VERSION 5.8 ;
BUSBITCHARS "[]" ;
DIVIDERCHAR "/" ;
UNITS
    DATABASE MICRONS 1000 ;
END UNITS

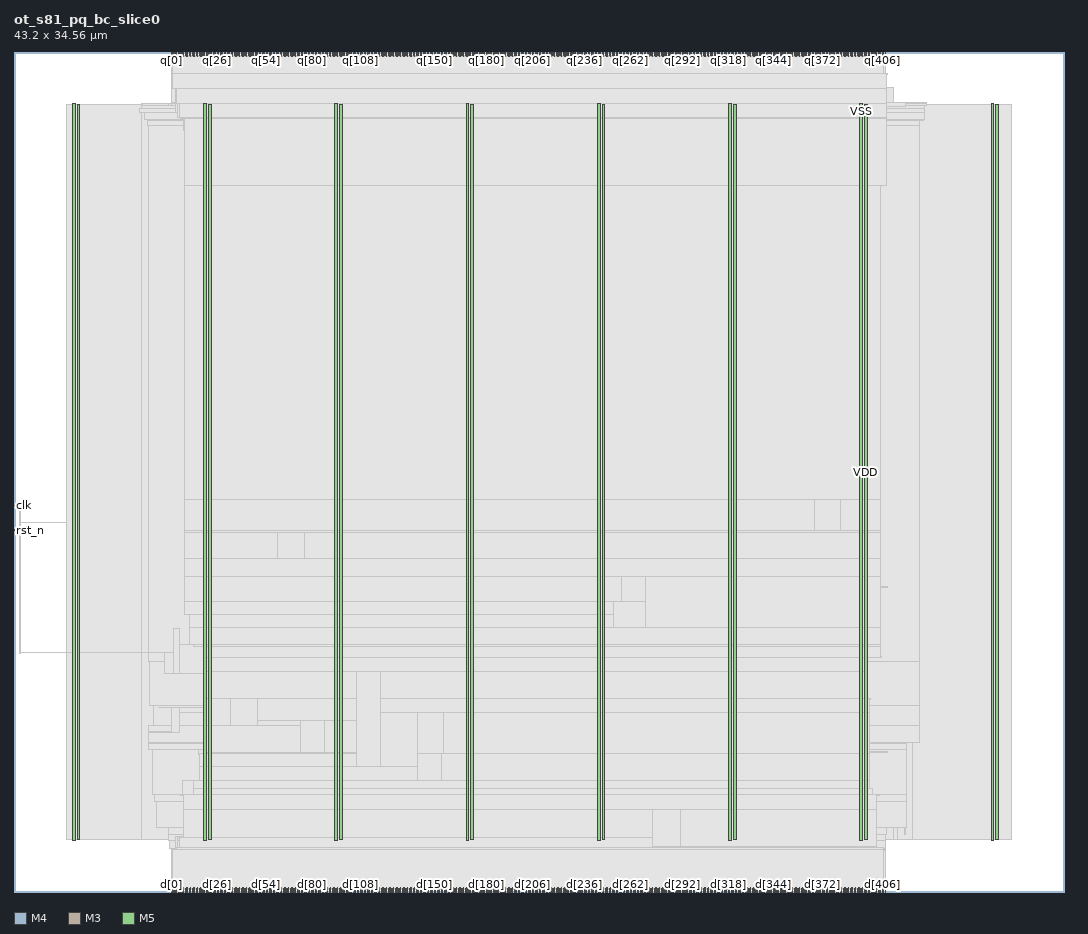
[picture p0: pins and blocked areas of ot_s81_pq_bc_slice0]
MACRO ot_s81_pq_bc_slice0
  FOREIGN ot_s81_pq_bc_slice0 0 0 ;
  CLASS BLOCK ;
  SIZE 43.2 BY 34.56 ;
  PIN clk
    DIRECTION INPUT ;
    USE SIGNAL ;
    PORT
      LAYER M4 ;
        RECT  0 15.888 0.192 15.912 ;
    END
    PORT
      LAYER M4 ;
        RECT  0.156 15.888 0.275 15.912 ;
    END
  END clk
  PIN d[0]
    DIRECTION INPUT ;
    USE SIGNAL ;
    PORT
      LAYER M3 ;
        RECT  6.48 0 6.498 0.144 ;
    END
  END d[0]
  PIN d[100]
    DIRECTION INPUT ;
    USE SIGNAL ;
    PORT
      LAYER M3 ;
        RECT  13.68 0 13.698 0.144 ;
    END
  END d[100]
  PIN d[101]
    DIRECTION INPUT ;
    USE SIGNAL ;
    PORT
      LAYER M5 ;
        RECT  13.728 0 13.752 0.192 ;
    END
  END d[101]
  PIN d[102]
    DIRECTION INPUT ;
    USE SIGNAL ;
    PORT
      LAYER M3 ;
        RECT  13.824 0 13.842 0.144 ;
    END
  END d[102]
  PIN d[103]
    DIRECTION INPUT ;
    USE SIGNAL ;
    PORT
      LAYER M5 ;
        RECT  13.872 0 13.896 0.192 ;
    END
  END d[103]
  PIN d[104]
    DIRECTION INPUT ;
    USE SIGNAL ;
    PORT
      LAYER M3 ;
        RECT  13.968 0 13.986 0.144 ;
    END
  END d[104]
  PIN d[105]
    DIRECTION INPUT ;
    USE SIGNAL ;
    PORT
      LAYER M5 ;
        RECT  14.016 0 14.04 0.192 ;
    END
  END d[105]
  PIN d[106]
    DIRECTION INPUT ;
    USE SIGNAL ;
    PORT
      LAYER M3 ;
        RECT  14.112 0 14.13 0.144 ;
    END
  END d[106]
  PIN d[107]
    DIRECTION INPUT ;
    USE SIGNAL ;
    PORT
      LAYER M5 ;
        RECT  14.16 0 14.184 0.192 ;
    END
  END d[107]
  PIN d[108]
    DIRECTION INPUT ;
    USE SIGNAL ;
    PORT
      LAYER M3 ;
        RECT  14.256 0 14.274 0.144 ;
    END
  END d[108]
  PIN d[109]
    DIRECTION INPUT ;
    USE SIGNAL ;
    PORT
      LAYER M5 ;
        RECT  14.304 0 14.328 0.192 ;
    END
  END d[109]
  PIN d[10]
    DIRECTION INPUT ;
    USE SIGNAL ;
    PORT
      LAYER M3 ;
        RECT  7.2 0 7.218 0.144 ;
    END
  END d[10]
  PIN d[110]
    DIRECTION INPUT ;
    USE SIGNAL ;
    PORT
      LAYER M3 ;
        RECT  14.4 0 14.418 0.144 ;
    END
  END d[110]
  PIN d[111]
    DIRECTION INPUT ;
    USE SIGNAL ;
    PORT
      LAYER M5 ;
        RECT  14.448 0 14.472 0.192 ;
    END
  END d[111]
  PIN d[112]
    DIRECTION INPUT ;
    USE SIGNAL ;
    PORT
      LAYER M3 ;
        RECT  14.544 0 14.562 0.144 ;
    END
  END d[112]
  PIN d[113]
    DIRECTION INPUT ;
    USE SIGNAL ;
    PORT
      LAYER M5 ;
        RECT  14.592 0 14.616 0.192 ;
    END
  END d[113]
  PIN d[114]
    DIRECTION INPUT ;
    USE SIGNAL ;
    PORT
      LAYER M3 ;
        RECT  14.688 0 14.706 0.144 ;
    END
  END d[114]
  PIN d[115]
    DIRECTION INPUT ;
    USE SIGNAL ;
    PORT
      LAYER M5 ;
        RECT  14.736 0 14.76 0.192 ;
    END
  END d[115]
  PIN d[116]
    DIRECTION INPUT ;
    USE SIGNAL ;
    PORT
      LAYER M3 ;
        RECT  14.832 0 14.85 0.144 ;
    END
  END d[116]
  PIN d[117]
    DIRECTION INPUT ;
    USE SIGNAL ;
    PORT
      LAYER M5 ;
        RECT  14.88 0 14.904 0.192 ;
    END
  END d[117]
  PIN d[118]
    DIRECTION INPUT ;
    USE SIGNAL ;
    PORT
      LAYER M3 ;
        RECT  14.976 0 14.994 0.144 ;
    END
  END d[118]
  PIN d[119]
    DIRECTION INPUT ;
    USE SIGNAL ;
    PORT
      LAYER M5 ;
        RECT  15.024 0 15.048 0.192 ;
    END
  END d[119]
  PIN d[11]
    DIRECTION INPUT ;
    USE SIGNAL ;
    PORT
      LAYER M5 ;
        RECT  7.248 0 7.272 0.192 ;
    END
  END d[11]
  PIN d[120]
    DIRECTION INPUT ;
    USE SIGNAL ;
    PORT
      LAYER M3 ;
        RECT  15.12 0 15.138 0.144 ;
    END
  END d[120]
  PIN d[121]
    DIRECTION INPUT ;
    USE SIGNAL ;
    PORT
      LAYER M5 ;
        RECT  15.168 0 15.192 0.192 ;
    END
  END d[121]
  PIN d[122]
    DIRECTION INPUT ;
    USE SIGNAL ;
    PORT
      LAYER M3 ;
        RECT  15.264 0 15.282 0.144 ;
    END
  END d[122]
  PIN d[123]
    DIRECTION INPUT ;
    USE SIGNAL ;
    PORT
      LAYER M5 ;
        RECT  15.312 0 15.336 0.192 ;
    END
  END d[123]
  PIN d[124]
    DIRECTION INPUT ;
    USE SIGNAL ;
    PORT
      LAYER M3 ;
        RECT  15.408 0 15.426 0.144 ;
    END
  END d[124]
  PIN d[125]
    DIRECTION INPUT ;
    USE SIGNAL ;
    PORT
      LAYER M5 ;
        RECT  15.456 0 15.48 0.192 ;
    END
  END d[125]
  PIN d[126]
    DIRECTION INPUT ;
    USE SIGNAL ;
    PORT
      LAYER M3 ;
        RECT  15.552 0 15.57 0.144 ;
    END
  END d[126]
  PIN d[127]
    DIRECTION INPUT ;
    USE SIGNAL ;
    PORT
      LAYER M5 ;
        RECT  15.6 0 15.624 0.192 ;
    END
  END d[127]
  PIN d[128]
    DIRECTION INPUT ;
    USE SIGNAL ;
    PORT
      LAYER M3 ;
        RECT  15.696 0 15.714 0.144 ;
    END
  END d[128]
  PIN d[129]
    DIRECTION INPUT ;
    USE SIGNAL ;
    PORT
      LAYER M5 ;
        RECT  15.744 0 15.768 0.192 ;
    END
  END d[129]
  PIN d[12]
    DIRECTION INPUT ;
    USE SIGNAL ;
    PORT
      LAYER M3 ;
        RECT  7.344 0 7.362 0.144 ;
    END
  END d[12]
  PIN d[130]
    DIRECTION INPUT ;
    USE SIGNAL ;
    PORT
      LAYER M3 ;
        RECT  15.84 0 15.858 0.144 ;
    END
  END d[130]
  PIN d[131]
    DIRECTION INPUT ;
    USE SIGNAL ;
    PORT
      LAYER M5 ;
        RECT  15.888 0 15.912 0.192 ;
    END
  END d[131]
  PIN d[132]
    DIRECTION INPUT ;
    USE SIGNAL ;
    PORT
      LAYER M3 ;
        RECT  15.984 0 16.002 0.144 ;
    END
  END d[132]
  PIN d[133]
    DIRECTION INPUT ;
    USE SIGNAL ;
    PORT
      LAYER M5 ;
        RECT  16.032 0 16.056 0.192 ;
    END
  END d[133]
  PIN d[134]
    DIRECTION INPUT ;
    USE SIGNAL ;
    PORT
      LAYER M3 ;
        RECT  16.128 0 16.146 0.144 ;
    END
  END d[134]
  PIN d[135]
    DIRECTION INPUT ;
    USE SIGNAL ;
    PORT
      LAYER M5 ;
        RECT  16.176 0 16.2 0.192 ;
    END
  END d[135]
  PIN d[136]
    DIRECTION INPUT ;
    USE SIGNAL ;
    PORT
      LAYER M3 ;
        RECT  16.272 0 16.29 0.144 ;
    END
  END d[136]
  PIN d[137]
    DIRECTION INPUT ;
    USE SIGNAL ;
    PORT
      LAYER M5 ;
        RECT  16.32 0 16.344 0.192 ;
    END
  END d[137]
  PIN d[138]
    DIRECTION INPUT ;
    USE SIGNAL ;
    PORT
      LAYER M3 ;
        RECT  16.416 0 16.434 0.144 ;
    END
  END d[138]
  PIN d[139]
    DIRECTION INPUT ;
    USE SIGNAL ;
    PORT
      LAYER M5 ;
        RECT  16.464 0 16.488 0.192 ;
    END
  END d[139]
  PIN d[13]
    DIRECTION INPUT ;
    USE SIGNAL ;
    PORT
      LAYER M5 ;
        RECT  7.392 0 7.416 0.192 ;
    END
  END d[13]
  PIN d[140]
    DIRECTION INPUT ;
    USE SIGNAL ;
    PORT
      LAYER M3 ;
        RECT  16.56 0 16.578 0.144 ;
    END
  END d[140]
  PIN d[141]
    DIRECTION INPUT ;
    USE SIGNAL ;
    PORT
      LAYER M5 ;
        RECT  16.608 0 16.632 0.192 ;
    END
  END d[141]
  PIN d[142]
    DIRECTION INPUT ;
    USE SIGNAL ;
    PORT
      LAYER M3 ;
        RECT  16.704 0 16.722 0.144 ;
    END
  END d[142]
  PIN d[143]
    DIRECTION INPUT ;
    USE SIGNAL ;
    PORT
      LAYER M5 ;
        RECT  16.752 0 16.776 0.192 ;
    END
  END d[143]
  PIN d[144]
    DIRECTION INPUT ;
    USE SIGNAL ;
    PORT
      LAYER M3 ;
        RECT  16.848 0 16.866 0.144 ;
    END
  END d[144]
  PIN d[145]
    DIRECTION INPUT ;
    USE SIGNAL ;
    PORT
      LAYER M5 ;
        RECT  16.896 0 16.92 0.192 ;
    END
  END d[145]
  PIN d[146]
    DIRECTION INPUT ;
    USE SIGNAL ;
    PORT
      LAYER M3 ;
        RECT  16.992 0 17.01 0.144 ;
    END
  END d[146]
  PIN d[147]
    DIRECTION INPUT ;
    USE SIGNAL ;
    PORT
      LAYER M5 ;
        RECT  17.04 0 17.064 0.192 ;
    END
  END d[147]
  PIN d[148]
    DIRECTION INPUT ;
    USE SIGNAL ;
    PORT
      LAYER M3 ;
        RECT  17.136 0 17.154 0.144 ;
    END
  END d[148]
  PIN d[149]
    DIRECTION INPUT ;
    USE SIGNAL ;
    PORT
      LAYER M5 ;
        RECT  17.184 0 17.208 0.192 ;
    END
  END d[149]
  PIN d[14]
    DIRECTION INPUT ;
    USE SIGNAL ;
    PORT
      LAYER M3 ;
        RECT  7.488 0 7.506 0.144 ;
    END
  END d[14]
  PIN d[150]
    DIRECTION INPUT ;
    USE SIGNAL ;
    PORT
      LAYER M3 ;
        RECT  17.28 0 17.298 0.144 ;
    END
  END d[150]
  PIN d[151]
    DIRECTION INPUT ;
    USE SIGNAL ;
    PORT
      LAYER M5 ;
        RECT  17.328 0 17.352 0.192 ;
    END
  END d[151]
  PIN d[152]
    DIRECTION INPUT ;
    USE SIGNAL ;
    PORT
      LAYER M3 ;
        RECT  17.424 0 17.442 0.144 ;
    END
  END d[152]
  PIN d[153]
    DIRECTION INPUT ;
    USE SIGNAL ;
    PORT
      LAYER M5 ;
        RECT  17.472 0 17.496 0.192 ;
    END
  END d[153]
  PIN d[154]
    DIRECTION INPUT ;
    USE SIGNAL ;
    PORT
      LAYER M3 ;
        RECT  17.568 0 17.586 0.144 ;
    END
  END d[154]
  PIN d[155]
    DIRECTION INPUT ;
    USE SIGNAL ;
    PORT
      LAYER M5 ;
        RECT  17.616 0 17.64 0.192 ;
    END
  END d[155]
  PIN d[156]
    DIRECTION INPUT ;
    USE SIGNAL ;
    PORT
      LAYER M3 ;
        RECT  17.712 0 17.73 0.144 ;
    END
  END d[156]
  PIN d[157]
    DIRECTION INPUT ;
    USE SIGNAL ;
    PORT
      LAYER M5 ;
        RECT  17.76 0 17.784 0.192 ;
    END
  END d[157]
  PIN d[158]
    DIRECTION INPUT ;
    USE SIGNAL ;
    PORT
      LAYER M3 ;
        RECT  17.856 0 17.874 0.144 ;
    END
  END d[158]
  PIN d[159]
    DIRECTION INPUT ;
    USE SIGNAL ;
    PORT
      LAYER M5 ;
        RECT  17.904 0 17.928 0.192 ;
    END
  END d[159]
  PIN d[15]
    DIRECTION INPUT ;
    USE SIGNAL ;
    PORT
      LAYER M5 ;
        RECT  7.536 0 7.56 0.192 ;
    END
  END d[15]
  PIN d[160]
    DIRECTION INPUT ;
    USE SIGNAL ;
    PORT
      LAYER M3 ;
        RECT  18 0 18.018 0.144 ;
    END
  END d[160]
  PIN d[161]
    DIRECTION INPUT ;
    USE SIGNAL ;
    PORT
      LAYER M5 ;
        RECT  18.048 0 18.072 0.192 ;
    END
  END d[161]
  PIN d[162]
    DIRECTION INPUT ;
    USE SIGNAL ;
    PORT
      LAYER M3 ;
        RECT  18.144 0 18.162 0.144 ;
    END
  END d[162]
  PIN d[163]
    DIRECTION INPUT ;
    USE SIGNAL ;
    PORT
      LAYER M5 ;
        RECT  18.192 0 18.216 0.192 ;
    END
  END d[163]
  PIN d[164]
    DIRECTION INPUT ;
    USE SIGNAL ;
    PORT
      LAYER M3 ;
        RECT  18.288 0 18.306 0.144 ;
    END
  END d[164]
  PIN d[165]
    DIRECTION INPUT ;
    USE SIGNAL ;
    PORT
      LAYER M5 ;
        RECT  18.336 0 18.36 0.192 ;
    END
  END d[165]
  PIN d[166]
    DIRECTION INPUT ;
    USE SIGNAL ;
    PORT
      LAYER M3 ;
        RECT  18.432 0 18.45 0.144 ;
    END
  END d[166]
  PIN d[167]
    DIRECTION INPUT ;
    USE SIGNAL ;
    PORT
      LAYER M5 ;
        RECT  18.48 0 18.504 0.192 ;
    END
  END d[167]
  PIN d[168]
    DIRECTION INPUT ;
    USE SIGNAL ;
    PORT
      LAYER M3 ;
        RECT  18.576 0 18.594 0.144 ;
    END
  END d[168]
  PIN d[169]
    DIRECTION INPUT ;
    USE SIGNAL ;
    PORT
      LAYER M5 ;
        RECT  18.624 0 18.648 0.192 ;
    END
  END d[169]
  PIN d[16]
    DIRECTION INPUT ;
    USE SIGNAL ;
    PORT
      LAYER M3 ;
        RECT  7.632 0 7.65 0.144 ;
    END
  END d[16]
  PIN d[170]
    DIRECTION INPUT ;
    USE SIGNAL ;
    PORT
      LAYER M3 ;
        RECT  18.72 0 18.738 0.144 ;
    END
  END d[170]
  PIN d[171]
    DIRECTION INPUT ;
    USE SIGNAL ;
    PORT
      LAYER M5 ;
        RECT  18.768 0 18.792 0.192 ;
    END
  END d[171]
  PIN d[172]
    DIRECTION INPUT ;
    USE SIGNAL ;
    PORT
      LAYER M3 ;
        RECT  18.864 0 18.882 0.144 ;
    END
  END d[172]
  PIN d[173]
    DIRECTION INPUT ;
    USE SIGNAL ;
    PORT
      LAYER M5 ;
        RECT  18.912 0 18.936 0.192 ;
    END
  END d[173]
  PIN d[174]
    DIRECTION INPUT ;
    USE SIGNAL ;
    PORT
      LAYER M3 ;
        RECT  19.008 0 19.026 0.144 ;
    END
  END d[174]
  PIN d[175]
    DIRECTION INPUT ;
    USE SIGNAL ;
    PORT
      LAYER M5 ;
        RECT  19.056 0 19.08 0.192 ;
    END
  END d[175]
  PIN d[176]
    DIRECTION INPUT ;
    USE SIGNAL ;
    PORT
      LAYER M3 ;
        RECT  19.152 0 19.17 0.144 ;
    END
  END d[176]
  PIN d[177]
    DIRECTION INPUT ;
    USE SIGNAL ;
    PORT
      LAYER M5 ;
        RECT  19.2 0 19.224 0.192 ;
    END
  END d[177]
  PIN d[178]
    DIRECTION INPUT ;
    USE SIGNAL ;
    PORT
      LAYER M3 ;
        RECT  19.296 0 19.314 0.144 ;
    END
  END d[178]
  PIN d[179]
    DIRECTION INPUT ;
    USE SIGNAL ;
    PORT
      LAYER M5 ;
        RECT  19.344 0 19.368 0.192 ;
    END
  END d[179]
  PIN d[17]
    DIRECTION INPUT ;
    USE SIGNAL ;
    PORT
      LAYER M5 ;
        RECT  7.68 0 7.704 0.192 ;
    END
  END d[17]
  PIN d[180]
    DIRECTION INPUT ;
    USE SIGNAL ;
    PORT
      LAYER M3 ;
        RECT  19.44 0 19.458 0.144 ;
    END
  END d[180]
  PIN d[181]
    DIRECTION INPUT ;
    USE SIGNAL ;
    PORT
      LAYER M5 ;
        RECT  19.488 0 19.512 0.192 ;
    END
  END d[181]
  PIN d[182]
    DIRECTION INPUT ;
    USE SIGNAL ;
    PORT
      LAYER M3 ;
        RECT  19.584 0 19.602 0.144 ;
    END
  END d[182]
  PIN d[183]
    DIRECTION INPUT ;
    USE SIGNAL ;
    PORT
      LAYER M5 ;
        RECT  19.632 0 19.656 0.192 ;
    END
  END d[183]
  PIN d[184]
    DIRECTION INPUT ;
    USE SIGNAL ;
    PORT
      LAYER M3 ;
        RECT  19.728 0 19.746 0.144 ;
    END
  END d[184]
  PIN d[185]
    DIRECTION INPUT ;
    USE SIGNAL ;
    PORT
      LAYER M5 ;
        RECT  19.776 0 19.8 0.192 ;
    END
  END d[185]
  PIN d[186]
    DIRECTION INPUT ;
    USE SIGNAL ;
    PORT
      LAYER M3 ;
        RECT  19.872 0 19.89 0.144 ;
    END
  END d[186]
  PIN d[187]
    DIRECTION INPUT ;
    USE SIGNAL ;
    PORT
      LAYER M5 ;
        RECT  19.92 0 19.944 0.192 ;
    END
  END d[187]
  PIN d[188]
    DIRECTION INPUT ;
    USE SIGNAL ;
    PORT
      LAYER M3 ;
        RECT  20.016 0 20.034 0.144 ;
    END
  END d[188]
  PIN d[189]
    DIRECTION INPUT ;
    USE SIGNAL ;
    PORT
      LAYER M5 ;
        RECT  20.064 0 20.088 0.192 ;
    END
  END d[189]
  PIN d[18]
    DIRECTION INPUT ;
    USE SIGNAL ;
    PORT
      LAYER M3 ;
        RECT  7.776 0 7.794 0.144 ;
    END
  END d[18]
  PIN d[190]
    DIRECTION INPUT ;
    USE SIGNAL ;
    PORT
      LAYER M3 ;
        RECT  20.16 0 20.178 0.144 ;
    END
  END d[190]
  PIN d[191]
    DIRECTION INPUT ;
    USE SIGNAL ;
    PORT
      LAYER M5 ;
        RECT  20.208 0 20.232 0.192 ;
    END
  END d[191]
  PIN d[192]
    DIRECTION INPUT ;
    USE SIGNAL ;
    PORT
      LAYER M3 ;
        RECT  20.304 0 20.322 0.144 ;
    END
  END d[192]
  PIN d[193]
    DIRECTION INPUT ;
    USE SIGNAL ;
    PORT
      LAYER M5 ;
        RECT  20.352 0 20.376 0.192 ;
    END
  END d[193]
  PIN d[194]
    DIRECTION INPUT ;
    USE SIGNAL ;
    PORT
      LAYER M3 ;
        RECT  20.448 0 20.466 0.144 ;
    END
  END d[194]
  PIN d[195]
    DIRECTION INPUT ;
    USE SIGNAL ;
    PORT
      LAYER M5 ;
        RECT  20.496 0 20.52 0.192 ;
    END
  END d[195]
  PIN d[196]
    DIRECTION INPUT ;
    USE SIGNAL ;
    PORT
      LAYER M3 ;
        RECT  20.592 0 20.61 0.144 ;
    END
  END d[196]
  PIN d[197]
    DIRECTION INPUT ;
    USE SIGNAL ;
    PORT
      LAYER M5 ;
        RECT  20.64 0 20.664 0.192 ;
    END
  END d[197]
  PIN d[198]
    DIRECTION INPUT ;
    USE SIGNAL ;
    PORT
      LAYER M3 ;
        RECT  20.736 0 20.754 0.144 ;
    END
  END d[198]
  PIN d[199]
    DIRECTION INPUT ;
    USE SIGNAL ;
    PORT
      LAYER M5 ;
        RECT  20.784 0 20.808 0.192 ;
    END
  END d[199]
  PIN d[19]
    DIRECTION INPUT ;
    USE SIGNAL ;
    PORT
      LAYER M5 ;
        RECT  7.824 0 7.848 0.192 ;
    END
  END d[19]
  PIN d[1]
    DIRECTION INPUT ;
    USE SIGNAL ;
    PORT
      LAYER M5 ;
        RECT  6.528 0 6.552 0.192 ;
    END
  END d[1]
  PIN d[200]
    DIRECTION INPUT ;
    USE SIGNAL ;
    PORT
      LAYER M3 ;
        RECT  20.88 0 20.898 0.144 ;
    END
  END d[200]
  PIN d[201]
    DIRECTION INPUT ;
    USE SIGNAL ;
    PORT
      LAYER M5 ;
        RECT  20.928 0 20.952 0.192 ;
    END
  END d[201]
  PIN d[202]
    DIRECTION INPUT ;
    USE SIGNAL ;
    PORT
      LAYER M3 ;
        RECT  21.024 0 21.042 0.144 ;
    END
  END d[202]
  PIN d[203]
    DIRECTION INPUT ;
    USE SIGNAL ;
    PORT
      LAYER M5 ;
        RECT  21.072 0 21.096 0.192 ;
    END
  END d[203]
  PIN d[204]
    DIRECTION INPUT ;
    USE SIGNAL ;
    PORT
      LAYER M3 ;
        RECT  21.168 0 21.186 0.144 ;
    END
  END d[204]
  PIN d[205]
    DIRECTION INPUT ;
    USE SIGNAL ;
    PORT
      LAYER M5 ;
        RECT  21.216 0 21.24 0.192 ;
    END
  END d[205]
  PIN d[206]
    DIRECTION INPUT ;
    USE SIGNAL ;
    PORT
      LAYER M3 ;
        RECT  21.312 0 21.33 0.144 ;
    END
  END d[206]
  PIN d[207]
    DIRECTION INPUT ;
    USE SIGNAL ;
    PORT
      LAYER M5 ;
        RECT  21.36 0 21.384 0.192 ;
    END
  END d[207]
  PIN d[208]
    DIRECTION INPUT ;
    USE SIGNAL ;
    PORT
      LAYER M3 ;
        RECT  21.456 0 21.474 0.144 ;
    END
  END d[208]
  PIN d[209]
    DIRECTION INPUT ;
    USE SIGNAL ;
    PORT
      LAYER M5 ;
        RECT  21.504 0 21.528 0.192 ;
    END
  END d[209]
  PIN d[20]
    DIRECTION INPUT ;
    USE SIGNAL ;
    PORT
      LAYER M3 ;
        RECT  7.92 0 7.938 0.144 ;
    END
  END d[20]
  PIN d[210]
    DIRECTION INPUT ;
    USE SIGNAL ;
    PORT
      LAYER M3 ;
        RECT  21.6 0 21.618 0.144 ;
    END
  END d[210]
  PIN d[211]
    DIRECTION INPUT ;
    USE SIGNAL ;
    PORT
      LAYER M5 ;
        RECT  21.648 0 21.672 0.192 ;
    END
  END d[211]
  PIN d[212]
    DIRECTION INPUT ;
    USE SIGNAL ;
    PORT
      LAYER M3 ;
        RECT  21.744 0 21.762 0.144 ;
    END
  END d[212]
  PIN d[213]
    DIRECTION INPUT ;
    USE SIGNAL ;
    PORT
      LAYER M5 ;
        RECT  21.792 0 21.816 0.192 ;
    END
  END d[213]
  PIN d[214]
    DIRECTION INPUT ;
    USE SIGNAL ;
    PORT
      LAYER M3 ;
        RECT  21.888 0 21.906 0.144 ;
    END
  END d[214]
  PIN d[215]
    DIRECTION INPUT ;
    USE SIGNAL ;
    PORT
      LAYER M5 ;
        RECT  21.936 0 21.96 0.192 ;
    END
  END d[215]
  PIN d[216]
    DIRECTION INPUT ;
    USE SIGNAL ;
    PORT
      LAYER M3 ;
        RECT  22.032 0 22.05 0.144 ;
    END
  END d[216]
  PIN d[217]
    DIRECTION INPUT ;
    USE SIGNAL ;
    PORT
      LAYER M5 ;
        RECT  22.08 0 22.104 0.192 ;
    END
  END d[217]
  PIN d[218]
    DIRECTION INPUT ;
    USE SIGNAL ;
    PORT
      LAYER M3 ;
        RECT  22.176 0 22.194 0.144 ;
    END
  END d[218]
  PIN d[219]
    DIRECTION INPUT ;
    USE SIGNAL ;
    PORT
      LAYER M5 ;
        RECT  22.224 0 22.248 0.192 ;
    END
  END d[219]
  PIN d[21]
    DIRECTION INPUT ;
    USE SIGNAL ;
    PORT
      LAYER M5 ;
        RECT  7.968 0 7.992 0.192 ;
    END
  END d[21]
  PIN d[220]
    DIRECTION INPUT ;
    USE SIGNAL ;
    PORT
      LAYER M3 ;
        RECT  22.32 0 22.338 0.144 ;
    END
  END d[220]
  PIN d[221]
    DIRECTION INPUT ;
    USE SIGNAL ;
    PORT
      LAYER M5 ;
        RECT  22.368 0 22.392 0.192 ;
    END
  END d[221]
  PIN d[222]
    DIRECTION INPUT ;
    USE SIGNAL ;
    PORT
      LAYER M3 ;
        RECT  22.464 0 22.482 0.144 ;
    END
  END d[222]
  PIN d[223]
    DIRECTION INPUT ;
    USE SIGNAL ;
    PORT
      LAYER M5 ;
        RECT  22.512 0 22.536 0.192 ;
    END
  END d[223]
  PIN d[224]
    DIRECTION INPUT ;
    USE SIGNAL ;
    PORT
      LAYER M3 ;
        RECT  22.608 0 22.626 0.144 ;
    END
  END d[224]
  PIN d[225]
    DIRECTION INPUT ;
    USE SIGNAL ;
    PORT
      LAYER M5 ;
        RECT  22.656 0 22.68 0.192 ;
    END
  END d[225]
  PIN d[226]
    DIRECTION INPUT ;
    USE SIGNAL ;
    PORT
      LAYER M3 ;
        RECT  22.752 0 22.77 0.144 ;
    END
  END d[226]
  PIN d[227]
    DIRECTION INPUT ;
    USE SIGNAL ;
    PORT
      LAYER M5 ;
        RECT  22.8 0 22.824 0.192 ;
    END
  END d[227]
  PIN d[228]
    DIRECTION INPUT ;
    USE SIGNAL ;
    PORT
      LAYER M3 ;
        RECT  22.896 0 22.914 0.144 ;
    END
  END d[228]
  PIN d[229]
    DIRECTION INPUT ;
    USE SIGNAL ;
    PORT
      LAYER M5 ;
        RECT  22.944 0 22.968 0.192 ;
    END
  END d[229]
  PIN d[22]
    DIRECTION INPUT ;
    USE SIGNAL ;
    PORT
      LAYER M3 ;
        RECT  8.064 0 8.082 0.144 ;
    END
  END d[22]
  PIN d[230]
    DIRECTION INPUT ;
    USE SIGNAL ;
    PORT
      LAYER M3 ;
        RECT  23.04 0 23.058 0.144 ;
    END
  END d[230]
  PIN d[231]
    DIRECTION INPUT ;
    USE SIGNAL ;
    PORT
      LAYER M5 ;
        RECT  23.088 0 23.112 0.192 ;
    END
  END d[231]
  PIN d[232]
    DIRECTION INPUT ;
    USE SIGNAL ;
    PORT
      LAYER M3 ;
        RECT  23.184 0 23.202 0.144 ;
    END
  END d[232]
  PIN d[233]
    DIRECTION INPUT ;
    USE SIGNAL ;
    PORT
      LAYER M5 ;
        RECT  23.232 0 23.256 0.192 ;
    END
  END d[233]
  PIN d[234]
    DIRECTION INPUT ;
    USE SIGNAL ;
    PORT
      LAYER M3 ;
        RECT  23.328 0 23.346 0.144 ;
    END
  END d[234]
  PIN d[235]
    DIRECTION INPUT ;
    USE SIGNAL ;
    PORT
      LAYER M5 ;
        RECT  23.376 0 23.4 0.192 ;
    END
  END d[235]
  PIN d[236]
    DIRECTION INPUT ;
    USE SIGNAL ;
    PORT
      LAYER M3 ;
        RECT  23.472 0 23.49 0.144 ;
    END
  END d[236]
  PIN d[237]
    DIRECTION INPUT ;
    USE SIGNAL ;
    PORT
      LAYER M5 ;
        RECT  23.52 0 23.544 0.192 ;
    END
  END d[237]
  PIN d[238]
    DIRECTION INPUT ;
    USE SIGNAL ;
    PORT
      LAYER M3 ;
        RECT  23.616 0 23.634 0.144 ;
    END
  END d[238]
  PIN d[239]
    DIRECTION INPUT ;
    USE SIGNAL ;
    PORT
      LAYER M5 ;
        RECT  23.664 0 23.688 0.192 ;
    END
  END d[239]
  PIN d[23]
    DIRECTION INPUT ;
    USE SIGNAL ;
    PORT
      LAYER M5 ;
        RECT  8.112 0 8.136 0.192 ;
    END
  END d[23]
  PIN d[240]
    DIRECTION INPUT ;
    USE SIGNAL ;
    PORT
      LAYER M3 ;
        RECT  23.76 0 23.778 0.144 ;
    END
  END d[240]
  PIN d[241]
    DIRECTION INPUT ;
    USE SIGNAL ;
    PORT
      LAYER M5 ;
        RECT  23.808 0 23.832 0.192 ;
    END
  END d[241]
  PIN d[242]
    DIRECTION INPUT ;
    USE SIGNAL ;
    PORT
      LAYER M3 ;
        RECT  23.904 0 23.922 0.144 ;
    END
  END d[242]
  PIN d[243]
    DIRECTION INPUT ;
    USE SIGNAL ;
    PORT
      LAYER M5 ;
        RECT  23.952 0 23.976 0.192 ;
    END
  END d[243]
  PIN d[244]
    DIRECTION INPUT ;
    USE SIGNAL ;
    PORT
      LAYER M3 ;
        RECT  24.048 0 24.066 0.144 ;
    END
  END d[244]
  PIN d[245]
    DIRECTION INPUT ;
    USE SIGNAL ;
    PORT
      LAYER M5 ;
        RECT  24.096 0 24.12 0.192 ;
    END
  END d[245]
  PIN d[246]
    DIRECTION INPUT ;
    USE SIGNAL ;
    PORT
      LAYER M3 ;
        RECT  24.192 0 24.21 0.144 ;
    END
  END d[246]
  PIN d[247]
    DIRECTION INPUT ;
    USE SIGNAL ;
    PORT
      LAYER M5 ;
        RECT  24.24 0 24.264 0.192 ;
    END
  END d[247]
  PIN d[248]
    DIRECTION INPUT ;
    USE SIGNAL ;
    PORT
      LAYER M3 ;
        RECT  24.336 0 24.354 0.144 ;
    END
  END d[248]
  PIN d[249]
    DIRECTION INPUT ;
    USE SIGNAL ;
    PORT
      LAYER M5 ;
        RECT  24.384 0 24.408 0.192 ;
    END
  END d[249]
  PIN d[24]
    DIRECTION INPUT ;
    USE SIGNAL ;
    PORT
      LAYER M3 ;
        RECT  8.208 0 8.226 0.144 ;
    END
  END d[24]
  PIN d[250]
    DIRECTION INPUT ;
    USE SIGNAL ;
    PORT
      LAYER M3 ;
        RECT  24.48 0 24.498 0.144 ;
    END
  END d[250]
  PIN d[251]
    DIRECTION INPUT ;
    USE SIGNAL ;
    PORT
      LAYER M5 ;
        RECT  24.528 0 24.552 0.192 ;
    END
  END d[251]
  PIN d[252]
    DIRECTION INPUT ;
    USE SIGNAL ;
    PORT
      LAYER M3 ;
        RECT  24.624 0 24.642 0.144 ;
    END
  END d[252]
  PIN d[253]
    DIRECTION INPUT ;
    USE SIGNAL ;
    PORT
      LAYER M5 ;
        RECT  24.672 0 24.696 0.192 ;
    END
  END d[253]
  PIN d[254]
    DIRECTION INPUT ;
    USE SIGNAL ;
    PORT
      LAYER M3 ;
        RECT  24.768 0 24.786 0.144 ;
    END
  END d[254]
  PIN d[255]
    DIRECTION INPUT ;
    USE SIGNAL ;
    PORT
      LAYER M5 ;
        RECT  24.816 0 24.84 0.192 ;
    END
  END d[255]
  PIN d[256]
    DIRECTION INPUT ;
    USE SIGNAL ;
    PORT
      LAYER M3 ;
        RECT  24.912 0 24.93 0.144 ;
    END
  END d[256]
  PIN d[257]
    DIRECTION INPUT ;
    USE SIGNAL ;
    PORT
      LAYER M5 ;
        RECT  24.96 0 24.984 0.192 ;
    END
  END d[257]
  PIN d[258]
    DIRECTION INPUT ;
    USE SIGNAL ;
    PORT
      LAYER M3 ;
        RECT  25.056 0 25.074 0.144 ;
    END
  END d[258]
  PIN d[259]
    DIRECTION INPUT ;
    USE SIGNAL ;
    PORT
      LAYER M5 ;
        RECT  25.104 0 25.128 0.192 ;
    END
  END d[259]
  PIN d[25]
    DIRECTION INPUT ;
    USE SIGNAL ;
    PORT
      LAYER M5 ;
        RECT  8.256 0 8.28 0.192 ;
    END
  END d[25]
  PIN d[260]
    DIRECTION INPUT ;
    USE SIGNAL ;
    PORT
      LAYER M3 ;
        RECT  25.2 0 25.218 0.144 ;
    END
  END d[260]
  PIN d[261]
    DIRECTION INPUT ;
    USE SIGNAL ;
    PORT
      LAYER M5 ;
        RECT  25.248 0 25.272 0.192 ;
    END
  END d[261]
  PIN d[262]
    DIRECTION INPUT ;
    USE SIGNAL ;
    PORT
      LAYER M3 ;
        RECT  25.344 0 25.362 0.144 ;
    END
  END d[262]
  PIN d[263]
    DIRECTION INPUT ;
    USE SIGNAL ;
    PORT
      LAYER M5 ;
        RECT  25.392 0 25.416 0.192 ;
    END
  END d[263]
  PIN d[264]
    DIRECTION INPUT ;
    USE SIGNAL ;
    PORT
      LAYER M3 ;
        RECT  25.488 0 25.506 0.144 ;
    END
  END d[264]
  PIN d[265]
    DIRECTION INPUT ;
    USE SIGNAL ;
    PORT
      LAYER M5 ;
        RECT  25.536 0 25.56 0.192 ;
    END
  END d[265]
  PIN d[266]
    DIRECTION INPUT ;
    USE SIGNAL ;
    PORT
      LAYER M3 ;
        RECT  25.632 0 25.65 0.144 ;
    END
  END d[266]
  PIN d[267]
    DIRECTION INPUT ;
    USE SIGNAL ;
    PORT
      LAYER M5 ;
        RECT  25.68 0 25.704 0.192 ;
    END
  END d[267]
  PIN d[268]
    DIRECTION INPUT ;
    USE SIGNAL ;
    PORT
      LAYER M3 ;
        RECT  25.776 0 25.794 0.144 ;
    END
  END d[268]
  PIN d[269]
    DIRECTION INPUT ;
    USE SIGNAL ;
    PORT
      LAYER M5 ;
        RECT  25.824 0 25.848 0.192 ;
    END
  END d[269]
  PIN d[26]
    DIRECTION INPUT ;
    USE SIGNAL ;
    PORT
      LAYER M3 ;
        RECT  8.352 0 8.37 0.144 ;
    END
  END d[26]
  PIN d[270]
    DIRECTION INPUT ;
    USE SIGNAL ;
    PORT
      LAYER M3 ;
        RECT  25.92 0 25.938 0.144 ;
    END
  END d[270]
  PIN d[271]
    DIRECTION INPUT ;
    USE SIGNAL ;
    PORT
      LAYER M5 ;
        RECT  25.968 0 25.992 0.192 ;
    END
  END d[271]
  PIN d[272]
    DIRECTION INPUT ;
    USE SIGNAL ;
    PORT
      LAYER M3 ;
        RECT  26.064 0 26.082 0.144 ;
    END
  END d[272]
  PIN d[273]
    DIRECTION INPUT ;
    USE SIGNAL ;
    PORT
      LAYER M5 ;
        RECT  26.112 0 26.136 0.192 ;
    END
  END d[273]
  PIN d[274]
    DIRECTION INPUT ;
    USE SIGNAL ;
    PORT
      LAYER M3 ;
        RECT  26.208 0 26.226 0.144 ;
    END
  END d[274]
  PIN d[275]
    DIRECTION INPUT ;
    USE SIGNAL ;
    PORT
      LAYER M5 ;
        RECT  26.256 0 26.28 0.192 ;
    END
  END d[275]
  PIN d[276]
    DIRECTION INPUT ;
    USE SIGNAL ;
    PORT
      LAYER M3 ;
        RECT  26.352 0 26.37 0.144 ;
    END
  END d[276]
  PIN d[277]
    DIRECTION INPUT ;
    USE SIGNAL ;
    PORT
      LAYER M5 ;
        RECT  26.4 0 26.424 0.192 ;
    END
  END d[277]
  PIN d[278]
    DIRECTION INPUT ;
    USE SIGNAL ;
    PORT
      LAYER M3 ;
        RECT  26.496 0 26.514 0.144 ;
    END
  END d[278]
  PIN d[279]
    DIRECTION INPUT ;
    USE SIGNAL ;
    PORT
      LAYER M5 ;
        RECT  26.544 0 26.568 0.192 ;
    END
  END d[279]
  PIN d[27]
    DIRECTION INPUT ;
    USE SIGNAL ;
    PORT
      LAYER M5 ;
        RECT  8.4 0 8.424 0.192 ;
    END
  END d[27]
  PIN d[280]
    DIRECTION INPUT ;
    USE SIGNAL ;
    PORT
      LAYER M3 ;
        RECT  26.64 0 26.658 0.144 ;
    END
  END d[280]
  PIN d[281]
    DIRECTION INPUT ;
    USE SIGNAL ;
    PORT
      LAYER M5 ;
        RECT  26.688 0 26.712 0.192 ;
    END
  END d[281]
  PIN d[282]
    DIRECTION INPUT ;
    USE SIGNAL ;
    PORT
      LAYER M3 ;
        RECT  26.784 0 26.802 0.144 ;
    END
  END d[282]
  PIN d[283]
    DIRECTION INPUT ;
    USE SIGNAL ;
    PORT
      LAYER M5 ;
        RECT  26.832 0 26.856 0.192 ;
    END
  END d[283]
  PIN d[284]
    DIRECTION INPUT ;
    USE SIGNAL ;
    PORT
      LAYER M3 ;
        RECT  26.928 0 26.946 0.144 ;
    END
  END d[284]
  PIN d[285]
    DIRECTION INPUT ;
    USE SIGNAL ;
    PORT
      LAYER M5 ;
        RECT  26.976 0 27 0.192 ;
    END
  END d[285]
  PIN d[286]
    DIRECTION INPUT ;
    USE SIGNAL ;
    PORT
      LAYER M3 ;
        RECT  27.072 0 27.09 0.144 ;
    END
  END d[286]
  PIN d[287]
    DIRECTION INPUT ;
    USE SIGNAL ;
    PORT
      LAYER M5 ;
        RECT  27.12 0 27.144 0.192 ;
    END
  END d[287]
  PIN d[288]
    DIRECTION INPUT ;
    USE SIGNAL ;
    PORT
      LAYER M3 ;
        RECT  27.216 0 27.234 0.144 ;
    END
  END d[288]
  PIN d[289]
    DIRECTION INPUT ;
    USE SIGNAL ;
    PORT
      LAYER M5 ;
        RECT  27.264 0 27.288 0.192 ;
    END
  END d[289]
  PIN d[28]
    DIRECTION INPUT ;
    USE SIGNAL ;
    PORT
      LAYER M3 ;
        RECT  8.496 0 8.514 0.144 ;
    END
  END d[28]
  PIN d[290]
    DIRECTION INPUT ;
    USE SIGNAL ;
    PORT
      LAYER M3 ;
        RECT  27.36 0 27.378 0.144 ;
    END
  END d[290]
  PIN d[291]
    DIRECTION INPUT ;
    USE SIGNAL ;
    PORT
      LAYER M5 ;
        RECT  27.408 0 27.432 0.192 ;
    END
  END d[291]
  PIN d[292]
    DIRECTION INPUT ;
    USE SIGNAL ;
    PORT
      LAYER M3 ;
        RECT  27.504 0 27.522 0.144 ;
    END
  END d[292]
  PIN d[293]
    DIRECTION INPUT ;
    USE SIGNAL ;
    PORT
      LAYER M5 ;
        RECT  27.552 0 27.576 0.192 ;
    END
  END d[293]
  PIN d[294]
    DIRECTION INPUT ;
    USE SIGNAL ;
    PORT
      LAYER M3 ;
        RECT  27.648 0 27.666 0.144 ;
    END
  END d[294]
  PIN d[295]
    DIRECTION INPUT ;
    USE SIGNAL ;
    PORT
      LAYER M5 ;
        RECT  27.696 0 27.72 0.192 ;
    END
  END d[295]
  PIN d[296]
    DIRECTION INPUT ;
    USE SIGNAL ;
    PORT
      LAYER M3 ;
        RECT  27.792 0 27.81 0.144 ;
    END
  END d[296]
  PIN d[297]
    DIRECTION INPUT ;
    USE SIGNAL ;
    PORT
      LAYER M5 ;
        RECT  27.84 0 27.864 0.192 ;
    END
  END d[297]
  PIN d[298]
    DIRECTION INPUT ;
    USE SIGNAL ;
    PORT
      LAYER M3 ;
        RECT  27.936 0 27.954 0.144 ;
    END
  END d[298]
  PIN d[299]
    DIRECTION INPUT ;
    USE SIGNAL ;
    PORT
      LAYER M5 ;
        RECT  27.984 0 28.008 0.192 ;
    END
  END d[299]
  PIN d[29]
    DIRECTION INPUT ;
    USE SIGNAL ;
    PORT
      LAYER M5 ;
        RECT  8.544 0 8.568 0.192 ;
    END
  END d[29]
  PIN d[2]
    DIRECTION INPUT ;
    USE SIGNAL ;
    PORT
      LAYER M3 ;
        RECT  6.624 0 6.642 0.144 ;
    END
  END d[2]
  PIN d[300]
    DIRECTION INPUT ;
    USE SIGNAL ;
    PORT
      LAYER M3 ;
        RECT  28.08 0 28.098 0.144 ;
    END
  END d[300]
  PIN d[301]
    DIRECTION INPUT ;
    USE SIGNAL ;
    PORT
      LAYER M5 ;
        RECT  28.128 0 28.152 0.192 ;
    END
  END d[301]
  PIN d[302]
    DIRECTION INPUT ;
    USE SIGNAL ;
    PORT
      LAYER M3 ;
        RECT  28.224 0 28.242 0.144 ;
    END
  END d[302]
  PIN d[303]
    DIRECTION INPUT ;
    USE SIGNAL ;
    PORT
      LAYER M5 ;
        RECT  28.272 0 28.296 0.192 ;
    END
  END d[303]
  PIN d[304]
    DIRECTION INPUT ;
    USE SIGNAL ;
    PORT
      LAYER M3 ;
        RECT  28.368 0 28.386 0.144 ;
    END
  END d[304]
  PIN d[305]
    DIRECTION INPUT ;
    USE SIGNAL ;
    PORT
      LAYER M5 ;
        RECT  28.416 0 28.44 0.192 ;
    END
  END d[305]
  PIN d[306]
    DIRECTION INPUT ;
    USE SIGNAL ;
    PORT
      LAYER M3 ;
        RECT  28.512 0 28.53 0.144 ;
    END
  END d[306]
  PIN d[307]
    DIRECTION INPUT ;
    USE SIGNAL ;
    PORT
      LAYER M5 ;
        RECT  28.56 0 28.584 0.192 ;
    END
  END d[307]
  PIN d[308]
    DIRECTION INPUT ;
    USE SIGNAL ;
    PORT
      LAYER M3 ;
        RECT  28.656 0 28.674 0.144 ;
    END
  END d[308]
  PIN d[309]
    DIRECTION INPUT ;
    USE SIGNAL ;
    PORT
      LAYER M5 ;
        RECT  28.704 0 28.728 0.192 ;
    END
  END d[309]
  PIN d[30]
    DIRECTION INPUT ;
    USE SIGNAL ;
    PORT
      LAYER M3 ;
        RECT  8.64 0 8.658 0.144 ;
    END
  END d[30]
  PIN d[310]
    DIRECTION INPUT ;
    USE SIGNAL ;
    PORT
      LAYER M3 ;
        RECT  28.8 0 28.818 0.144 ;
    END
  END d[310]
  PIN d[311]
    DIRECTION INPUT ;
    USE SIGNAL ;
    PORT
      LAYER M5 ;
        RECT  28.848 0 28.872 0.192 ;
    END
  END d[311]
  PIN d[312]
    DIRECTION INPUT ;
    USE SIGNAL ;
    PORT
      LAYER M3 ;
        RECT  28.944 0 28.962 0.144 ;
    END
  END d[312]
  PIN d[313]
    DIRECTION INPUT ;
    USE SIGNAL ;
    PORT
      LAYER M5 ;
        RECT  28.992 0 29.016 0.192 ;
    END
  END d[313]
  PIN d[314]
    DIRECTION INPUT ;
    USE SIGNAL ;
    PORT
      LAYER M3 ;
        RECT  29.088 0 29.106 0.144 ;
    END
  END d[314]
  PIN d[315]
    DIRECTION INPUT ;
    USE SIGNAL ;
    PORT
      LAYER M5 ;
        RECT  29.136 0 29.16 0.192 ;
    END
  END d[315]
  PIN d[316]
    DIRECTION INPUT ;
    USE SIGNAL ;
    PORT
      LAYER M3 ;
        RECT  29.232 0 29.25 0.144 ;
    END
  END d[316]
  PIN d[317]
    DIRECTION INPUT ;
    USE SIGNAL ;
    PORT
      LAYER M5 ;
        RECT  29.28 0 29.304 0.192 ;
    END
  END d[317]
  PIN d[318]
    DIRECTION INPUT ;
    USE SIGNAL ;
    PORT
      LAYER M3 ;
        RECT  29.376 0 29.394 0.144 ;
    END
  END d[318]
  PIN d[319]
    DIRECTION INPUT ;
    USE SIGNAL ;
    PORT
      LAYER M5 ;
        RECT  29.424 0 29.448 0.192 ;
    END
  END d[319]
  PIN d[31]
    DIRECTION INPUT ;
    USE SIGNAL ;
    PORT
      LAYER M5 ;
        RECT  8.688 0 8.712 0.192 ;
    END
  END d[31]
  PIN d[320]
    DIRECTION INPUT ;
    USE SIGNAL ;
    PORT
      LAYER M3 ;
        RECT  29.52 0 29.538 0.144 ;
    END
  END d[320]
  PIN d[321]
    DIRECTION INPUT ;
    USE SIGNAL ;
    PORT
      LAYER M5 ;
        RECT  29.568 0 29.592 0.192 ;
    END
  END d[321]
  PIN d[322]
    DIRECTION INPUT ;
    USE SIGNAL ;
    PORT
      LAYER M3 ;
        RECT  29.664 0 29.682 0.144 ;
    END
  END d[322]
  PIN d[323]
    DIRECTION INPUT ;
    USE SIGNAL ;
    PORT
      LAYER M5 ;
        RECT  29.712 0 29.736 0.192 ;
    END
  END d[323]
  PIN d[324]
    DIRECTION INPUT ;
    USE SIGNAL ;
    PORT
      LAYER M3 ;
        RECT  29.808 0 29.826 0.144 ;
    END
  END d[324]
  PIN d[325]
    DIRECTION INPUT ;
    USE SIGNAL ;
    PORT
      LAYER M5 ;
        RECT  29.856 0 29.88 0.192 ;
    END
  END d[325]
  PIN d[326]
    DIRECTION INPUT ;
    USE SIGNAL ;
    PORT
      LAYER M3 ;
        RECT  29.952 0 29.97 0.144 ;
    END
  END d[326]
  PIN d[327]
    DIRECTION INPUT ;
    USE SIGNAL ;
    PORT
      LAYER M5 ;
        RECT  30 0 30.024 0.192 ;
    END
  END d[327]
  PIN d[328]
    DIRECTION INPUT ;
    USE SIGNAL ;
    PORT
      LAYER M3 ;
        RECT  30.096 0 30.114 0.144 ;
    END
  END d[328]
  PIN d[329]
    DIRECTION INPUT ;
    USE SIGNAL ;
    PORT
      LAYER M5 ;
        RECT  30.144 0 30.168 0.192 ;
    END
  END d[329]
  PIN d[32]
    DIRECTION INPUT ;
    USE SIGNAL ;
    PORT
      LAYER M3 ;
        RECT  8.784 0 8.802 0.144 ;
    END
  END d[32]
  PIN d[330]
    DIRECTION INPUT ;
    USE SIGNAL ;
    PORT
      LAYER M3 ;
        RECT  30.24 0 30.258 0.144 ;
    END
  END d[330]
  PIN d[331]
    DIRECTION INPUT ;
    USE SIGNAL ;
    PORT
      LAYER M5 ;
        RECT  30.288 0 30.312 0.192 ;
    END
  END d[331]
  PIN d[332]
    DIRECTION INPUT ;
    USE SIGNAL ;
    PORT
      LAYER M3 ;
        RECT  30.384 0 30.402 0.144 ;
    END
  END d[332]
  PIN d[333]
    DIRECTION INPUT ;
    USE SIGNAL ;
    PORT
      LAYER M5 ;
        RECT  30.432 0 30.456 0.192 ;
    END
  END d[333]
  PIN d[334]
    DIRECTION INPUT ;
    USE SIGNAL ;
    PORT
      LAYER M3 ;
        RECT  30.528 0 30.546 0.144 ;
    END
  END d[334]
  PIN d[335]
    DIRECTION INPUT ;
    USE SIGNAL ;
    PORT
      LAYER M5 ;
        RECT  30.576 0 30.6 0.192 ;
    END
  END d[335]
  PIN d[336]
    DIRECTION INPUT ;
    USE SIGNAL ;
    PORT
      LAYER M3 ;
        RECT  30.672 0 30.69 0.144 ;
    END
  END d[336]
  PIN d[337]
    DIRECTION INPUT ;
    USE SIGNAL ;
    PORT
      LAYER M5 ;
        RECT  30.72 0 30.744 0.192 ;
    END
  END d[337]
  PIN d[338]
    DIRECTION INPUT ;
    USE SIGNAL ;
    PORT
      LAYER M3 ;
        RECT  30.816 0 30.834 0.144 ;
    END
  END d[338]
  PIN d[339]
    DIRECTION INPUT ;
    USE SIGNAL ;
    PORT
      LAYER M5 ;
        RECT  30.864 0 30.888 0.192 ;
    END
  END d[339]
  PIN d[33]
    DIRECTION INPUT ;
    USE SIGNAL ;
    PORT
      LAYER M5 ;
        RECT  8.832 0 8.856 0.192 ;
    END
  END d[33]
  PIN d[340]
    DIRECTION INPUT ;
    USE SIGNAL ;
    PORT
      LAYER M3 ;
        RECT  30.96 0 30.978 0.144 ;
    END
  END d[340]
  PIN d[341]
    DIRECTION INPUT ;
    USE SIGNAL ;
    PORT
      LAYER M5 ;
        RECT  31.008 0 31.032 0.192 ;
    END
  END d[341]
  PIN d[342]
    DIRECTION INPUT ;
    USE SIGNAL ;
    PORT
      LAYER M3 ;
        RECT  31.104 0 31.122 0.144 ;
    END
  END d[342]
  PIN d[343]
    DIRECTION INPUT ;
    USE SIGNAL ;
    PORT
      LAYER M5 ;
        RECT  31.152 0 31.176 0.192 ;
    END
  END d[343]
  PIN d[344]
    DIRECTION INPUT ;
    USE SIGNAL ;
    PORT
      LAYER M3 ;
        RECT  31.248 0 31.266 0.144 ;
    END
  END d[344]
  PIN d[345]
    DIRECTION INPUT ;
    USE SIGNAL ;
    PORT
      LAYER M5 ;
        RECT  31.296 0 31.32 0.192 ;
    END
  END d[345]
  PIN d[346]
    DIRECTION INPUT ;
    USE SIGNAL ;
    PORT
      LAYER M3 ;
        RECT  31.392 0 31.41 0.144 ;
    END
  END d[346]
  PIN d[347]
    DIRECTION INPUT ;
    USE SIGNAL ;
    PORT
      LAYER M5 ;
        RECT  31.44 0 31.464 0.192 ;
    END
  END d[347]
  PIN d[348]
    DIRECTION INPUT ;
    USE SIGNAL ;
    PORT
      LAYER M3 ;
        RECT  31.536 0 31.554 0.144 ;
    END
  END d[348]
  PIN d[349]
    DIRECTION INPUT ;
    USE SIGNAL ;
    PORT
      LAYER M5 ;
        RECT  31.584 0 31.608 0.192 ;
    END
  END d[349]
  PIN d[34]
    DIRECTION INPUT ;
    USE SIGNAL ;
    PORT
      LAYER M3 ;
        RECT  8.928 0 8.946 0.144 ;
    END
  END d[34]
  PIN d[350]
    DIRECTION INPUT ;
    USE SIGNAL ;
    PORT
      LAYER M3 ;
        RECT  31.68 0 31.698 0.144 ;
    END
  END d[350]
  PIN d[351]
    DIRECTION INPUT ;
    USE SIGNAL ;
    PORT
      LAYER M5 ;
        RECT  31.728 0 31.752 0.192 ;
    END
  END d[351]
  PIN d[352]
    DIRECTION INPUT ;
    USE SIGNAL ;
    PORT
      LAYER M3 ;
        RECT  31.824 0 31.842 0.144 ;
    END
  END d[352]
  PIN d[353]
    DIRECTION INPUT ;
    USE SIGNAL ;
    PORT
      LAYER M5 ;
        RECT  31.872 0 31.896 0.192 ;
    END
  END d[353]
  PIN d[354]
    DIRECTION INPUT ;
    USE SIGNAL ;
    PORT
      LAYER M3 ;
        RECT  31.968 0 31.986 0.144 ;
    END
  END d[354]
  PIN d[355]
    DIRECTION INPUT ;
    USE SIGNAL ;
    PORT
      LAYER M5 ;
        RECT  32.016 0 32.04 0.192 ;
    END
  END d[355]
  PIN d[356]
    DIRECTION INPUT ;
    USE SIGNAL ;
    PORT
      LAYER M3 ;
        RECT  32.112 0 32.13 0.144 ;
    END
  END d[356]
  PIN d[357]
    DIRECTION INPUT ;
    USE SIGNAL ;
    PORT
      LAYER M5 ;
        RECT  32.16 0 32.184 0.192 ;
    END
  END d[357]
  PIN d[358]
    DIRECTION INPUT ;
    USE SIGNAL ;
    PORT
      LAYER M3 ;
        RECT  32.256 0 32.274 0.144 ;
    END
  END d[358]
  PIN d[359]
    DIRECTION INPUT ;
    USE SIGNAL ;
    PORT
      LAYER M5 ;
        RECT  32.304 0 32.328 0.192 ;
    END
  END d[359]
  PIN d[35]
    DIRECTION INPUT ;
    USE SIGNAL ;
    PORT
      LAYER M5 ;
        RECT  8.976 0 9 0.192 ;
    END
  END d[35]
  PIN d[360]
    DIRECTION INPUT ;
    USE SIGNAL ;
    PORT
      LAYER M3 ;
        RECT  32.4 0 32.418 0.144 ;
    END
  END d[360]
  PIN d[361]
    DIRECTION INPUT ;
    USE SIGNAL ;
    PORT
      LAYER M5 ;
        RECT  32.448 0 32.472 0.192 ;
    END
  END d[361]
  PIN d[362]
    DIRECTION INPUT ;
    USE SIGNAL ;
    PORT
      LAYER M3 ;
        RECT  32.544 0 32.562 0.144 ;
    END
  END d[362]
  PIN d[363]
    DIRECTION INPUT ;
    USE SIGNAL ;
    PORT
      LAYER M5 ;
        RECT  32.592 0 32.616 0.192 ;
    END
  END d[363]
  PIN d[364]
    DIRECTION INPUT ;
    USE SIGNAL ;
    PORT
      LAYER M3 ;
        RECT  32.688 0 32.706 0.144 ;
    END
  END d[364]
  PIN d[365]
    DIRECTION INPUT ;
    USE SIGNAL ;
    PORT
      LAYER M5 ;
        RECT  32.736 0 32.76 0.192 ;
    END
  END d[365]
  PIN d[366]
    DIRECTION INPUT ;
    USE SIGNAL ;
    PORT
      LAYER M3 ;
        RECT  32.832 0 32.85 0.144 ;
    END
  END d[366]
  PIN d[367]
    DIRECTION INPUT ;
    USE SIGNAL ;
    PORT
      LAYER M5 ;
        RECT  32.88 0 32.904 0.192 ;
    END
  END d[367]
  PIN d[368]
    DIRECTION INPUT ;
    USE SIGNAL ;
    PORT
      LAYER M3 ;
        RECT  32.976 0 32.994 0.144 ;
    END
  END d[368]
  PIN d[369]
    DIRECTION INPUT ;
    USE SIGNAL ;
    PORT
      LAYER M5 ;
        RECT  33.024 0 33.048 0.192 ;
    END
  END d[369]
  PIN d[36]
    DIRECTION INPUT ;
    USE SIGNAL ;
    PORT
      LAYER M3 ;
        RECT  9.072 0 9.09 0.144 ;
    END
  END d[36]
  PIN d[370]
    DIRECTION INPUT ;
    USE SIGNAL ;
    PORT
      LAYER M3 ;
        RECT  33.12 0 33.138 0.144 ;
    END
  END d[370]
  PIN d[371]
    DIRECTION INPUT ;
    USE SIGNAL ;
    PORT
      LAYER M5 ;
        RECT  33.168 0 33.192 0.192 ;
    END
  END d[371]
  PIN d[372]
    DIRECTION INPUT ;
    USE SIGNAL ;
    PORT
      LAYER M3 ;
        RECT  33.264 0 33.282 0.144 ;
    END
  END d[372]
  PIN d[373]
    DIRECTION INPUT ;
    USE SIGNAL ;
    PORT
      LAYER M5 ;
        RECT  33.312 0 33.336 0.192 ;
    END
  END d[373]
  PIN d[374]
    DIRECTION INPUT ;
    USE SIGNAL ;
    PORT
      LAYER M3 ;
        RECT  33.408 0 33.426 0.144 ;
    END
  END d[374]
  PIN d[375]
    DIRECTION INPUT ;
    USE SIGNAL ;
    PORT
      LAYER M5 ;
        RECT  33.456 0 33.48 0.192 ;
    END
  END d[375]
  PIN d[376]
    DIRECTION INPUT ;
    USE SIGNAL ;
    PORT
      LAYER M3 ;
        RECT  33.552 0 33.57 0.144 ;
    END
  END d[376]
  PIN d[377]
    DIRECTION INPUT ;
    USE SIGNAL ;
    PORT
      LAYER M5 ;
        RECT  33.6 0 33.624 0.192 ;
    END
  END d[377]
  PIN d[378]
    DIRECTION INPUT ;
    USE SIGNAL ;
    PORT
      LAYER M3 ;
        RECT  33.696 0 33.714 0.144 ;
    END
  END d[378]
  PIN d[379]
    DIRECTION INPUT ;
    USE SIGNAL ;
    PORT
      LAYER M5 ;
        RECT  33.744 0 33.768 0.192 ;
    END
  END d[379]
  PIN d[37]
    DIRECTION INPUT ;
    USE SIGNAL ;
    PORT
      LAYER M5 ;
        RECT  9.12 0 9.144 0.192 ;
    END
  END d[37]
  PIN d[380]
    DIRECTION INPUT ;
    USE SIGNAL ;
    PORT
      LAYER M3 ;
        RECT  33.84 0 33.858 0.144 ;
    END
  END d[380]
  PIN d[381]
    DIRECTION INPUT ;
    USE SIGNAL ;
    PORT
      LAYER M5 ;
        RECT  33.888 0 33.912 0.192 ;
    END
  END d[381]
  PIN d[382]
    DIRECTION INPUT ;
    USE SIGNAL ;
    PORT
      LAYER M3 ;
        RECT  33.984 0 34.002 0.144 ;
    END
  END d[382]
  PIN d[383]
    DIRECTION INPUT ;
    USE SIGNAL ;
    PORT
      LAYER M5 ;
        RECT  34.032 0 34.056 0.192 ;
    END
  END d[383]
  PIN d[384]
    DIRECTION INPUT ;
    USE SIGNAL ;
    PORT
      LAYER M3 ;
        RECT  34.128 0 34.146 0.144 ;
    END
  END d[384]
  PIN d[385]
    DIRECTION INPUT ;
    USE SIGNAL ;
    PORT
      LAYER M5 ;
        RECT  34.176 0 34.2 0.192 ;
    END
  END d[385]
  PIN d[386]
    DIRECTION INPUT ;
    USE SIGNAL ;
    PORT
      LAYER M3 ;
        RECT  34.272 0 34.29 0.144 ;
    END
  END d[386]
  PIN d[387]
    DIRECTION INPUT ;
    USE SIGNAL ;
    PORT
      LAYER M5 ;
        RECT  34.32 0 34.344 0.192 ;
    END
  END d[387]
  PIN d[388]
    DIRECTION INPUT ;
    USE SIGNAL ;
    PORT
      LAYER M3 ;
        RECT  34.416 0 34.434 0.144 ;
    END
  END d[388]
  PIN d[389]
    DIRECTION INPUT ;
    USE SIGNAL ;
    PORT
      LAYER M5 ;
        RECT  34.464 0 34.488 0.192 ;
    END
  END d[389]
  PIN d[38]
    DIRECTION INPUT ;
    USE SIGNAL ;
    PORT
      LAYER M3 ;
        RECT  9.216 0 9.234 0.144 ;
    END
  END d[38]
  PIN d[390]
    DIRECTION INPUT ;
    USE SIGNAL ;
    PORT
      LAYER M3 ;
        RECT  34.56 0 34.578 0.144 ;
    END
  END d[390]
  PIN d[391]
    DIRECTION INPUT ;
    USE SIGNAL ;
    PORT
      LAYER M5 ;
        RECT  34.608 0 34.632 0.192 ;
    END
  END d[391]
  PIN d[392]
    DIRECTION INPUT ;
    USE SIGNAL ;
    PORT
      LAYER M3 ;
        RECT  34.704 0 34.722 0.144 ;
    END
  END d[392]
  PIN d[393]
    DIRECTION INPUT ;
    USE SIGNAL ;
    PORT
      LAYER M5 ;
        RECT  34.752 0 34.776 0.192 ;
    END
  END d[393]
  PIN d[394]
    DIRECTION INPUT ;
    USE SIGNAL ;
    PORT
      LAYER M3 ;
        RECT  34.848 0 34.866 0.144 ;
    END
  END d[394]
  PIN d[395]
    DIRECTION INPUT ;
    USE SIGNAL ;
    PORT
      LAYER M5 ;
        RECT  34.896 0 34.92 0.192 ;
    END
  END d[395]
  PIN d[396]
    DIRECTION INPUT ;
    USE SIGNAL ;
    PORT
      LAYER M3 ;
        RECT  34.992 0 35.01 0.144 ;
    END
  END d[396]
  PIN d[397]
    DIRECTION INPUT ;
    USE SIGNAL ;
    PORT
      LAYER M5 ;
        RECT  35.04 0 35.064 0.192 ;
    END
  END d[397]
  PIN d[398]
    DIRECTION INPUT ;
    USE SIGNAL ;
    PORT
      LAYER M3 ;
        RECT  35.136 0 35.154 0.144 ;
    END
  END d[398]
  PIN d[399]
    DIRECTION INPUT ;
    USE SIGNAL ;
    PORT
      LAYER M5 ;
        RECT  35.184 0 35.208 0.192 ;
    END
  END d[399]
  PIN d[39]
    DIRECTION INPUT ;
    USE SIGNAL ;
    PORT
      LAYER M5 ;
        RECT  9.264 0 9.288 0.192 ;
    END
  END d[39]
  PIN d[3]
    DIRECTION INPUT ;
    USE SIGNAL ;
    PORT
      LAYER M5 ;
        RECT  6.672 0 6.696 0.192 ;
    END
  END d[3]
  PIN d[400]
    DIRECTION INPUT ;
    USE SIGNAL ;
    PORT
      LAYER M3 ;
        RECT  35.28 0 35.298 0.144 ;
    END
  END d[400]
  PIN d[401]
    DIRECTION INPUT ;
    USE SIGNAL ;
    PORT
      LAYER M5 ;
        RECT  35.328 0 35.352 0.192 ;
    END
  END d[401]
  PIN d[402]
    DIRECTION INPUT ;
    USE SIGNAL ;
    PORT
      LAYER M3 ;
        RECT  35.424 0 35.442 0.144 ;
    END
  END d[402]
  PIN d[403]
    DIRECTION INPUT ;
    USE SIGNAL ;
    PORT
      LAYER M5 ;
        RECT  35.472 0 35.496 0.192 ;
    END
  END d[403]
  PIN d[404]
    DIRECTION INPUT ;
    USE SIGNAL ;
    PORT
      LAYER M3 ;
        RECT  35.568 0 35.586 0.144 ;
    END
  END d[404]
  PIN d[405]
    DIRECTION INPUT ;
    USE SIGNAL ;
    PORT
      LAYER M5 ;
        RECT  35.616 0 35.64 0.192 ;
    END
  END d[405]
  PIN d[406]
    DIRECTION INPUT ;
    USE SIGNAL ;
    PORT
      LAYER M3 ;
        RECT  35.712 0 35.73 0.144 ;
    END
  END d[406]
  PIN d[407]
    DIRECTION INPUT ;
    USE SIGNAL ;
    PORT
      LAYER M5 ;
        RECT  35.76 0 35.784 0.192 ;
    END
  END d[407]
  PIN d[408]
    DIRECTION INPUT ;
    USE SIGNAL ;
    PORT
      LAYER M3 ;
        RECT  35.856 0 35.874 0.144 ;
    END
  END d[408]
  PIN d[40]
    DIRECTION INPUT ;
    USE SIGNAL ;
    PORT
      LAYER M3 ;
        RECT  9.36 0 9.378 0.144 ;
    END
  END d[40]
  PIN d[41]
    DIRECTION INPUT ;
    USE SIGNAL ;
    PORT
      LAYER M5 ;
        RECT  9.408 0 9.432 0.192 ;
    END
  END d[41]
  PIN d[42]
    DIRECTION INPUT ;
    USE SIGNAL ;
    PORT
      LAYER M3 ;
        RECT  9.504 0 9.522 0.144 ;
    END
  END d[42]
  PIN d[43]
    DIRECTION INPUT ;
    USE SIGNAL ;
    PORT
      LAYER M5 ;
        RECT  9.552 0 9.576 0.192 ;
    END
  END d[43]
  PIN d[44]
    DIRECTION INPUT ;
    USE SIGNAL ;
    PORT
      LAYER M3 ;
        RECT  9.648 0 9.666 0.144 ;
    END
  END d[44]
  PIN d[45]
    DIRECTION INPUT ;
    USE SIGNAL ;
    PORT
      LAYER M5 ;
        RECT  9.696 0 9.72 0.192 ;
    END
  END d[45]
  PIN d[46]
    DIRECTION INPUT ;
    USE SIGNAL ;
    PORT
      LAYER M3 ;
        RECT  9.792 0 9.81 0.144 ;
    END
  END d[46]
  PIN d[47]
    DIRECTION INPUT ;
    USE SIGNAL ;
    PORT
      LAYER M5 ;
        RECT  9.84 0 9.864 0.192 ;
    END
  END d[47]
  PIN d[48]
    DIRECTION INPUT ;
    USE SIGNAL ;
    PORT
      LAYER M3 ;
        RECT  9.936 0 9.954 0.144 ;
    END
  END d[48]
  PIN d[49]
    DIRECTION INPUT ;
    USE SIGNAL ;
    PORT
      LAYER M5 ;
        RECT  9.984 0 10.008 0.192 ;
    END
  END d[49]
  PIN d[4]
    DIRECTION INPUT ;
    USE SIGNAL ;
    PORT
      LAYER M3 ;
        RECT  6.768 0 6.786 0.144 ;
    END
  END d[4]
  PIN d[50]
    DIRECTION INPUT ;
    USE SIGNAL ;
    PORT
      LAYER M3 ;
        RECT  10.08 0 10.098 0.144 ;
    END
  END d[50]
  PIN d[51]
    DIRECTION INPUT ;
    USE SIGNAL ;
    PORT
      LAYER M5 ;
        RECT  10.128 0 10.152 0.192 ;
    END
  END d[51]
  PIN d[52]
    DIRECTION INPUT ;
    USE SIGNAL ;
    PORT
      LAYER M3 ;
        RECT  10.224 0 10.242 0.144 ;
    END
  END d[52]
  PIN d[53]
    DIRECTION INPUT ;
    USE SIGNAL ;
    PORT
      LAYER M5 ;
        RECT  10.272 0 10.296 0.192 ;
    END
  END d[53]
  PIN d[54]
    DIRECTION INPUT ;
    USE SIGNAL ;
    PORT
      LAYER M3 ;
        RECT  10.368 0 10.386 0.144 ;
    END
  END d[54]
  PIN d[55]
    DIRECTION INPUT ;
    USE SIGNAL ;
    PORT
      LAYER M5 ;
        RECT  10.416 0 10.44 0.192 ;
    END
  END d[55]
  PIN d[56]
    DIRECTION INPUT ;
    USE SIGNAL ;
    PORT
      LAYER M3 ;
        RECT  10.512 0 10.53 0.144 ;
    END
  END d[56]
  PIN d[57]
    DIRECTION INPUT ;
    USE SIGNAL ;
    PORT
      LAYER M5 ;
        RECT  10.56 0 10.584 0.192 ;
    END
  END d[57]
  PIN d[58]
    DIRECTION INPUT ;
    USE SIGNAL ;
    PORT
      LAYER M3 ;
        RECT  10.656 0 10.674 0.144 ;
    END
  END d[58]
  PIN d[59]
    DIRECTION INPUT ;
    USE SIGNAL ;
    PORT
      LAYER M5 ;
        RECT  10.704 0 10.728 0.192 ;
    END
  END d[59]
  PIN d[5]
    DIRECTION INPUT ;
    USE SIGNAL ;
    PORT
      LAYER M5 ;
        RECT  6.816 0 6.84 0.192 ;
    END
  END d[5]
  PIN d[60]
    DIRECTION INPUT ;
    USE SIGNAL ;
    PORT
      LAYER M3 ;
        RECT  10.8 0 10.818 0.144 ;
    END
  END d[60]
  PIN d[61]
    DIRECTION INPUT ;
    USE SIGNAL ;
    PORT
      LAYER M5 ;
        RECT  10.848 0 10.872 0.192 ;
    END
  END d[61]
  PIN d[62]
    DIRECTION INPUT ;
    USE SIGNAL ;
    PORT
      LAYER M3 ;
        RECT  10.944 0 10.962 0.144 ;
    END
  END d[62]
  PIN d[63]
    DIRECTION INPUT ;
    USE SIGNAL ;
    PORT
      LAYER M5 ;
        RECT  10.992 0 11.016 0.192 ;
    END
  END d[63]
  PIN d[64]
    DIRECTION INPUT ;
    USE SIGNAL ;
    PORT
      LAYER M3 ;
        RECT  11.088 0 11.106 0.144 ;
    END
  END d[64]
  PIN d[65]
    DIRECTION INPUT ;
    USE SIGNAL ;
    PORT
      LAYER M5 ;
        RECT  11.136 0 11.16 0.192 ;
    END
  END d[65]
  PIN d[66]
    DIRECTION INPUT ;
    USE SIGNAL ;
    PORT
      LAYER M3 ;
        RECT  11.232 0 11.25 0.144 ;
    END
  END d[66]
  PIN d[67]
    DIRECTION INPUT ;
    USE SIGNAL ;
    PORT
      LAYER M5 ;
        RECT  11.28 0 11.304 0.192 ;
    END
  END d[67]
  PIN d[68]
    DIRECTION INPUT ;
    USE SIGNAL ;
    PORT
      LAYER M3 ;
        RECT  11.376 0 11.394 0.144 ;
    END
  END d[68]
  PIN d[69]
    DIRECTION INPUT ;
    USE SIGNAL ;
    PORT
      LAYER M5 ;
        RECT  11.424 0 11.448 0.192 ;
    END
  END d[69]
  PIN d[6]
    DIRECTION INPUT ;
    USE SIGNAL ;
    PORT
      LAYER M3 ;
        RECT  6.912 0 6.93 0.144 ;
    END
  END d[6]
  PIN d[70]
    DIRECTION INPUT ;
    USE SIGNAL ;
    PORT
      LAYER M3 ;
        RECT  11.52 0 11.538 0.144 ;
    END
  END d[70]
  PIN d[71]
    DIRECTION INPUT ;
    USE SIGNAL ;
    PORT
      LAYER M5 ;
        RECT  11.568 0 11.592 0.192 ;
    END
  END d[71]
  PIN d[72]
    DIRECTION INPUT ;
    USE SIGNAL ;
    PORT
      LAYER M3 ;
        RECT  11.664 0 11.682 0.144 ;
    END
  END d[72]
  PIN d[73]
    DIRECTION INPUT ;
    USE SIGNAL ;
    PORT
      LAYER M5 ;
        RECT  11.712 0 11.736 0.192 ;
    END
  END d[73]
  PIN d[74]
    DIRECTION INPUT ;
    USE SIGNAL ;
    PORT
      LAYER M3 ;
        RECT  11.808 0 11.826 0.144 ;
    END
  END d[74]
  PIN d[75]
    DIRECTION INPUT ;
    USE SIGNAL ;
    PORT
      LAYER M5 ;
        RECT  11.856 0 11.88 0.192 ;
    END
  END d[75]
  PIN d[76]
    DIRECTION INPUT ;
    USE SIGNAL ;
    PORT
      LAYER M3 ;
        RECT  11.952 0 11.97 0.144 ;
    END
  END d[76]
  PIN d[77]
    DIRECTION INPUT ;
    USE SIGNAL ;
    PORT
      LAYER M5 ;
        RECT  12 0 12.024 0.192 ;
    END
  END d[77]
  PIN d[78]
    DIRECTION INPUT ;
    USE SIGNAL ;
    PORT
      LAYER M3 ;
        RECT  12.096 0 12.114 0.144 ;
    END
  END d[78]
  PIN d[79]
    DIRECTION INPUT ;
    USE SIGNAL ;
    PORT
      LAYER M5 ;
        RECT  12.144 0 12.168 0.192 ;
    END
  END d[79]
  PIN d[7]
    DIRECTION INPUT ;
    USE SIGNAL ;
    PORT
      LAYER M5 ;
        RECT  6.96 0 6.984 0.192 ;
    END
  END d[7]
  PIN d[80]
    DIRECTION INPUT ;
    USE SIGNAL ;
    PORT
      LAYER M3 ;
        RECT  12.24 0 12.258 0.144 ;
    END
  END d[80]
  PIN d[81]
    DIRECTION INPUT ;
    USE SIGNAL ;
    PORT
      LAYER M5 ;
        RECT  12.288 0 12.312 0.192 ;
    END
  END d[81]
  PIN d[82]
    DIRECTION INPUT ;
    USE SIGNAL ;
    PORT
      LAYER M3 ;
        RECT  12.384 0 12.402 0.144 ;
    END
  END d[82]
  PIN d[83]
    DIRECTION INPUT ;
    USE SIGNAL ;
    PORT
      LAYER M5 ;
        RECT  12.432 0 12.456 0.192 ;
    END
  END d[83]
  PIN d[84]
    DIRECTION INPUT ;
    USE SIGNAL ;
    PORT
      LAYER M3 ;
        RECT  12.528 0 12.546 0.144 ;
    END
  END d[84]
  PIN d[85]
    DIRECTION INPUT ;
    USE SIGNAL ;
    PORT
      LAYER M5 ;
        RECT  12.576 0 12.6 0.192 ;
    END
  END d[85]
  PIN d[86]
    DIRECTION INPUT ;
    USE SIGNAL ;
    PORT
      LAYER M3 ;
        RECT  12.672 0 12.69 0.144 ;
    END
  END d[86]
  PIN d[87]
    DIRECTION INPUT ;
    USE SIGNAL ;
    PORT
      LAYER M5 ;
        RECT  12.72 0 12.744 0.192 ;
    END
  END d[87]
  PIN d[88]
    DIRECTION INPUT ;
    USE SIGNAL ;
    PORT
      LAYER M3 ;
        RECT  12.816 0 12.834 0.144 ;
    END
  END d[88]
  PIN d[89]
    DIRECTION INPUT ;
    USE SIGNAL ;
    PORT
      LAYER M5 ;
        RECT  12.864 0 12.888 0.192 ;
    END
  END d[89]
  PIN d[8]
    DIRECTION INPUT ;
    USE SIGNAL ;
    PORT
      LAYER M3 ;
        RECT  7.056 0 7.074 0.144 ;
    END
  END d[8]
  PIN d[90]
    DIRECTION INPUT ;
    USE SIGNAL ;
    PORT
      LAYER M3 ;
        RECT  12.96 0 12.978 0.144 ;
    END
  END d[90]
  PIN d[91]
    DIRECTION INPUT ;
    USE SIGNAL ;
    PORT
      LAYER M5 ;
        RECT  13.008 0 13.032 0.192 ;
    END
  END d[91]
  PIN d[92]
    DIRECTION INPUT ;
    USE SIGNAL ;
    PORT
      LAYER M3 ;
        RECT  13.104 0 13.122 0.144 ;
    END
  END d[92]
  PIN d[93]
    DIRECTION INPUT ;
    USE SIGNAL ;
    PORT
      LAYER M5 ;
        RECT  13.152 0 13.176 0.192 ;
    END
  END d[93]
  PIN d[94]
    DIRECTION INPUT ;
    USE SIGNAL ;
    PORT
      LAYER M3 ;
        RECT  13.248 0 13.266 0.144 ;
    END
  END d[94]
  PIN d[95]
    DIRECTION INPUT ;
    USE SIGNAL ;
    PORT
      LAYER M5 ;
        RECT  13.296 0 13.32 0.192 ;
    END
  END d[95]
  PIN d[96]
    DIRECTION INPUT ;
    USE SIGNAL ;
    PORT
      LAYER M3 ;
        RECT  13.392 0 13.41 0.144 ;
    END
  END d[96]
  PIN d[97]
    DIRECTION INPUT ;
    USE SIGNAL ;
    PORT
      LAYER M5 ;
        RECT  13.44 0 13.464 0.192 ;
    END
  END d[97]
  PIN d[98]
    DIRECTION INPUT ;
    USE SIGNAL ;
    PORT
      LAYER M3 ;
        RECT  13.536 0 13.554 0.144 ;
    END
  END d[98]
  PIN d[99]
    DIRECTION INPUT ;
    USE SIGNAL ;
    PORT
      LAYER M5 ;
        RECT  13.584 0 13.608 0.192 ;
    END
  END d[99]
  PIN d[9]
    DIRECTION INPUT ;
    USE SIGNAL ;
    PORT
      LAYER M5 ;
        RECT  7.104 0 7.128 0.192 ;
    END
  END d[9]
  PIN q[0]
    DIRECTION OUTPUT ;
    USE SIGNAL ;
    PORT
      LAYER M3 ;
        RECT  6.48 34.416 6.498 34.56 ;
    END
  END q[0]
  PIN q[100]
    DIRECTION OUTPUT ;
    USE SIGNAL ;
    PORT
      LAYER M3 ;
        RECT  13.68 34.416 13.698 34.56 ;
    END
  END q[100]
  PIN q[101]
    DIRECTION OUTPUT ;
    USE SIGNAL ;
    PORT
      LAYER M5 ;
        RECT  13.728 34.368 13.752 34.56 ;
    END
  END q[101]
  PIN q[102]
    DIRECTION OUTPUT ;
    USE SIGNAL ;
    PORT
      LAYER M3 ;
        RECT  13.824 34.416 13.842 34.56 ;
    END
  END q[102]
  PIN q[103]
    DIRECTION OUTPUT ;
    USE SIGNAL ;
    PORT
      LAYER M5 ;
        RECT  13.872 34.368 13.896 34.56 ;
    END
  END q[103]
  PIN q[104]
    DIRECTION OUTPUT ;
    USE SIGNAL ;
    PORT
      LAYER M3 ;
        RECT  13.968 34.416 13.986 34.56 ;
    END
  END q[104]
  PIN q[105]
    DIRECTION OUTPUT ;
    USE SIGNAL ;
    PORT
      LAYER M5 ;
        RECT  14.016 34.368 14.04 34.56 ;
    END
  END q[105]
  PIN q[106]
    DIRECTION OUTPUT ;
    USE SIGNAL ;
    PORT
      LAYER M3 ;
        RECT  14.112 34.416 14.13 34.56 ;
    END
  END q[106]
  PIN q[107]
    DIRECTION OUTPUT ;
    USE SIGNAL ;
    PORT
      LAYER M5 ;
        RECT  14.16 34.368 14.184 34.56 ;
    END
  END q[107]
  PIN q[108]
    DIRECTION OUTPUT ;
    USE SIGNAL ;
    PORT
      LAYER M3 ;
        RECT  14.256 34.416 14.274 34.56 ;
    END
  END q[108]
  PIN q[109]
    DIRECTION OUTPUT ;
    USE SIGNAL ;
    PORT
      LAYER M5 ;
        RECT  14.304 34.368 14.328 34.56 ;
    END
  END q[109]
  PIN q[10]
    DIRECTION OUTPUT ;
    USE SIGNAL ;
    PORT
      LAYER M3 ;
        RECT  7.2 34.416 7.218 34.56 ;
    END
  END q[10]
  PIN q[110]
    DIRECTION OUTPUT ;
    USE SIGNAL ;
    PORT
      LAYER M3 ;
        RECT  14.4 34.416 14.418 34.56 ;
    END
  END q[110]
  PIN q[111]
    DIRECTION OUTPUT ;
    USE SIGNAL ;
    PORT
      LAYER M5 ;
        RECT  14.448 34.368 14.472 34.56 ;
    END
  END q[111]
  PIN q[112]
    DIRECTION OUTPUT ;
    USE SIGNAL ;
    PORT
      LAYER M3 ;
        RECT  14.544 34.416 14.562 34.56 ;
    END
  END q[112]
  PIN q[113]
    DIRECTION OUTPUT ;
    USE SIGNAL ;
    PORT
      LAYER M5 ;
        RECT  14.592 34.368 14.616 34.56 ;
    END
  END q[113]
  PIN q[114]
    DIRECTION OUTPUT ;
    USE SIGNAL ;
    PORT
      LAYER M3 ;
        RECT  14.688 34.416 14.706 34.56 ;
    END
  END q[114]
  PIN q[115]
    DIRECTION OUTPUT ;
    USE SIGNAL ;
    PORT
      LAYER M5 ;
        RECT  14.736 34.368 14.76 34.56 ;
    END
  END q[115]
  PIN q[116]
    DIRECTION OUTPUT ;
    USE SIGNAL ;
    PORT
      LAYER M3 ;
        RECT  14.832 34.416 14.85 34.56 ;
    END
  END q[116]
  PIN q[117]
    DIRECTION OUTPUT ;
    USE SIGNAL ;
    PORT
      LAYER M5 ;
        RECT  14.88 34.368 14.904 34.56 ;
    END
  END q[117]
  PIN q[118]
    DIRECTION OUTPUT ;
    USE SIGNAL ;
    PORT
      LAYER M3 ;
        RECT  14.976 34.416 14.994 34.56 ;
    END
  END q[118]
  PIN q[119]
    DIRECTION OUTPUT ;
    USE SIGNAL ;
    PORT
      LAYER M5 ;
        RECT  15.024 34.368 15.048 34.56 ;
    END
  END q[119]
  PIN q[11]
    DIRECTION OUTPUT ;
    USE SIGNAL ;
    PORT
      LAYER M5 ;
        RECT  7.248 34.368 7.272 34.56 ;
    END
  END q[11]
  PIN q[120]
    DIRECTION OUTPUT ;
    USE SIGNAL ;
    PORT
      LAYER M3 ;
        RECT  15.12 34.416 15.138 34.56 ;
    END
  END q[120]
  PIN q[121]
    DIRECTION OUTPUT ;
    USE SIGNAL ;
    PORT
      LAYER M5 ;
        RECT  15.168 34.368 15.192 34.56 ;
    END
  END q[121]
  PIN q[122]
    DIRECTION OUTPUT ;
    USE SIGNAL ;
    PORT
      LAYER M3 ;
        RECT  15.264 34.416 15.282 34.56 ;
    END
  END q[122]
  PIN q[123]
    DIRECTION OUTPUT ;
    USE SIGNAL ;
    PORT
      LAYER M5 ;
        RECT  15.312 34.368 15.336 34.56 ;
    END
  END q[123]
  PIN q[124]
    DIRECTION OUTPUT ;
    USE SIGNAL ;
    PORT
      LAYER M3 ;
        RECT  15.408 34.416 15.426 34.56 ;
    END
  END q[124]
  PIN q[125]
    DIRECTION OUTPUT ;
    USE SIGNAL ;
    PORT
      LAYER M5 ;
        RECT  15.456 34.368 15.48 34.56 ;
    END
  END q[125]
  PIN q[126]
    DIRECTION OUTPUT ;
    USE SIGNAL ;
    PORT
      LAYER M3 ;
        RECT  15.552 34.416 15.57 34.56 ;
    END
  END q[126]
  PIN q[127]
    DIRECTION OUTPUT ;
    USE SIGNAL ;
    PORT
      LAYER M5 ;
        RECT  15.6 34.368 15.624 34.56 ;
    END
  END q[127]
  PIN q[128]
    DIRECTION OUTPUT ;
    USE SIGNAL ;
    PORT
      LAYER M3 ;
        RECT  15.696 34.416 15.714 34.56 ;
    END
  END q[128]
  PIN q[129]
    DIRECTION OUTPUT ;
    USE SIGNAL ;
    PORT
      LAYER M5 ;
        RECT  15.744 34.368 15.768 34.56 ;
    END
  END q[129]
  PIN q[12]
    DIRECTION OUTPUT ;
    USE SIGNAL ;
    PORT
      LAYER M3 ;
        RECT  7.344 34.416 7.362 34.56 ;
    END
  END q[12]
  PIN q[130]
    DIRECTION OUTPUT ;
    USE SIGNAL ;
    PORT
      LAYER M3 ;
        RECT  15.84 34.416 15.858 34.56 ;
    END
  END q[130]
  PIN q[131]
    DIRECTION OUTPUT ;
    USE SIGNAL ;
    PORT
      LAYER M5 ;
        RECT  15.888 34.368 15.912 34.56 ;
    END
  END q[131]
  PIN q[132]
    DIRECTION OUTPUT ;
    USE SIGNAL ;
    PORT
      LAYER M3 ;
        RECT  15.984 34.416 16.002 34.56 ;
    END
  END q[132]
  PIN q[133]
    DIRECTION OUTPUT ;
    USE SIGNAL ;
    PORT
      LAYER M5 ;
        RECT  16.032 34.368 16.056 34.56 ;
    END
  END q[133]
  PIN q[134]
    DIRECTION OUTPUT ;
    USE SIGNAL ;
    PORT
      LAYER M3 ;
        RECT  16.128 34.416 16.146 34.56 ;
    END
  END q[134]
  PIN q[135]
    DIRECTION OUTPUT ;
    USE SIGNAL ;
    PORT
      LAYER M5 ;
        RECT  16.176 34.368 16.2 34.56 ;
    END
  END q[135]
  PIN q[136]
    DIRECTION OUTPUT ;
    USE SIGNAL ;
    PORT
      LAYER M3 ;
        RECT  16.272 34.416 16.29 34.56 ;
    END
  END q[136]
  PIN q[137]
    DIRECTION OUTPUT ;
    USE SIGNAL ;
    PORT
      LAYER M5 ;
        RECT  16.32 34.368 16.344 34.56 ;
    END
  END q[137]
  PIN q[138]
    DIRECTION OUTPUT ;
    USE SIGNAL ;
    PORT
      LAYER M3 ;
        RECT  16.416 34.416 16.434 34.56 ;
    END
  END q[138]
  PIN q[139]
    DIRECTION OUTPUT ;
    USE SIGNAL ;
    PORT
      LAYER M5 ;
        RECT  16.464 34.368 16.488 34.56 ;
    END
  END q[139]
  PIN q[13]
    DIRECTION OUTPUT ;
    USE SIGNAL ;
    PORT
      LAYER M5 ;
        RECT  7.392 34.368 7.416 34.56 ;
    END
  END q[13]
  PIN q[140]
    DIRECTION OUTPUT ;
    USE SIGNAL ;
    PORT
      LAYER M3 ;
        RECT  16.56 34.416 16.578 34.56 ;
    END
  END q[140]
  PIN q[141]
    DIRECTION OUTPUT ;
    USE SIGNAL ;
    PORT
      LAYER M5 ;
        RECT  16.608 34.368 16.632 34.56 ;
    END
  END q[141]
  PIN q[142]
    DIRECTION OUTPUT ;
    USE SIGNAL ;
    PORT
      LAYER M3 ;
        RECT  16.704 34.416 16.722 34.56 ;
    END
  END q[142]
  PIN q[143]
    DIRECTION OUTPUT ;
    USE SIGNAL ;
    PORT
      LAYER M5 ;
        RECT  16.752 34.368 16.776 34.56 ;
    END
  END q[143]
  PIN q[144]
    DIRECTION OUTPUT ;
    USE SIGNAL ;
    PORT
      LAYER M3 ;
        RECT  16.848 34.416 16.866 34.56 ;
    END
  END q[144]
  PIN q[145]
    DIRECTION OUTPUT ;
    USE SIGNAL ;
    PORT
      LAYER M5 ;
        RECT  16.896 34.368 16.92 34.56 ;
    END
  END q[145]
  PIN q[146]
    DIRECTION OUTPUT ;
    USE SIGNAL ;
    PORT
      LAYER M3 ;
        RECT  16.992 34.416 17.01 34.56 ;
    END
  END q[146]
  PIN q[147]
    DIRECTION OUTPUT ;
    USE SIGNAL ;
    PORT
      LAYER M5 ;
        RECT  17.04 34.368 17.064 34.56 ;
    END
  END q[147]
  PIN q[148]
    DIRECTION OUTPUT ;
    USE SIGNAL ;
    PORT
      LAYER M3 ;
        RECT  17.136 34.416 17.154 34.56 ;
    END
  END q[148]
  PIN q[149]
    DIRECTION OUTPUT ;
    USE SIGNAL ;
    PORT
      LAYER M5 ;
        RECT  17.184 34.368 17.208 34.56 ;
    END
  END q[149]
  PIN q[14]
    DIRECTION OUTPUT ;
    USE SIGNAL ;
    PORT
      LAYER M3 ;
        RECT  7.488 34.416 7.506 34.56 ;
    END
  END q[14]
  PIN q[150]
    DIRECTION OUTPUT ;
    USE SIGNAL ;
    PORT
      LAYER M3 ;
        RECT  17.28 34.416 17.298 34.56 ;
    END
  END q[150]
  PIN q[151]
    DIRECTION OUTPUT ;
    USE SIGNAL ;
    PORT
      LAYER M5 ;
        RECT  17.328 34.368 17.352 34.56 ;
    END
  END q[151]
  PIN q[152]
    DIRECTION OUTPUT ;
    USE SIGNAL ;
    PORT
      LAYER M3 ;
        RECT  17.424 34.416 17.442 34.56 ;
    END
  END q[152]
  PIN q[153]
    DIRECTION OUTPUT ;
    USE SIGNAL ;
    PORT
      LAYER M5 ;
        RECT  17.472 34.368 17.496 34.56 ;
    END
  END q[153]
  PIN q[154]
    DIRECTION OUTPUT ;
    USE SIGNAL ;
    PORT
      LAYER M3 ;
        RECT  17.568 34.416 17.586 34.56 ;
    END
  END q[154]
  PIN q[155]
    DIRECTION OUTPUT ;
    USE SIGNAL ;
    PORT
      LAYER M5 ;
        RECT  17.616 34.368 17.64 34.56 ;
    END
  END q[155]
  PIN q[156]
    DIRECTION OUTPUT ;
    USE SIGNAL ;
    PORT
      LAYER M3 ;
        RECT  17.712 34.416 17.73 34.56 ;
    END
  END q[156]
  PIN q[157]
    DIRECTION OUTPUT ;
    USE SIGNAL ;
    PORT
      LAYER M5 ;
        RECT  17.76 34.368 17.784 34.56 ;
    END
  END q[157]
  PIN q[158]
    DIRECTION OUTPUT ;
    USE SIGNAL ;
    PORT
      LAYER M3 ;
        RECT  17.856 34.416 17.874 34.56 ;
    END
  END q[158]
  PIN q[159]
    DIRECTION OUTPUT ;
    USE SIGNAL ;
    PORT
      LAYER M5 ;
        RECT  17.904 34.368 17.928 34.56 ;
    END
  END q[159]
  PIN q[15]
    DIRECTION OUTPUT ;
    USE SIGNAL ;
    PORT
      LAYER M5 ;
        RECT  7.536 34.368 7.56 34.56 ;
    END
  END q[15]
  PIN q[160]
    DIRECTION OUTPUT ;
    USE SIGNAL ;
    PORT
      LAYER M3 ;
        RECT  18 34.416 18.018 34.56 ;
    END
  END q[160]
  PIN q[161]
    DIRECTION OUTPUT ;
    USE SIGNAL ;
    PORT
      LAYER M5 ;
        RECT  18.048 34.368 18.072 34.56 ;
    END
  END q[161]
  PIN q[162]
    DIRECTION OUTPUT ;
    USE SIGNAL ;
    PORT
      LAYER M3 ;
        RECT  18.144 34.416 18.162 34.56 ;
    END
  END q[162]
  PIN q[163]
    DIRECTION OUTPUT ;
    USE SIGNAL ;
    PORT
      LAYER M5 ;
        RECT  18.192 34.368 18.216 34.56 ;
    END
  END q[163]
  PIN q[164]
    DIRECTION OUTPUT ;
    USE SIGNAL ;
    PORT
      LAYER M3 ;
        RECT  18.288 34.416 18.306 34.56 ;
    END
  END q[164]
  PIN q[165]
    DIRECTION OUTPUT ;
    USE SIGNAL ;
    PORT
      LAYER M5 ;
        RECT  18.336 34.368 18.36 34.56 ;
    END
  END q[165]
  PIN q[166]
    DIRECTION OUTPUT ;
    USE SIGNAL ;
    PORT
      LAYER M3 ;
        RECT  18.432 34.416 18.45 34.56 ;
    END
  END q[166]
  PIN q[167]
    DIRECTION OUTPUT ;
    USE SIGNAL ;
    PORT
      LAYER M5 ;
        RECT  18.48 34.368 18.504 34.56 ;
    END
  END q[167]
  PIN q[168]
    DIRECTION OUTPUT ;
    USE SIGNAL ;
    PORT
      LAYER M3 ;
        RECT  18.576 34.416 18.594 34.56 ;
    END
  END q[168]
  PIN q[169]
    DIRECTION OUTPUT ;
    USE SIGNAL ;
    PORT
      LAYER M5 ;
        RECT  18.624 34.368 18.648 34.56 ;
    END
  END q[169]
  PIN q[16]
    DIRECTION OUTPUT ;
    USE SIGNAL ;
    PORT
      LAYER M3 ;
        RECT  7.632 34.416 7.65 34.56 ;
    END
  END q[16]
  PIN q[170]
    DIRECTION OUTPUT ;
    USE SIGNAL ;
    PORT
      LAYER M3 ;
        RECT  18.72 34.416 18.738 34.56 ;
    END
  END q[170]
  PIN q[171]
    DIRECTION OUTPUT ;
    USE SIGNAL ;
    PORT
      LAYER M5 ;
        RECT  18.768 34.368 18.792 34.56 ;
    END
  END q[171]
  PIN q[172]
    DIRECTION OUTPUT ;
    USE SIGNAL ;
    PORT
      LAYER M3 ;
        RECT  18.864 34.416 18.882 34.56 ;
    END
  END q[172]
  PIN q[173]
    DIRECTION OUTPUT ;
    USE SIGNAL ;
    PORT
      LAYER M5 ;
        RECT  18.912 34.368 18.936 34.56 ;
    END
  END q[173]
  PIN q[174]
    DIRECTION OUTPUT ;
    USE SIGNAL ;
    PORT
      LAYER M3 ;
        RECT  19.008 34.416 19.026 34.56 ;
    END
  END q[174]
  PIN q[175]
    DIRECTION OUTPUT ;
    USE SIGNAL ;
    PORT
      LAYER M5 ;
        RECT  19.056 34.368 19.08 34.56 ;
    END
  END q[175]
  PIN q[176]
    DIRECTION OUTPUT ;
    USE SIGNAL ;
    PORT
      LAYER M3 ;
        RECT  19.152 34.416 19.17 34.56 ;
    END
  END q[176]
  PIN q[177]
    DIRECTION OUTPUT ;
    USE SIGNAL ;
    PORT
      LAYER M5 ;
        RECT  19.2 34.368 19.224 34.56 ;
    END
  END q[177]
  PIN q[178]
    DIRECTION OUTPUT ;
    USE SIGNAL ;
    PORT
      LAYER M3 ;
        RECT  19.296 34.416 19.314 34.56 ;
    END
  END q[178]
  PIN q[179]
    DIRECTION OUTPUT ;
    USE SIGNAL ;
    PORT
      LAYER M5 ;
        RECT  19.344 34.368 19.368 34.56 ;
    END
  END q[179]
  PIN q[17]
    DIRECTION OUTPUT ;
    USE SIGNAL ;
    PORT
      LAYER M5 ;
        RECT  7.68 34.368 7.704 34.56 ;
    END
  END q[17]
  PIN q[180]
    DIRECTION OUTPUT ;
    USE SIGNAL ;
    PORT
      LAYER M3 ;
        RECT  19.44 34.416 19.458 34.56 ;
    END
  END q[180]
  PIN q[181]
    DIRECTION OUTPUT ;
    USE SIGNAL ;
    PORT
      LAYER M5 ;
        RECT  19.488 34.368 19.512 34.56 ;
    END
  END q[181]
  PIN q[182]
    DIRECTION OUTPUT ;
    USE SIGNAL ;
    PORT
      LAYER M3 ;
        RECT  19.584 34.416 19.602 34.56 ;
    END
  END q[182]
  PIN q[183]
    DIRECTION OUTPUT ;
    USE SIGNAL ;
    PORT
      LAYER M5 ;
        RECT  19.632 34.368 19.656 34.56 ;
    END
  END q[183]
  PIN q[184]
    DIRECTION OUTPUT ;
    USE SIGNAL ;
    PORT
      LAYER M3 ;
        RECT  19.728 34.416 19.746 34.56 ;
    END
  END q[184]
  PIN q[185]
    DIRECTION OUTPUT ;
    USE SIGNAL ;
    PORT
      LAYER M5 ;
        RECT  19.776 34.368 19.8 34.56 ;
    END
  END q[185]
  PIN q[186]
    DIRECTION OUTPUT ;
    USE SIGNAL ;
    PORT
      LAYER M3 ;
        RECT  19.872 34.416 19.89 34.56 ;
    END
  END q[186]
  PIN q[187]
    DIRECTION OUTPUT ;
    USE SIGNAL ;
    PORT
      LAYER M5 ;
        RECT  19.92 34.368 19.944 34.56 ;
    END
  END q[187]
  PIN q[188]
    DIRECTION OUTPUT ;
    USE SIGNAL ;
    PORT
      LAYER M3 ;
        RECT  20.016 34.416 20.034 34.56 ;
    END
  END q[188]
  PIN q[189]
    DIRECTION OUTPUT ;
    USE SIGNAL ;
    PORT
      LAYER M5 ;
        RECT  20.064 34.368 20.088 34.56 ;
    END
  END q[189]
  PIN q[18]
    DIRECTION OUTPUT ;
    USE SIGNAL ;
    PORT
      LAYER M3 ;
        RECT  7.776 34.416 7.794 34.56 ;
    END
  END q[18]
  PIN q[190]
    DIRECTION OUTPUT ;
    USE SIGNAL ;
    PORT
      LAYER M3 ;
        RECT  20.16 34.416 20.178 34.56 ;
    END
  END q[190]
  PIN q[191]
    DIRECTION OUTPUT ;
    USE SIGNAL ;
    PORT
      LAYER M5 ;
        RECT  20.208 34.368 20.232 34.56 ;
    END
  END q[191]
  PIN q[192]
    DIRECTION OUTPUT ;
    USE SIGNAL ;
    PORT
      LAYER M3 ;
        RECT  20.304 34.416 20.322 34.56 ;
    END
  END q[192]
  PIN q[193]
    DIRECTION OUTPUT ;
    USE SIGNAL ;
    PORT
      LAYER M5 ;
        RECT  20.352 34.368 20.376 34.56 ;
    END
  END q[193]
  PIN q[194]
    DIRECTION OUTPUT ;
    USE SIGNAL ;
    PORT
      LAYER M3 ;
        RECT  20.448 34.416 20.466 34.56 ;
    END
  END q[194]
  PIN q[195]
    DIRECTION OUTPUT ;
    USE SIGNAL ;
    PORT
      LAYER M5 ;
        RECT  20.496 34.368 20.52 34.56 ;
    END
  END q[195]
  PIN q[196]
    DIRECTION OUTPUT ;
    USE SIGNAL ;
    PORT
      LAYER M3 ;
        RECT  20.592 34.416 20.61 34.56 ;
    END
  END q[196]
  PIN q[197]
    DIRECTION OUTPUT ;
    USE SIGNAL ;
    PORT
      LAYER M5 ;
        RECT  20.64 34.368 20.664 34.56 ;
    END
  END q[197]
  PIN q[198]
    DIRECTION OUTPUT ;
    USE SIGNAL ;
    PORT
      LAYER M3 ;
        RECT  20.736 34.416 20.754 34.56 ;
    END
  END q[198]
  PIN q[199]
    DIRECTION OUTPUT ;
    USE SIGNAL ;
    PORT
      LAYER M5 ;
        RECT  20.784 34.368 20.808 34.56 ;
    END
  END q[199]
  PIN q[19]
    DIRECTION OUTPUT ;
    USE SIGNAL ;
    PORT
      LAYER M5 ;
        RECT  7.824 34.368 7.848 34.56 ;
    END
  END q[19]
  PIN q[1]
    DIRECTION OUTPUT ;
    USE SIGNAL ;
    PORT
      LAYER M5 ;
        RECT  6.528 34.368 6.552 34.56 ;
    END
  END q[1]
  PIN q[200]
    DIRECTION OUTPUT ;
    USE SIGNAL ;
    PORT
      LAYER M3 ;
        RECT  20.88 34.416 20.898 34.56 ;
    END
  END q[200]
  PIN q[201]
    DIRECTION OUTPUT ;
    USE SIGNAL ;
    PORT
      LAYER M5 ;
        RECT  20.928 34.368 20.952 34.56 ;
    END
  END q[201]
  PIN q[202]
    DIRECTION OUTPUT ;
    USE SIGNAL ;
    PORT
      LAYER M3 ;
        RECT  21.024 34.416 21.042 34.56 ;
    END
  END q[202]
  PIN q[203]
    DIRECTION OUTPUT ;
    USE SIGNAL ;
    PORT
      LAYER M5 ;
        RECT  21.072 34.368 21.096 34.56 ;
    END
  END q[203]
  PIN q[204]
    DIRECTION OUTPUT ;
    USE SIGNAL ;
    PORT
      LAYER M3 ;
        RECT  21.168 34.416 21.186 34.56 ;
    END
  END q[204]
  PIN q[205]
    DIRECTION OUTPUT ;
    USE SIGNAL ;
    PORT
      LAYER M5 ;
        RECT  21.216 34.368 21.24 34.56 ;
    END
  END q[205]
  PIN q[206]
    DIRECTION OUTPUT ;
    USE SIGNAL ;
    PORT
      LAYER M3 ;
        RECT  21.312 34.416 21.33 34.56 ;
    END
  END q[206]
  PIN q[207]
    DIRECTION OUTPUT ;
    USE SIGNAL ;
    PORT
      LAYER M5 ;
        RECT  21.36 34.368 21.384 34.56 ;
    END
  END q[207]
  PIN q[208]
    DIRECTION OUTPUT ;
    USE SIGNAL ;
    PORT
      LAYER M3 ;
        RECT  21.456 34.416 21.474 34.56 ;
    END
  END q[208]
  PIN q[209]
    DIRECTION OUTPUT ;
    USE SIGNAL ;
    PORT
      LAYER M5 ;
        RECT  21.504 34.368 21.528 34.56 ;
    END
  END q[209]
  PIN q[20]
    DIRECTION OUTPUT ;
    USE SIGNAL ;
    PORT
      LAYER M3 ;
        RECT  7.92 34.416 7.938 34.56 ;
    END
  END q[20]
  PIN q[210]
    DIRECTION OUTPUT ;
    USE SIGNAL ;
    PORT
      LAYER M3 ;
        RECT  21.6 34.416 21.618 34.56 ;
    END
  END q[210]
  PIN q[211]
    DIRECTION OUTPUT ;
    USE SIGNAL ;
    PORT
      LAYER M5 ;
        RECT  21.648 34.368 21.672 34.56 ;
    END
  END q[211]
  PIN q[212]
    DIRECTION OUTPUT ;
    USE SIGNAL ;
    PORT
      LAYER M3 ;
        RECT  21.744 34.416 21.762 34.56 ;
    END
  END q[212]
  PIN q[213]
    DIRECTION OUTPUT ;
    USE SIGNAL ;
    PORT
      LAYER M5 ;
        RECT  21.792 34.368 21.816 34.56 ;
    END
  END q[213]
  PIN q[214]
    DIRECTION OUTPUT ;
    USE SIGNAL ;
    PORT
      LAYER M3 ;
        RECT  21.888 34.416 21.906 34.56 ;
    END
  END q[214]
  PIN q[215]
    DIRECTION OUTPUT ;
    USE SIGNAL ;
    PORT
      LAYER M5 ;
        RECT  21.936 34.368 21.96 34.56 ;
    END
  END q[215]
  PIN q[216]
    DIRECTION OUTPUT ;
    USE SIGNAL ;
    PORT
      LAYER M3 ;
        RECT  22.032 34.416 22.05 34.56 ;
    END
  END q[216]
  PIN q[217]
    DIRECTION OUTPUT ;
    USE SIGNAL ;
    PORT
      LAYER M5 ;
        RECT  22.08 34.368 22.104 34.56 ;
    END
  END q[217]
  PIN q[218]
    DIRECTION OUTPUT ;
    USE SIGNAL ;
    PORT
      LAYER M3 ;
        RECT  22.176 34.416 22.194 34.56 ;
    END
  END q[218]
  PIN q[219]
    DIRECTION OUTPUT ;
    USE SIGNAL ;
    PORT
      LAYER M5 ;
        RECT  22.224 34.368 22.248 34.56 ;
    END
  END q[219]
  PIN q[21]
    DIRECTION OUTPUT ;
    USE SIGNAL ;
    PORT
      LAYER M5 ;
        RECT  7.968 34.368 7.992 34.56 ;
    END
  END q[21]
  PIN q[220]
    DIRECTION OUTPUT ;
    USE SIGNAL ;
    PORT
      LAYER M3 ;
        RECT  22.32 34.416 22.338 34.56 ;
    END
  END q[220]
  PIN q[221]
    DIRECTION OUTPUT ;
    USE SIGNAL ;
    PORT
      LAYER M5 ;
        RECT  22.368 34.368 22.392 34.56 ;
    END
  END q[221]
  PIN q[222]
    DIRECTION OUTPUT ;
    USE SIGNAL ;
    PORT
      LAYER M3 ;
        RECT  22.464 34.416 22.482 34.56 ;
    END
  END q[222]
  PIN q[223]
    DIRECTION OUTPUT ;
    USE SIGNAL ;
    PORT
      LAYER M5 ;
        RECT  22.512 34.368 22.536 34.56 ;
    END
  END q[223]
  PIN q[224]
    DIRECTION OUTPUT ;
    USE SIGNAL ;
    PORT
      LAYER M3 ;
        RECT  22.608 34.416 22.626 34.56 ;
    END
  END q[224]
  PIN q[225]
    DIRECTION OUTPUT ;
    USE SIGNAL ;
    PORT
      LAYER M5 ;
        RECT  22.656 34.368 22.68 34.56 ;
    END
  END q[225]
  PIN q[226]
    DIRECTION OUTPUT ;
    USE SIGNAL ;
    PORT
      LAYER M3 ;
        RECT  22.752 34.416 22.77 34.56 ;
    END
  END q[226]
  PIN q[227]
    DIRECTION OUTPUT ;
    USE SIGNAL ;
    PORT
      LAYER M5 ;
        RECT  22.8 34.368 22.824 34.56 ;
    END
  END q[227]
  PIN q[228]
    DIRECTION OUTPUT ;
    USE SIGNAL ;
    PORT
      LAYER M3 ;
        RECT  22.896 34.416 22.914 34.56 ;
    END
  END q[228]
  PIN q[229]
    DIRECTION OUTPUT ;
    USE SIGNAL ;
    PORT
      LAYER M5 ;
        RECT  22.944 34.368 22.968 34.56 ;
    END
  END q[229]
  PIN q[22]
    DIRECTION OUTPUT ;
    USE SIGNAL ;
    PORT
      LAYER M3 ;
        RECT  8.064 34.416 8.082 34.56 ;
    END
  END q[22]
  PIN q[230]
    DIRECTION OUTPUT ;
    USE SIGNAL ;
    PORT
      LAYER M3 ;
        RECT  23.04 34.416 23.058 34.56 ;
    END
  END q[230]
  PIN q[231]
    DIRECTION OUTPUT ;
    USE SIGNAL ;
    PORT
      LAYER M5 ;
        RECT  23.088 34.368 23.112 34.56 ;
    END
  END q[231]
  PIN q[232]
    DIRECTION OUTPUT ;
    USE SIGNAL ;
    PORT
      LAYER M3 ;
        RECT  23.184 34.416 23.202 34.56 ;
    END
  END q[232]
  PIN q[233]
    DIRECTION OUTPUT ;
    USE SIGNAL ;
    PORT
      LAYER M5 ;
        RECT  23.232 34.368 23.256 34.56 ;
    END
  END q[233]
  PIN q[234]
    DIRECTION OUTPUT ;
    USE SIGNAL ;
    PORT
      LAYER M3 ;
        RECT  23.328 34.416 23.346 34.56 ;
    END
  END q[234]
  PIN q[235]
    DIRECTION OUTPUT ;
    USE SIGNAL ;
    PORT
      LAYER M5 ;
        RECT  23.376 34.368 23.4 34.56 ;
    END
  END q[235]
  PIN q[236]
    DIRECTION OUTPUT ;
    USE SIGNAL ;
    PORT
      LAYER M3 ;
        RECT  23.472 34.416 23.49 34.56 ;
    END
  END q[236]
  PIN q[237]
    DIRECTION OUTPUT ;
    USE SIGNAL ;
    PORT
      LAYER M5 ;
        RECT  23.52 34.368 23.544 34.56 ;
    END
  END q[237]
  PIN q[238]
    DIRECTION OUTPUT ;
    USE SIGNAL ;
    PORT
      LAYER M3 ;
        RECT  23.616 34.416 23.634 34.56 ;
    END
  END q[238]
  PIN q[239]
    DIRECTION OUTPUT ;
    USE SIGNAL ;
    PORT
      LAYER M5 ;
        RECT  23.664 34.368 23.688 34.56 ;
    END
  END q[239]
  PIN q[23]
    DIRECTION OUTPUT ;
    USE SIGNAL ;
    PORT
      LAYER M5 ;
        RECT  8.112 34.368 8.136 34.56 ;
    END
  END q[23]
  PIN q[240]
    DIRECTION OUTPUT ;
    USE SIGNAL ;
    PORT
      LAYER M3 ;
        RECT  23.76 34.416 23.778 34.56 ;
    END
  END q[240]
  PIN q[241]
    DIRECTION OUTPUT ;
    USE SIGNAL ;
    PORT
      LAYER M5 ;
        RECT  23.808 34.368 23.832 34.56 ;
    END
  END q[241]
  PIN q[242]
    DIRECTION OUTPUT ;
    USE SIGNAL ;
    PORT
      LAYER M3 ;
        RECT  23.904 34.416 23.922 34.56 ;
    END
  END q[242]
  PIN q[243]
    DIRECTION OUTPUT ;
    USE SIGNAL ;
    PORT
      LAYER M5 ;
        RECT  23.952 34.368 23.976 34.56 ;
    END
  END q[243]
  PIN q[244]
    DIRECTION OUTPUT ;
    USE SIGNAL ;
    PORT
      LAYER M3 ;
        RECT  24.048 34.416 24.066 34.56 ;
    END
  END q[244]
  PIN q[245]
    DIRECTION OUTPUT ;
    USE SIGNAL ;
    PORT
      LAYER M5 ;
        RECT  24.096 34.368 24.12 34.56 ;
    END
  END q[245]
  PIN q[246]
    DIRECTION OUTPUT ;
    USE SIGNAL ;
    PORT
      LAYER M3 ;
        RECT  24.192 34.416 24.21 34.56 ;
    END
  END q[246]
  PIN q[247]
    DIRECTION OUTPUT ;
    USE SIGNAL ;
    PORT
      LAYER M5 ;
        RECT  24.24 34.368 24.264 34.56 ;
    END
  END q[247]
  PIN q[248]
    DIRECTION OUTPUT ;
    USE SIGNAL ;
    PORT
      LAYER M3 ;
        RECT  24.336 34.416 24.354 34.56 ;
    END
  END q[248]
  PIN q[249]
    DIRECTION OUTPUT ;
    USE SIGNAL ;
    PORT
      LAYER M5 ;
        RECT  24.384 34.368 24.408 34.56 ;
    END
  END q[249]
  PIN q[24]
    DIRECTION OUTPUT ;
    USE SIGNAL ;
    PORT
      LAYER M3 ;
        RECT  8.208 34.416 8.226 34.56 ;
    END
  END q[24]
  PIN q[250]
    DIRECTION OUTPUT ;
    USE SIGNAL ;
    PORT
      LAYER M3 ;
        RECT  24.48 34.416 24.498 34.56 ;
    END
  END q[250]
  PIN q[251]
    DIRECTION OUTPUT ;
    USE SIGNAL ;
    PORT
      LAYER M5 ;
        RECT  24.528 34.368 24.552 34.56 ;
    END
  END q[251]
  PIN q[252]
    DIRECTION OUTPUT ;
    USE SIGNAL ;
    PORT
      LAYER M3 ;
        RECT  24.624 34.416 24.642 34.56 ;
    END
  END q[252]
  PIN q[253]
    DIRECTION OUTPUT ;
    USE SIGNAL ;
    PORT
      LAYER M5 ;
        RECT  24.672 34.368 24.696 34.56 ;
    END
  END q[253]
  PIN q[254]
    DIRECTION OUTPUT ;
    USE SIGNAL ;
    PORT
      LAYER M3 ;
        RECT  24.768 34.416 24.786 34.56 ;
    END
  END q[254]
  PIN q[255]
    DIRECTION OUTPUT ;
    USE SIGNAL ;
    PORT
      LAYER M5 ;
        RECT  24.816 34.368 24.84 34.56 ;
    END
  END q[255]
  PIN q[256]
    DIRECTION OUTPUT ;
    USE SIGNAL ;
    PORT
      LAYER M3 ;
        RECT  24.912 34.416 24.93 34.56 ;
    END
  END q[256]
  PIN q[257]
    DIRECTION OUTPUT ;
    USE SIGNAL ;
    PORT
      LAYER M5 ;
        RECT  24.96 34.368 24.984 34.56 ;
    END
  END q[257]
  PIN q[258]
    DIRECTION OUTPUT ;
    USE SIGNAL ;
    PORT
      LAYER M3 ;
        RECT  25.056 34.416 25.074 34.56 ;
    END
  END q[258]
  PIN q[259]
    DIRECTION OUTPUT ;
    USE SIGNAL ;
    PORT
      LAYER M5 ;
        RECT  25.104 34.368 25.128 34.56 ;
    END
  END q[259]
  PIN q[25]
    DIRECTION OUTPUT ;
    USE SIGNAL ;
    PORT
      LAYER M5 ;
        RECT  8.256 34.368 8.28 34.56 ;
    END
  END q[25]
  PIN q[260]
    DIRECTION OUTPUT ;
    USE SIGNAL ;
    PORT
      LAYER M3 ;
        RECT  25.2 34.416 25.218 34.56 ;
    END
  END q[260]
  PIN q[261]
    DIRECTION OUTPUT ;
    USE SIGNAL ;
    PORT
      LAYER M5 ;
        RECT  25.248 34.368 25.272 34.56 ;
    END
  END q[261]
  PIN q[262]
    DIRECTION OUTPUT ;
    USE SIGNAL ;
    PORT
      LAYER M3 ;
        RECT  25.344 34.416 25.362 34.56 ;
    END
  END q[262]
  PIN q[263]
    DIRECTION OUTPUT ;
    USE SIGNAL ;
    PORT
      LAYER M5 ;
        RECT  25.392 34.368 25.416 34.56 ;
    END
  END q[263]
  PIN q[264]
    DIRECTION OUTPUT ;
    USE SIGNAL ;
    PORT
      LAYER M3 ;
        RECT  25.488 34.416 25.506 34.56 ;
    END
  END q[264]
  PIN q[265]
    DIRECTION OUTPUT ;
    USE SIGNAL ;
    PORT
      LAYER M5 ;
        RECT  25.536 34.368 25.56 34.56 ;
    END
  END q[265]
  PIN q[266]
    DIRECTION OUTPUT ;
    USE SIGNAL ;
    PORT
      LAYER M3 ;
        RECT  25.632 34.416 25.65 34.56 ;
    END
  END q[266]
  PIN q[267]
    DIRECTION OUTPUT ;
    USE SIGNAL ;
    PORT
      LAYER M5 ;
        RECT  25.68 34.368 25.704 34.56 ;
    END
  END q[267]
  PIN q[268]
    DIRECTION OUTPUT ;
    USE SIGNAL ;
    PORT
      LAYER M3 ;
        RECT  25.776 34.416 25.794 34.56 ;
    END
  END q[268]
  PIN q[269]
    DIRECTION OUTPUT ;
    USE SIGNAL ;
    PORT
      LAYER M5 ;
        RECT  25.824 34.368 25.848 34.56 ;
    END
  END q[269]
  PIN q[26]
    DIRECTION OUTPUT ;
    USE SIGNAL ;
    PORT
      LAYER M3 ;
        RECT  8.352 34.416 8.37 34.56 ;
    END
  END q[26]
  PIN q[270]
    DIRECTION OUTPUT ;
    USE SIGNAL ;
    PORT
      LAYER M3 ;
        RECT  25.92 34.416 25.938 34.56 ;
    END
  END q[270]
  PIN q[271]
    DIRECTION OUTPUT ;
    USE SIGNAL ;
    PORT
      LAYER M5 ;
        RECT  25.968 34.368 25.992 34.56 ;
    END
  END q[271]
  PIN q[272]
    DIRECTION OUTPUT ;
    USE SIGNAL ;
    PORT
      LAYER M3 ;
        RECT  26.064 34.416 26.082 34.56 ;
    END
  END q[272]
  PIN q[273]
    DIRECTION OUTPUT ;
    USE SIGNAL ;
    PORT
      LAYER M5 ;
        RECT  26.112 34.368 26.136 34.56 ;
    END
  END q[273]
  PIN q[274]
    DIRECTION OUTPUT ;
    USE SIGNAL ;
    PORT
      LAYER M3 ;
        RECT  26.208 34.416 26.226 34.56 ;
    END
  END q[274]
  PIN q[275]
    DIRECTION OUTPUT ;
    USE SIGNAL ;
    PORT
      LAYER M5 ;
        RECT  26.256 34.368 26.28 34.56 ;
    END
  END q[275]
  PIN q[276]
    DIRECTION OUTPUT ;
    USE SIGNAL ;
    PORT
      LAYER M3 ;
        RECT  26.352 34.416 26.37 34.56 ;
    END
  END q[276]
  PIN q[277]
    DIRECTION OUTPUT ;
    USE SIGNAL ;
    PORT
      LAYER M5 ;
        RECT  26.4 34.368 26.424 34.56 ;
    END
  END q[277]
  PIN q[278]
    DIRECTION OUTPUT ;
    USE SIGNAL ;
    PORT
      LAYER M3 ;
        RECT  26.496 34.416 26.514 34.56 ;
    END
  END q[278]
  PIN q[279]
    DIRECTION OUTPUT ;
    USE SIGNAL ;
    PORT
      LAYER M5 ;
        RECT  26.544 34.368 26.568 34.56 ;
    END
  END q[279]
  PIN q[27]
    DIRECTION OUTPUT ;
    USE SIGNAL ;
    PORT
      LAYER M5 ;
        RECT  8.4 34.368 8.424 34.56 ;
    END
  END q[27]
  PIN q[280]
    DIRECTION OUTPUT ;
    USE SIGNAL ;
    PORT
      LAYER M3 ;
        RECT  26.64 34.416 26.658 34.56 ;
    END
  END q[280]
  PIN q[281]
    DIRECTION OUTPUT ;
    USE SIGNAL ;
    PORT
      LAYER M5 ;
        RECT  26.688 34.368 26.712 34.56 ;
    END
  END q[281]
  PIN q[282]
    DIRECTION OUTPUT ;
    USE SIGNAL ;
    PORT
      LAYER M3 ;
        RECT  26.784 34.416 26.802 34.56 ;
    END
  END q[282]
  PIN q[283]
    DIRECTION OUTPUT ;
    USE SIGNAL ;
    PORT
      LAYER M5 ;
        RECT  26.832 34.368 26.856 34.56 ;
    END
  END q[283]
  PIN q[284]
    DIRECTION OUTPUT ;
    USE SIGNAL ;
    PORT
      LAYER M3 ;
        RECT  26.928 34.416 26.946 34.56 ;
    END
  END q[284]
  PIN q[285]
    DIRECTION OUTPUT ;
    USE SIGNAL ;
    PORT
      LAYER M5 ;
        RECT  26.976 34.368 27 34.56 ;
    END
  END q[285]
  PIN q[286]
    DIRECTION OUTPUT ;
    USE SIGNAL ;
    PORT
      LAYER M3 ;
        RECT  27.072 34.416 27.09 34.56 ;
    END
  END q[286]
  PIN q[287]
    DIRECTION OUTPUT ;
    USE SIGNAL ;
    PORT
      LAYER M5 ;
        RECT  27.12 34.368 27.144 34.56 ;
    END
  END q[287]
  PIN q[288]
    DIRECTION OUTPUT ;
    USE SIGNAL ;
    PORT
      LAYER M3 ;
        RECT  27.216 34.416 27.234 34.56 ;
    END
  END q[288]
  PIN q[289]
    DIRECTION OUTPUT ;
    USE SIGNAL ;
    PORT
      LAYER M5 ;
        RECT  27.264 34.368 27.288 34.56 ;
    END
  END q[289]
  PIN q[28]
    DIRECTION OUTPUT ;
    USE SIGNAL ;
    PORT
      LAYER M3 ;
        RECT  8.496 34.416 8.514 34.56 ;
    END
  END q[28]
  PIN q[290]
    DIRECTION OUTPUT ;
    USE SIGNAL ;
    PORT
      LAYER M3 ;
        RECT  27.36 34.416 27.378 34.56 ;
    END
  END q[290]
  PIN q[291]
    DIRECTION OUTPUT ;
    USE SIGNAL ;
    PORT
      LAYER M5 ;
        RECT  27.408 34.368 27.432 34.56 ;
    END
  END q[291]
  PIN q[292]
    DIRECTION OUTPUT ;
    USE SIGNAL ;
    PORT
      LAYER M3 ;
        RECT  27.504 34.416 27.522 34.56 ;
    END
  END q[292]
  PIN q[293]
    DIRECTION OUTPUT ;
    USE SIGNAL ;
    PORT
      LAYER M5 ;
        RECT  27.552 34.368 27.576 34.56 ;
    END
  END q[293]
  PIN q[294]
    DIRECTION OUTPUT ;
    USE SIGNAL ;
    PORT
      LAYER M3 ;
        RECT  27.648 34.416 27.666 34.56 ;
    END
  END q[294]
  PIN q[295]
    DIRECTION OUTPUT ;
    USE SIGNAL ;
    PORT
      LAYER M5 ;
        RECT  27.696 34.368 27.72 34.56 ;
    END
  END q[295]
  PIN q[296]
    DIRECTION OUTPUT ;
    USE SIGNAL ;
    PORT
      LAYER M3 ;
        RECT  27.792 34.416 27.81 34.56 ;
    END
  END q[296]
  PIN q[297]
    DIRECTION OUTPUT ;
    USE SIGNAL ;
    PORT
      LAYER M5 ;
        RECT  27.84 34.368 27.864 34.56 ;
    END
  END q[297]
  PIN q[298]
    DIRECTION OUTPUT ;
    USE SIGNAL ;
    PORT
      LAYER M3 ;
        RECT  27.936 34.416 27.954 34.56 ;
    END
  END q[298]
  PIN q[299]
    DIRECTION OUTPUT ;
    USE SIGNAL ;
    PORT
      LAYER M5 ;
        RECT  27.984 34.368 28.008 34.56 ;
    END
  END q[299]
  PIN q[29]
    DIRECTION OUTPUT ;
    USE SIGNAL ;
    PORT
      LAYER M5 ;
        RECT  8.544 34.368 8.568 34.56 ;
    END
  END q[29]
  PIN q[2]
    DIRECTION OUTPUT ;
    USE SIGNAL ;
    PORT
      LAYER M3 ;
        RECT  6.624 34.416 6.642 34.56 ;
    END
  END q[2]
  PIN q[300]
    DIRECTION OUTPUT ;
    USE SIGNAL ;
    PORT
      LAYER M3 ;
        RECT  28.08 34.416 28.098 34.56 ;
    END
  END q[300]
  PIN q[301]
    DIRECTION OUTPUT ;
    USE SIGNAL ;
    PORT
      LAYER M5 ;
        RECT  28.128 34.368 28.152 34.56 ;
    END
  END q[301]
  PIN q[302]
    DIRECTION OUTPUT ;
    USE SIGNAL ;
    PORT
      LAYER M3 ;
        RECT  28.224 34.416 28.242 34.56 ;
    END
  END q[302]
  PIN q[303]
    DIRECTION OUTPUT ;
    USE SIGNAL ;
    PORT
      LAYER M5 ;
        RECT  28.272 34.368 28.296 34.56 ;
    END
  END q[303]
  PIN q[304]
    DIRECTION OUTPUT ;
    USE SIGNAL ;
    PORT
      LAYER M3 ;
        RECT  28.368 34.416 28.386 34.56 ;
    END
  END q[304]
  PIN q[305]
    DIRECTION OUTPUT ;
    USE SIGNAL ;
    PORT
      LAYER M5 ;
        RECT  28.416 34.368 28.44 34.56 ;
    END
  END q[305]
  PIN q[306]
    DIRECTION OUTPUT ;
    USE SIGNAL ;
    PORT
      LAYER M3 ;
        RECT  28.512 34.416 28.53 34.56 ;
    END
  END q[306]
  PIN q[307]
    DIRECTION OUTPUT ;
    USE SIGNAL ;
    PORT
      LAYER M5 ;
        RECT  28.56 34.368 28.584 34.56 ;
    END
  END q[307]
  PIN q[308]
    DIRECTION OUTPUT ;
    USE SIGNAL ;
    PORT
      LAYER M3 ;
        RECT  28.656 34.416 28.674 34.56 ;
    END
  END q[308]
  PIN q[309]
    DIRECTION OUTPUT ;
    USE SIGNAL ;
    PORT
      LAYER M5 ;
        RECT  28.704 34.368 28.728 34.56 ;
    END
  END q[309]
  PIN q[30]
    DIRECTION OUTPUT ;
    USE SIGNAL ;
    PORT
      LAYER M3 ;
        RECT  8.64 34.416 8.658 34.56 ;
    END
  END q[30]
  PIN q[310]
    DIRECTION OUTPUT ;
    USE SIGNAL ;
    PORT
      LAYER M3 ;
        RECT  28.8 34.416 28.818 34.56 ;
    END
  END q[310]
  PIN q[311]
    DIRECTION OUTPUT ;
    USE SIGNAL ;
    PORT
      LAYER M5 ;
        RECT  28.848 34.368 28.872 34.56 ;
    END
  END q[311]
  PIN q[312]
    DIRECTION OUTPUT ;
    USE SIGNAL ;
    PORT
      LAYER M3 ;
        RECT  28.944 34.416 28.962 34.56 ;
    END
  END q[312]
  PIN q[313]
    DIRECTION OUTPUT ;
    USE SIGNAL ;
    PORT
      LAYER M5 ;
        RECT  28.992 34.368 29.016 34.56 ;
    END
  END q[313]
  PIN q[314]
    DIRECTION OUTPUT ;
    USE SIGNAL ;
    PORT
      LAYER M3 ;
        RECT  29.088 34.416 29.106 34.56 ;
    END
  END q[314]
  PIN q[315]
    DIRECTION OUTPUT ;
    USE SIGNAL ;
    PORT
      LAYER M5 ;
        RECT  29.136 34.368 29.16 34.56 ;
    END
  END q[315]
  PIN q[316]
    DIRECTION OUTPUT ;
    USE SIGNAL ;
    PORT
      LAYER M3 ;
        RECT  29.232 34.416 29.25 34.56 ;
    END
  END q[316]
  PIN q[317]
    DIRECTION OUTPUT ;
    USE SIGNAL ;
    PORT
      LAYER M5 ;
        RECT  29.28 34.368 29.304 34.56 ;
    END
  END q[317]
  PIN q[318]
    DIRECTION OUTPUT ;
    USE SIGNAL ;
    PORT
      LAYER M3 ;
        RECT  29.376 34.416 29.394 34.56 ;
    END
  END q[318]
  PIN q[319]
    DIRECTION OUTPUT ;
    USE SIGNAL ;
    PORT
      LAYER M5 ;
        RECT  29.424 34.368 29.448 34.56 ;
    END
  END q[319]
  PIN q[31]
    DIRECTION OUTPUT ;
    USE SIGNAL ;
    PORT
      LAYER M5 ;
        RECT  8.688 34.368 8.712 34.56 ;
    END
  END q[31]
  PIN q[320]
    DIRECTION OUTPUT ;
    USE SIGNAL ;
    PORT
      LAYER M3 ;
        RECT  29.52 34.416 29.538 34.56 ;
    END
  END q[320]
  PIN q[321]
    DIRECTION OUTPUT ;
    USE SIGNAL ;
    PORT
      LAYER M5 ;
        RECT  29.568 34.368 29.592 34.56 ;
    END
  END q[321]
  PIN q[322]
    DIRECTION OUTPUT ;
    USE SIGNAL ;
    PORT
      LAYER M3 ;
        RECT  29.664 34.416 29.682 34.56 ;
    END
  END q[322]
  PIN q[323]
    DIRECTION OUTPUT ;
    USE SIGNAL ;
    PORT
      LAYER M5 ;
        RECT  29.712 34.368 29.736 34.56 ;
    END
  END q[323]
  PIN q[324]
    DIRECTION OUTPUT ;
    USE SIGNAL ;
    PORT
      LAYER M3 ;
        RECT  29.808 34.416 29.826 34.56 ;
    END
  END q[324]
  PIN q[325]
    DIRECTION OUTPUT ;
    USE SIGNAL ;
    PORT
      LAYER M5 ;
        RECT  29.856 34.368 29.88 34.56 ;
    END
  END q[325]
  PIN q[326]
    DIRECTION OUTPUT ;
    USE SIGNAL ;
    PORT
      LAYER M3 ;
        RECT  29.952 34.416 29.97 34.56 ;
    END
  END q[326]
  PIN q[327]
    DIRECTION OUTPUT ;
    USE SIGNAL ;
    PORT
      LAYER M5 ;
        RECT  30 34.368 30.024 34.56 ;
    END
  END q[327]
  PIN q[328]
    DIRECTION OUTPUT ;
    USE SIGNAL ;
    PORT
      LAYER M3 ;
        RECT  30.096 34.416 30.114 34.56 ;
    END
  END q[328]
  PIN q[329]
    DIRECTION OUTPUT ;
    USE SIGNAL ;
    PORT
      LAYER M5 ;
        RECT  30.144 34.368 30.168 34.56 ;
    END
  END q[329]
  PIN q[32]
    DIRECTION OUTPUT ;
    USE SIGNAL ;
    PORT
      LAYER M3 ;
        RECT  8.784 34.416 8.802 34.56 ;
    END
  END q[32]
  PIN q[330]
    DIRECTION OUTPUT ;
    USE SIGNAL ;
    PORT
      LAYER M3 ;
        RECT  30.24 34.416 30.258 34.56 ;
    END
  END q[330]
  PIN q[331]
    DIRECTION OUTPUT ;
    USE SIGNAL ;
    PORT
      LAYER M5 ;
        RECT  30.288 34.368 30.312 34.56 ;
    END
  END q[331]
  PIN q[332]
    DIRECTION OUTPUT ;
    USE SIGNAL ;
    PORT
      LAYER M3 ;
        RECT  30.384 34.416 30.402 34.56 ;
    END
  END q[332]
  PIN q[333]
    DIRECTION OUTPUT ;
    USE SIGNAL ;
    PORT
      LAYER M5 ;
        RECT  30.432 34.368 30.456 34.56 ;
    END
  END q[333]
  PIN q[334]
    DIRECTION OUTPUT ;
    USE SIGNAL ;
    PORT
      LAYER M3 ;
        RECT  30.528 34.416 30.546 34.56 ;
    END
  END q[334]
  PIN q[335]
    DIRECTION OUTPUT ;
    USE SIGNAL ;
    PORT
      LAYER M5 ;
        RECT  30.576 34.368 30.6 34.56 ;
    END
  END q[335]
  PIN q[336]
    DIRECTION OUTPUT ;
    USE SIGNAL ;
    PORT
      LAYER M3 ;
        RECT  30.672 34.416 30.69 34.56 ;
    END
  END q[336]
  PIN q[337]
    DIRECTION OUTPUT ;
    USE SIGNAL ;
    PORT
      LAYER M5 ;
        RECT  30.72 34.368 30.744 34.56 ;
    END
  END q[337]
  PIN q[338]
    DIRECTION OUTPUT ;
    USE SIGNAL ;
    PORT
      LAYER M3 ;
        RECT  30.816 34.416 30.834 34.56 ;
    END
  END q[338]
  PIN q[339]
    DIRECTION OUTPUT ;
    USE SIGNAL ;
    PORT
      LAYER M5 ;
        RECT  30.864 34.368 30.888 34.56 ;
    END
  END q[339]
  PIN q[33]
    DIRECTION OUTPUT ;
    USE SIGNAL ;
    PORT
      LAYER M5 ;
        RECT  8.832 34.368 8.856 34.56 ;
    END
  END q[33]
  PIN q[340]
    DIRECTION OUTPUT ;
    USE SIGNAL ;
    PORT
      LAYER M3 ;
        RECT  30.96 34.416 30.978 34.56 ;
    END
  END q[340]
  PIN q[341]
    DIRECTION OUTPUT ;
    USE SIGNAL ;
    PORT
      LAYER M5 ;
        RECT  31.008 34.368 31.032 34.56 ;
    END
  END q[341]
  PIN q[342]
    DIRECTION OUTPUT ;
    USE SIGNAL ;
    PORT
      LAYER M3 ;
        RECT  31.104 34.416 31.122 34.56 ;
    END
  END q[342]
  PIN q[343]
    DIRECTION OUTPUT ;
    USE SIGNAL ;
    PORT
      LAYER M5 ;
        RECT  31.152 34.368 31.176 34.56 ;
    END
  END q[343]
  PIN q[344]
    DIRECTION OUTPUT ;
    USE SIGNAL ;
    PORT
      LAYER M3 ;
        RECT  31.248 34.416 31.266 34.56 ;
    END
  END q[344]
  PIN q[345]
    DIRECTION OUTPUT ;
    USE SIGNAL ;
    PORT
      LAYER M5 ;
        RECT  31.296 34.368 31.32 34.56 ;
    END
  END q[345]
  PIN q[346]
    DIRECTION OUTPUT ;
    USE SIGNAL ;
    PORT
      LAYER M3 ;
        RECT  31.392 34.416 31.41 34.56 ;
    END
  END q[346]
  PIN q[347]
    DIRECTION OUTPUT ;
    USE SIGNAL ;
    PORT
      LAYER M5 ;
        RECT  31.44 34.368 31.464 34.56 ;
    END
  END q[347]
  PIN q[348]
    DIRECTION OUTPUT ;
    USE SIGNAL ;
    PORT
      LAYER M3 ;
        RECT  31.536 34.416 31.554 34.56 ;
    END
  END q[348]
  PIN q[349]
    DIRECTION OUTPUT ;
    USE SIGNAL ;
    PORT
      LAYER M5 ;
        RECT  31.584 34.368 31.608 34.56 ;
    END
  END q[349]
  PIN q[34]
    DIRECTION OUTPUT ;
    USE SIGNAL ;
    PORT
      LAYER M3 ;
        RECT  8.928 34.416 8.946 34.56 ;
    END
  END q[34]
  PIN q[350]
    DIRECTION OUTPUT ;
    USE SIGNAL ;
    PORT
      LAYER M3 ;
        RECT  31.68 34.416 31.698 34.56 ;
    END
  END q[350]
  PIN q[351]
    DIRECTION OUTPUT ;
    USE SIGNAL ;
    PORT
      LAYER M5 ;
        RECT  31.728 34.368 31.752 34.56 ;
    END
  END q[351]
  PIN q[352]
    DIRECTION OUTPUT ;
    USE SIGNAL ;
    PORT
      LAYER M3 ;
        RECT  31.824 34.416 31.842 34.56 ;
    END
  END q[352]
  PIN q[353]
    DIRECTION OUTPUT ;
    USE SIGNAL ;
    PORT
      LAYER M5 ;
        RECT  31.872 34.368 31.896 34.56 ;
    END
  END q[353]
  PIN q[354]
    DIRECTION OUTPUT ;
    USE SIGNAL ;
    PORT
      LAYER M3 ;
        RECT  31.968 34.416 31.986 34.56 ;
    END
  END q[354]
  PIN q[355]
    DIRECTION OUTPUT ;
    USE SIGNAL ;
    PORT
      LAYER M5 ;
        RECT  32.016 34.368 32.04 34.56 ;
    END
  END q[355]
  PIN q[356]
    DIRECTION OUTPUT ;
    USE SIGNAL ;
    PORT
      LAYER M3 ;
        RECT  32.112 34.416 32.13 34.56 ;
    END
  END q[356]
  PIN q[357]
    DIRECTION OUTPUT ;
    USE SIGNAL ;
    PORT
      LAYER M5 ;
        RECT  32.16 34.368 32.184 34.56 ;
    END
  END q[357]
  PIN q[358]
    DIRECTION OUTPUT ;
    USE SIGNAL ;
    PORT
      LAYER M3 ;
        RECT  32.256 34.416 32.274 34.56 ;
    END
  END q[358]
  PIN q[359]
    DIRECTION OUTPUT ;
    USE SIGNAL ;
    PORT
      LAYER M5 ;
        RECT  32.304 34.368 32.328 34.56 ;
    END
  END q[359]
  PIN q[35]
    DIRECTION OUTPUT ;
    USE SIGNAL ;
    PORT
      LAYER M5 ;
        RECT  8.976 34.368 9 34.56 ;
    END
  END q[35]
  PIN q[360]
    DIRECTION OUTPUT ;
    USE SIGNAL ;
    PORT
      LAYER M3 ;
        RECT  32.4 34.416 32.418 34.56 ;
    END
  END q[360]
  PIN q[361]
    DIRECTION OUTPUT ;
    USE SIGNAL ;
    PORT
      LAYER M5 ;
        RECT  32.448 34.368 32.472 34.56 ;
    END
  END q[361]
  PIN q[362]
    DIRECTION OUTPUT ;
    USE SIGNAL ;
    PORT
      LAYER M3 ;
        RECT  32.544 34.416 32.562 34.56 ;
    END
  END q[362]
  PIN q[363]
    DIRECTION OUTPUT ;
    USE SIGNAL ;
    PORT
      LAYER M5 ;
        RECT  32.592 34.368 32.616 34.56 ;
    END
  END q[363]
  PIN q[364]
    DIRECTION OUTPUT ;
    USE SIGNAL ;
    PORT
      LAYER M3 ;
        RECT  32.688 34.416 32.706 34.56 ;
    END
  END q[364]
  PIN q[365]
    DIRECTION OUTPUT ;
    USE SIGNAL ;
    PORT
      LAYER M5 ;
        RECT  32.736 34.368 32.76 34.56 ;
    END
  END q[365]
  PIN q[366]
    DIRECTION OUTPUT ;
    USE SIGNAL ;
    PORT
      LAYER M3 ;
        RECT  32.832 34.416 32.85 34.56 ;
    END
  END q[366]
  PIN q[367]
    DIRECTION OUTPUT ;
    USE SIGNAL ;
    PORT
      LAYER M5 ;
        RECT  32.88 34.368 32.904 34.56 ;
    END
  END q[367]
  PIN q[368]
    DIRECTION OUTPUT ;
    USE SIGNAL ;
    PORT
      LAYER M3 ;
        RECT  32.976 34.416 32.994 34.56 ;
    END
  END q[368]
  PIN q[369]
    DIRECTION OUTPUT ;
    USE SIGNAL ;
    PORT
      LAYER M5 ;
        RECT  33.024 34.368 33.048 34.56 ;
    END
  END q[369]
  PIN q[36]
    DIRECTION OUTPUT ;
    USE SIGNAL ;
    PORT
      LAYER M3 ;
        RECT  9.072 34.416 9.09 34.56 ;
    END
  END q[36]
  PIN q[370]
    DIRECTION OUTPUT ;
    USE SIGNAL ;
    PORT
      LAYER M3 ;
        RECT  33.12 34.416 33.138 34.56 ;
    END
  END q[370]
  PIN q[371]
    DIRECTION OUTPUT ;
    USE SIGNAL ;
    PORT
      LAYER M5 ;
        RECT  33.168 34.368 33.192 34.56 ;
    END
  END q[371]
  PIN q[372]
    DIRECTION OUTPUT ;
    USE SIGNAL ;
    PORT
      LAYER M3 ;
        RECT  33.264 34.416 33.282 34.56 ;
    END
  END q[372]
  PIN q[373]
    DIRECTION OUTPUT ;
    USE SIGNAL ;
    PORT
      LAYER M5 ;
        RECT  33.312 34.368 33.336 34.56 ;
    END
  END q[373]
  PIN q[374]
    DIRECTION OUTPUT ;
    USE SIGNAL ;
    PORT
      LAYER M3 ;
        RECT  33.408 34.416 33.426 34.56 ;
    END
  END q[374]
  PIN q[375]
    DIRECTION OUTPUT ;
    USE SIGNAL ;
    PORT
      LAYER M5 ;
        RECT  33.456 34.368 33.48 34.56 ;
    END
  END q[375]
  PIN q[376]
    DIRECTION OUTPUT ;
    USE SIGNAL ;
    PORT
      LAYER M3 ;
        RECT  33.552 34.416 33.57 34.56 ;
    END
  END q[376]
  PIN q[377]
    DIRECTION OUTPUT ;
    USE SIGNAL ;
    PORT
      LAYER M5 ;
        RECT  33.6 34.368 33.624 34.56 ;
    END
  END q[377]
  PIN q[378]
    DIRECTION OUTPUT ;
    USE SIGNAL ;
    PORT
      LAYER M3 ;
        RECT  33.696 34.416 33.714 34.56 ;
    END
  END q[378]
  PIN q[379]
    DIRECTION OUTPUT ;
    USE SIGNAL ;
    PORT
      LAYER M5 ;
        RECT  33.744 34.368 33.768 34.56 ;
    END
  END q[379]
  PIN q[37]
    DIRECTION OUTPUT ;
    USE SIGNAL ;
    PORT
      LAYER M5 ;
        RECT  9.12 34.368 9.144 34.56 ;
    END
  END q[37]
  PIN q[380]
    DIRECTION OUTPUT ;
    USE SIGNAL ;
    PORT
      LAYER M3 ;
        RECT  33.84 34.416 33.858 34.56 ;
    END
  END q[380]
  PIN q[381]
    DIRECTION OUTPUT ;
    USE SIGNAL ;
    PORT
      LAYER M5 ;
        RECT  33.888 34.368 33.912 34.56 ;
    END
  END q[381]
  PIN q[382]
    DIRECTION OUTPUT ;
    USE SIGNAL ;
    PORT
      LAYER M3 ;
        RECT  33.984 34.416 34.002 34.56 ;
    END
  END q[382]
  PIN q[383]
    DIRECTION OUTPUT ;
    USE SIGNAL ;
    PORT
      LAYER M5 ;
        RECT  34.032 34.368 34.056 34.56 ;
    END
  END q[383]
  PIN q[384]
    DIRECTION OUTPUT ;
    USE SIGNAL ;
    PORT
      LAYER M3 ;
        RECT  34.128 34.416 34.146 34.56 ;
    END
  END q[384]
  PIN q[385]
    DIRECTION OUTPUT ;
    USE SIGNAL ;
    PORT
      LAYER M5 ;
        RECT  34.176 34.368 34.2 34.56 ;
    END
  END q[385]
  PIN q[386]
    DIRECTION OUTPUT ;
    USE SIGNAL ;
    PORT
      LAYER M3 ;
        RECT  34.272 34.416 34.29 34.56 ;
    END
  END q[386]
  PIN q[387]
    DIRECTION OUTPUT ;
    USE SIGNAL ;
    PORT
      LAYER M5 ;
        RECT  34.32 34.368 34.344 34.56 ;
    END
  END q[387]
  PIN q[388]
    DIRECTION OUTPUT ;
    USE SIGNAL ;
    PORT
      LAYER M3 ;
        RECT  34.416 34.416 34.434 34.56 ;
    END
  END q[388]
  PIN q[389]
    DIRECTION OUTPUT ;
    USE SIGNAL ;
    PORT
      LAYER M5 ;
        RECT  34.464 34.368 34.488 34.56 ;
    END
  END q[389]
  PIN q[38]
    DIRECTION OUTPUT ;
    USE SIGNAL ;
    PORT
      LAYER M3 ;
        RECT  9.216 34.416 9.234 34.56 ;
    END
  END q[38]
  PIN q[390]
    DIRECTION OUTPUT ;
    USE SIGNAL ;
    PORT
      LAYER M3 ;
        RECT  34.56 34.416 34.578 34.56 ;
    END
  END q[390]
  PIN q[391]
    DIRECTION OUTPUT ;
    USE SIGNAL ;
    PORT
      LAYER M5 ;
        RECT  34.608 34.368 34.632 34.56 ;
    END
  END q[391]
  PIN q[392]
    DIRECTION OUTPUT ;
    USE SIGNAL ;
    PORT
      LAYER M3 ;
        RECT  34.704 34.416 34.722 34.56 ;
    END
  END q[392]
  PIN q[393]
    DIRECTION OUTPUT ;
    USE SIGNAL ;
    PORT
      LAYER M5 ;
        RECT  34.752 34.368 34.776 34.56 ;
    END
  END q[393]
  PIN q[394]
    DIRECTION OUTPUT ;
    USE SIGNAL ;
    PORT
      LAYER M3 ;
        RECT  34.848 34.416 34.866 34.56 ;
    END
  END q[394]
  PIN q[395]
    DIRECTION OUTPUT ;
    USE SIGNAL ;
    PORT
      LAYER M5 ;
        RECT  34.896 34.368 34.92 34.56 ;
    END
  END q[395]
  PIN q[396]
    DIRECTION OUTPUT ;
    USE SIGNAL ;
    PORT
      LAYER M3 ;
        RECT  34.992 34.416 35.01 34.56 ;
    END
  END q[396]
  PIN q[397]
    DIRECTION OUTPUT ;
    USE SIGNAL ;
    PORT
      LAYER M5 ;
        RECT  35.04 34.368 35.064 34.56 ;
    END
  END q[397]
  PIN q[398]
    DIRECTION OUTPUT ;
    USE SIGNAL ;
    PORT
      LAYER M3 ;
        RECT  35.136 34.416 35.154 34.56 ;
    END
  END q[398]
  PIN q[399]
    DIRECTION OUTPUT ;
    USE SIGNAL ;
    PORT
      LAYER M5 ;
        RECT  35.184 34.368 35.208 34.56 ;
    END
  END q[399]
  PIN q[39]
    DIRECTION OUTPUT ;
    USE SIGNAL ;
    PORT
      LAYER M5 ;
        RECT  9.264 34.368 9.288 34.56 ;
    END
  END q[39]
  PIN q[3]
    DIRECTION OUTPUT ;
    USE SIGNAL ;
    PORT
      LAYER M5 ;
        RECT  6.672 34.368 6.696 34.56 ;
    END
  END q[3]
  PIN q[400]
    DIRECTION OUTPUT ;
    USE SIGNAL ;
    PORT
      LAYER M3 ;
        RECT  35.28 34.416 35.298 34.56 ;
    END
  END q[400]
  PIN q[401]
    DIRECTION OUTPUT ;
    USE SIGNAL ;
    PORT
      LAYER M5 ;
        RECT  35.328 34.368 35.352 34.56 ;
    END
  END q[401]
  PIN q[402]
    DIRECTION OUTPUT ;
    USE SIGNAL ;
    PORT
      LAYER M3 ;
        RECT  35.424 34.416 35.442 34.56 ;
    END
  END q[402]
  PIN q[403]
    DIRECTION OUTPUT ;
    USE SIGNAL ;
    PORT
      LAYER M5 ;
        RECT  35.472 34.368 35.496 34.56 ;
    END
  END q[403]
  PIN q[404]
    DIRECTION OUTPUT ;
    USE SIGNAL ;
    PORT
      LAYER M3 ;
        RECT  35.568 34.416 35.586 34.56 ;
    END
  END q[404]
  PIN q[405]
    DIRECTION OUTPUT ;
    USE SIGNAL ;
    PORT
      LAYER M5 ;
        RECT  35.616 34.368 35.64 34.56 ;
    END
  END q[405]
  PIN q[406]
    DIRECTION OUTPUT ;
    USE SIGNAL ;
    PORT
      LAYER M3 ;
        RECT  35.712 34.416 35.73 34.56 ;
    END
  END q[406]
  PIN q[407]
    DIRECTION OUTPUT ;
    USE SIGNAL ;
    PORT
      LAYER M5 ;
        RECT  35.76 34.368 35.784 34.56 ;
    END
  END q[407]
  PIN q[408]
    DIRECTION OUTPUT ;
    USE SIGNAL ;
    PORT
      LAYER M3 ;
        RECT  35.856 34.416 35.874 34.56 ;
    END
  END q[408]
  PIN q[40]
    DIRECTION OUTPUT ;
    USE SIGNAL ;
    PORT
      LAYER M3 ;
        RECT  9.36 34.416 9.378 34.56 ;
    END
  END q[40]
  PIN q[41]
    DIRECTION OUTPUT ;
    USE SIGNAL ;
    PORT
      LAYER M5 ;
        RECT  9.408 34.368 9.432 34.56 ;
    END
  END q[41]
  PIN q[42]
    DIRECTION OUTPUT ;
    USE SIGNAL ;
    PORT
      LAYER M3 ;
        RECT  9.504 34.416 9.522 34.56 ;
    END
  END q[42]
  PIN q[43]
    DIRECTION OUTPUT ;
    USE SIGNAL ;
    PORT
      LAYER M5 ;
        RECT  9.552 34.368 9.576 34.56 ;
    END
  END q[43]
  PIN q[44]
    DIRECTION OUTPUT ;
    USE SIGNAL ;
    PORT
      LAYER M3 ;
        RECT  9.648 34.416 9.666 34.56 ;
    END
  END q[44]
  PIN q[45]
    DIRECTION OUTPUT ;
    USE SIGNAL ;
    PORT
      LAYER M5 ;
        RECT  9.696 34.368 9.72 34.56 ;
    END
  END q[45]
  PIN q[46]
    DIRECTION OUTPUT ;
    USE SIGNAL ;
    PORT
      LAYER M3 ;
        RECT  9.792 34.416 9.81 34.56 ;
    END
  END q[46]
  PIN q[47]
    DIRECTION OUTPUT ;
    USE SIGNAL ;
    PORT
      LAYER M5 ;
        RECT  9.84 34.368 9.864 34.56 ;
    END
  END q[47]
  PIN q[48]
    DIRECTION OUTPUT ;
    USE SIGNAL ;
    PORT
      LAYER M3 ;
        RECT  9.936 34.416 9.954 34.56 ;
    END
  END q[48]
  PIN q[49]
    DIRECTION OUTPUT ;
    USE SIGNAL ;
    PORT
      LAYER M5 ;
        RECT  9.984 34.368 10.008 34.56 ;
    END
  END q[49]
  PIN q[4]
    DIRECTION OUTPUT ;
    USE SIGNAL ;
    PORT
      LAYER M3 ;
        RECT  6.768 34.416 6.786 34.56 ;
    END
  END q[4]
  PIN q[50]
    DIRECTION OUTPUT ;
    USE SIGNAL ;
    PORT
      LAYER M3 ;
        RECT  10.08 34.416 10.098 34.56 ;
    END
  END q[50]
  PIN q[51]
    DIRECTION OUTPUT ;
    USE SIGNAL ;
    PORT
      LAYER M5 ;
        RECT  10.128 34.368 10.152 34.56 ;
    END
  END q[51]
  PIN q[52]
    DIRECTION OUTPUT ;
    USE SIGNAL ;
    PORT
      LAYER M3 ;
        RECT  10.224 34.416 10.242 34.56 ;
    END
  END q[52]
  PIN q[53]
    DIRECTION OUTPUT ;
    USE SIGNAL ;
    PORT
      LAYER M5 ;
        RECT  10.272 34.368 10.296 34.56 ;
    END
  END q[53]
  PIN q[54]
    DIRECTION OUTPUT ;
    USE SIGNAL ;
    PORT
      LAYER M3 ;
        RECT  10.368 34.416 10.386 34.56 ;
    END
  END q[54]
  PIN q[55]
    DIRECTION OUTPUT ;
    USE SIGNAL ;
    PORT
      LAYER M5 ;
        RECT  10.416 34.368 10.44 34.56 ;
    END
  END q[55]
  PIN q[56]
    DIRECTION OUTPUT ;
    USE SIGNAL ;
    PORT
      LAYER M3 ;
        RECT  10.512 34.416 10.53 34.56 ;
    END
  END q[56]
  PIN q[57]
    DIRECTION OUTPUT ;
    USE SIGNAL ;
    PORT
      LAYER M5 ;
        RECT  10.56 34.368 10.584 34.56 ;
    END
  END q[57]
  PIN q[58]
    DIRECTION OUTPUT ;
    USE SIGNAL ;
    PORT
      LAYER M3 ;
        RECT  10.656 34.416 10.674 34.56 ;
    END
  END q[58]
  PIN q[59]
    DIRECTION OUTPUT ;
    USE SIGNAL ;
    PORT
      LAYER M5 ;
        RECT  10.704 34.368 10.728 34.56 ;
    END
  END q[59]
  PIN q[5]
    DIRECTION OUTPUT ;
    USE SIGNAL ;
    PORT
      LAYER M5 ;
        RECT  6.816 34.368 6.84 34.56 ;
    END
  END q[5]
  PIN q[60]
    DIRECTION OUTPUT ;
    USE SIGNAL ;
    PORT
      LAYER M3 ;
        RECT  10.8 34.416 10.818 34.56 ;
    END
  END q[60]
  PIN q[61]
    DIRECTION OUTPUT ;
    USE SIGNAL ;
    PORT
      LAYER M5 ;
        RECT  10.848 34.368 10.872 34.56 ;
    END
  END q[61]
  PIN q[62]
    DIRECTION OUTPUT ;
    USE SIGNAL ;
    PORT
      LAYER M3 ;
        RECT  10.944 34.416 10.962 34.56 ;
    END
  END q[62]
  PIN q[63]
    DIRECTION OUTPUT ;
    USE SIGNAL ;
    PORT
      LAYER M5 ;
        RECT  10.992 34.368 11.016 34.56 ;
    END
  END q[63]
  PIN q[64]
    DIRECTION OUTPUT ;
    USE SIGNAL ;
    PORT
      LAYER M3 ;
        RECT  11.088 34.416 11.106 34.56 ;
    END
  END q[64]
  PIN q[65]
    DIRECTION OUTPUT ;
    USE SIGNAL ;
    PORT
      LAYER M5 ;
        RECT  11.136 34.368 11.16 34.56 ;
    END
  END q[65]
  PIN q[66]
    DIRECTION OUTPUT ;
    USE SIGNAL ;
    PORT
      LAYER M3 ;
        RECT  11.232 34.416 11.25 34.56 ;
    END
  END q[66]
  PIN q[67]
    DIRECTION OUTPUT ;
    USE SIGNAL ;
    PORT
      LAYER M5 ;
        RECT  11.28 34.368 11.304 34.56 ;
    END
  END q[67]
  PIN q[68]
    DIRECTION OUTPUT ;
    USE SIGNAL ;
    PORT
      LAYER M3 ;
        RECT  11.376 34.416 11.394 34.56 ;
    END
  END q[68]
  PIN q[69]
    DIRECTION OUTPUT ;
    USE SIGNAL ;
    PORT
      LAYER M5 ;
        RECT  11.424 34.368 11.448 34.56 ;
    END
  END q[69]
  PIN q[6]
    DIRECTION OUTPUT ;
    USE SIGNAL ;
    PORT
      LAYER M3 ;
        RECT  6.912 34.416 6.93 34.56 ;
    END
  END q[6]
  PIN q[70]
    DIRECTION OUTPUT ;
    USE SIGNAL ;
    PORT
      LAYER M3 ;
        RECT  11.52 34.416 11.538 34.56 ;
    END
  END q[70]
  PIN q[71]
    DIRECTION OUTPUT ;
    USE SIGNAL ;
    PORT
      LAYER M5 ;
        RECT  11.568 34.368 11.592 34.56 ;
    END
  END q[71]
  PIN q[72]
    DIRECTION OUTPUT ;
    USE SIGNAL ;
    PORT
      LAYER M3 ;
        RECT  11.664 34.416 11.682 34.56 ;
    END
  END q[72]
  PIN q[73]
    DIRECTION OUTPUT ;
    USE SIGNAL ;
    PORT
      LAYER M5 ;
        RECT  11.712 34.368 11.736 34.56 ;
    END
  END q[73]
  PIN q[74]
    DIRECTION OUTPUT ;
    USE SIGNAL ;
    PORT
      LAYER M3 ;
        RECT  11.808 34.416 11.826 34.56 ;
    END
  END q[74]
  PIN q[75]
    DIRECTION OUTPUT ;
    USE SIGNAL ;
    PORT
      LAYER M5 ;
        RECT  11.856 34.368 11.88 34.56 ;
    END
  END q[75]
  PIN q[76]
    DIRECTION OUTPUT ;
    USE SIGNAL ;
    PORT
      LAYER M3 ;
        RECT  11.952 34.416 11.97 34.56 ;
    END
  END q[76]
  PIN q[77]
    DIRECTION OUTPUT ;
    USE SIGNAL ;
    PORT
      LAYER M5 ;
        RECT  12 34.368 12.024 34.56 ;
    END
  END q[77]
  PIN q[78]
    DIRECTION OUTPUT ;
    USE SIGNAL ;
    PORT
      LAYER M3 ;
        RECT  12.096 34.416 12.114 34.56 ;
    END
  END q[78]
  PIN q[79]
    DIRECTION OUTPUT ;
    USE SIGNAL ;
    PORT
      LAYER M5 ;
        RECT  12.144 34.368 12.168 34.56 ;
    END
  END q[79]
  PIN q[7]
    DIRECTION OUTPUT ;
    USE SIGNAL ;
    PORT
      LAYER M5 ;
        RECT  6.96 34.368 6.984 34.56 ;
    END
  END q[7]
  PIN q[80]
    DIRECTION OUTPUT ;
    USE SIGNAL ;
    PORT
      LAYER M3 ;
        RECT  12.24 34.416 12.258 34.56 ;
    END
  END q[80]
  PIN q[81]
    DIRECTION OUTPUT ;
    USE SIGNAL ;
    PORT
      LAYER M5 ;
        RECT  12.288 34.368 12.312 34.56 ;
    END
  END q[81]
  PIN q[82]
    DIRECTION OUTPUT ;
    USE SIGNAL ;
    PORT
      LAYER M3 ;
        RECT  12.384 34.416 12.402 34.56 ;
    END
  END q[82]
  PIN q[83]
    DIRECTION OUTPUT ;
    USE SIGNAL ;
    PORT
      LAYER M5 ;
        RECT  12.432 34.368 12.456 34.56 ;
    END
  END q[83]
  PIN q[84]
    DIRECTION OUTPUT ;
    USE SIGNAL ;
    PORT
      LAYER M3 ;
        RECT  12.528 34.416 12.546 34.56 ;
    END
  END q[84]
  PIN q[85]
    DIRECTION OUTPUT ;
    USE SIGNAL ;
    PORT
      LAYER M5 ;
        RECT  12.576 34.368 12.6 34.56 ;
    END
  END q[85]
  PIN q[86]
    DIRECTION OUTPUT ;
    USE SIGNAL ;
    PORT
      LAYER M3 ;
        RECT  12.672 34.416 12.69 34.56 ;
    END
  END q[86]
  PIN q[87]
    DIRECTION OUTPUT ;
    USE SIGNAL ;
    PORT
      LAYER M5 ;
        RECT  12.72 34.368 12.744 34.56 ;
    END
  END q[87]
  PIN q[88]
    DIRECTION OUTPUT ;
    USE SIGNAL ;
    PORT
      LAYER M3 ;
        RECT  12.816 34.416 12.834 34.56 ;
    END
  END q[88]
  PIN q[89]
    DIRECTION OUTPUT ;
    USE SIGNAL ;
    PORT
      LAYER M5 ;
        RECT  12.864 34.368 12.888 34.56 ;
    END
  END q[89]
  PIN q[8]
    DIRECTION OUTPUT ;
    USE SIGNAL ;
    PORT
      LAYER M3 ;
        RECT  7.056 34.416 7.074 34.56 ;
    END
  END q[8]
  PIN q[90]
    DIRECTION OUTPUT ;
    USE SIGNAL ;
    PORT
      LAYER M3 ;
        RECT  12.96 34.416 12.978 34.56 ;
    END
  END q[90]
  PIN q[91]
    DIRECTION OUTPUT ;
    USE SIGNAL ;
    PORT
      LAYER M5 ;
        RECT  13.008 34.368 13.032 34.56 ;
    END
  END q[91]
  PIN q[92]
    DIRECTION OUTPUT ;
    USE SIGNAL ;
    PORT
      LAYER M3 ;
        RECT  13.104 34.416 13.122 34.56 ;
    END
  END q[92]
  PIN q[93]
    DIRECTION OUTPUT ;
    USE SIGNAL ;
    PORT
      LAYER M5 ;
        RECT  13.152 34.368 13.176 34.56 ;
    END
  END q[93]
  PIN q[94]
    DIRECTION OUTPUT ;
    USE SIGNAL ;
    PORT
      LAYER M3 ;
        RECT  13.248 34.416 13.266 34.56 ;
    END
  END q[94]
  PIN q[95]
    DIRECTION OUTPUT ;
    USE SIGNAL ;
    PORT
      LAYER M5 ;
        RECT  13.296 34.368 13.32 34.56 ;
    END
  END q[95]
  PIN q[96]
    DIRECTION OUTPUT ;
    USE SIGNAL ;
    PORT
      LAYER M3 ;
        RECT  13.392 34.416 13.41 34.56 ;
    END
  END q[96]
  PIN q[97]
    DIRECTION OUTPUT ;
    USE SIGNAL ;
    PORT
      LAYER M5 ;
        RECT  13.44 34.368 13.464 34.56 ;
    END
  END q[97]
  PIN q[98]
    DIRECTION OUTPUT ;
    USE SIGNAL ;
    PORT
      LAYER M3 ;
        RECT  13.536 34.416 13.554 34.56 ;
    END
  END q[98]
  PIN q[99]
    DIRECTION OUTPUT ;
    USE SIGNAL ;
    PORT
      LAYER M5 ;
        RECT  13.584 34.368 13.608 34.56 ;
    END
  END q[99]
  PIN q[9]
    DIRECTION OUTPUT ;
    USE SIGNAL ;
    PORT
      LAYER M5 ;
        RECT  7.104 34.368 7.128 34.56 ;
    END
  END q[9]
  PIN rst_n
    DIRECTION INPUT ;
    USE SIGNAL ;
    PORT
      LAYER M4 ;
        RECT  0 14.88 0.192 14.904 ;
    END
    PORT
      LAYER M4 ;
        RECT  0.156 14.88 0.245 14.904 ;
    END
  END rst_n
  PIN VDD
    DIRECTION INOUT ;
    USE POWER ;
    PORT
      LAYER M5 ;
        RECT  40.392 2.151 40.512 32.409 ;
        RECT  34.992 2.151 35.112 32.409 ;
        RECT  29.592 2.151 29.712 32.409 ;
        RECT  24.192 2.151 24.312 32.409 ;
        RECT  18.792 2.151 18.912 32.409 ;
        RECT  13.392 2.151 13.512 32.409 ;
        RECT  7.992 2.151 8.112 32.409 ;
        RECT  2.592 2.151 2.712 32.409 ;
    END
  END VDD
  PIN VSS
    DIRECTION INOUT ;
    USE GROUND ;
    PORT
      LAYER M5 ;
        RECT  40.2 2.137 40.32 32.423 ;
        RECT  34.8 2.137 34.92 32.423 ;
        RECT  29.4 2.137 29.52 32.423 ;
        RECT  24 2.137 24.12 32.423 ;
        RECT  18.6 2.137 18.72 32.423 ;
        RECT  13.2 2.137 13.32 32.423 ;
        RECT  7.8 2.137 7.92 32.423 ;
        RECT  2.4 2.137 2.52 32.423 ;
    END
  END VSS
  # OT_OBS_CLOSED layer=M5 d_um=1.536 added=11
  OBS
    LAYER RVTN ;
     RECT  2.16 2.16 41.04 2.295 ;
     RECT  2.16 2.565 41.04 2.835 ;
     RECT  2.16 3.105 41.04 3.375 ;
     RECT  2.16 3.645 41.04 3.915 ;
     RECT  2.16 4.185 41.04 4.455 ;
     RECT  2.16 4.725 41.04 4.995 ;
     RECT  2.16 5.265 41.04 5.535 ;
     RECT  2.16 5.805 41.04 6.075 ;
     RECT  2.16 6.345 41.04 6.615 ;
     RECT  2.16 6.885 41.04 7.155 ;
     RECT  2.16 7.425 41.04 7.695 ;
     RECT  2.16 7.965 41.04 8.235 ;
     RECT  2.16 8.505 41.04 8.775 ;
     RECT  2.16 9.045 41.04 9.315 ;
     RECT  2.16 9.585 41.04 9.855 ;
     RECT  2.16 10.125 41.04 10.395 ;
     RECT  2.16 10.665 41.04 10.935 ;
     RECT  2.16 11.205 41.04 11.475 ;
     RECT  2.16 11.745 41.04 12.015 ;
     RECT  2.16 12.285 41.04 12.555 ;
     RECT  2.16 12.825 41.04 13.095 ;
     RECT  2.16 13.365 41.04 13.635 ;
     RECT  2.16 13.905 41.04 14.175 ;
     RECT  2.16 14.445 41.04 14.715 ;
     RECT  2.16 14.985 41.04 15.255 ;
     RECT  2.16 15.525 41.04 15.795 ;
     RECT  2.16 16.065 41.04 16.335 ;
     RECT  2.16 16.605 41.04 16.875 ;
     RECT  2.16 17.145 41.04 17.415 ;
     RECT  2.16 17.685 41.04 17.955 ;
     RECT  2.16 18.225 41.04 18.495 ;
     RECT  2.16 18.765 41.04 19.035 ;
     RECT  2.16 19.305 41.04 19.575 ;
     RECT  2.16 19.845 41.04 20.115 ;
     RECT  2.16 20.385 41.04 20.655 ;
     RECT  2.16 20.925 41.04 21.195 ;
     RECT  2.16 21.465 41.04 21.735 ;
     RECT  2.16 22.005 41.04 22.275 ;
     RECT  2.16 22.545 41.04 22.815 ;
     RECT  2.16 23.085 41.04 23.355 ;
     RECT  2.16 23.625 41.04 23.895 ;
     RECT  2.16 24.165 41.04 24.435 ;
     RECT  2.16 24.705 41.04 24.975 ;
     RECT  2.16 25.245 41.04 25.515 ;
     RECT  2.16 25.785 41.04 26.055 ;
     RECT  2.16 26.325 41.04 26.595 ;
     RECT  2.16 26.865 41.04 27.135 ;
     RECT  2.16 27.405 41.04 27.675 ;
     RECT  2.16 27.945 41.04 28.215 ;
     RECT  2.16 28.485 41.04 28.755 ;
     RECT  2.16 29.025 41.04 29.295 ;
     RECT  2.16 29.565 41.04 29.835 ;
     RECT  2.16 30.105 41.04 30.375 ;
     RECT  2.16 30.645 41.04 30.915 ;
     RECT  2.16 31.185 41.04 31.455 ;
     RECT  2.16 31.725 41.04 31.995 ;
     RECT  2.16 32.265 41.04 32.4 ;
    LAYER RVTP ;
     RECT  2.16 2.295 41.04 2.565 ;
     RECT  2.16 2.835 41.04 3.105 ;
     RECT  2.16 3.375 41.04 3.645 ;
     RECT  2.16 3.915 41.04 4.185 ;
     RECT  2.16 4.455 41.04 4.725 ;
     RECT  2.16 4.995 41.04 5.265 ;
     RECT  2.16 5.535 41.04 5.805 ;
     RECT  2.16 6.075 41.04 6.345 ;
     RECT  2.16 6.615 41.04 6.885 ;
     RECT  2.16 7.155 41.04 7.425 ;
     RECT  2.16 7.695 41.04 7.965 ;
     RECT  2.16 8.235 41.04 8.505 ;
     RECT  2.16 8.775 41.04 9.045 ;
     RECT  2.16 9.315 41.04 9.585 ;
     RECT  2.16 9.855 41.04 10.125 ;
     RECT  2.16 10.395 41.04 10.665 ;
     RECT  2.16 10.935 41.04 11.205 ;
     RECT  2.16 11.475 41.04 11.745 ;
     RECT  2.16 12.015 41.04 12.285 ;
     RECT  2.16 12.555 41.04 12.825 ;
     RECT  2.16 13.095 41.04 13.365 ;
     RECT  2.16 13.635 41.04 13.905 ;
     RECT  2.16 14.175 41.04 14.445 ;
     RECT  2.16 14.715 41.04 14.985 ;
     RECT  2.16 15.255 41.04 15.525 ;
     RECT  2.16 15.795 41.04 16.065 ;
     RECT  2.16 16.335 41.04 16.605 ;
     RECT  2.16 16.875 41.04 17.145 ;
     RECT  2.16 17.415 41.04 17.685 ;
     RECT  2.16 17.955 41.04 18.225 ;
     RECT  2.16 18.495 41.04 18.765 ;
     RECT  2.16 19.035 41.04 19.305 ;
     RECT  2.16 19.575 41.04 19.845 ;
     RECT  2.16 20.115 41.04 20.385 ;
     RECT  2.16 20.655 41.04 20.925 ;
     RECT  2.16 21.195 41.04 21.465 ;
     RECT  2.16 21.735 41.04 22.005 ;
     RECT  2.16 22.275 41.04 22.545 ;
     RECT  2.16 22.815 41.04 23.085 ;
     RECT  2.16 23.355 41.04 23.625 ;
     RECT  2.16 23.895 41.04 24.165 ;
     RECT  2.16 24.435 41.04 24.705 ;
     RECT  2.16 24.975 41.04 25.245 ;
     RECT  2.16 25.515 41.04 25.785 ;
     RECT  2.16 26.055 41.04 26.325 ;
     RECT  2.16 26.595 41.04 26.865 ;
     RECT  2.16 27.135 41.04 27.405 ;
     RECT  2.16 27.675 41.04 27.945 ;
     RECT  2.16 28.215 41.04 28.485 ;
     RECT  2.16 28.755 41.04 29.025 ;
     RECT  2.16 29.295 41.04 29.565 ;
     RECT  2.16 29.835 41.04 30.105 ;
     RECT  2.16 30.375 41.04 30.645 ;
     RECT  2.16 30.915 41.04 31.185 ;
     RECT  2.16 31.455 41.04 31.725 ;
     RECT  2.16 31.995 41.04 32.265 ;
    LAYER M1 ;
     RECT  2.16 2.151 41.04 32.409 ;
    LAYER M2 ;
     RECT  0.211 15.192 2.16 15.21 ;
     RECT  2.16 2.151 5.251 32.409 ;
     RECT  5.251 2.151 6.367 32.454 ;
     RECT  6.367 2.106 6.547 32.454 ;
     RECT  6.547 2.106 6.647 33.066 ;
     RECT  6.583 0.216 7.123 0.234 ;
     RECT  7.123 0.144 7.511 0.234 ;
     RECT  7.627 33.741 7.727 33.759 ;
     RECT  6.647 2.106 7.735 32.454 ;
     RECT  7.735 1.728 8.059 32.49 ;
     RECT  8.059 1.728 8.087 33.066 ;
     RECT  8.087 1.764 8.195 33.066 ;
     RECT  8.195 1.764 8.923 32.409 ;
     RECT  8.923 1.728 9.167 32.409 ;
     RECT  9.167 2.151 9.175 32.409 ;
     RECT  9.175 2.151 9.383 33.066 ;
     RECT  7.511 0.144 9.851 0.162 ;
     RECT  9.383 2.151 11.011 32.409 ;
     RECT  11.011 2.151 11.111 33.066 ;
     RECT  10.723 0.144 11.119 0.162 ;
     RECT  11.111 2.151 11.227 32.679 ;
     RECT  11.119 0.144 11.335 0.234 ;
     RECT  11.227 1.728 11.443 32.679 ;
     RECT  11.443 1.152 11.543 32.679 ;
     RECT  11.543 1.152 11.939 1.17 ;
     RECT  11.335 0.144 11.975 0.279 ;
     RECT  11.975 0.261 12.091 0.279 ;
     RECT  12.091 0.261 12.263 0.36 ;
     RECT  11.543 2.151 12.379 32.679 ;
     RECT  12.379 2.151 13.199 33.066 ;
     RECT  12.739 0.144 13.379 0.162 ;
     RECT  13.199 2.151 13.531 32.409 ;
     RECT  13.531 1.728 13.703 32.409 ;
     RECT  13.703 2.151 14.611 32.409 ;
     RECT  14.251 0.144 14.639 0.162 ;
     RECT  14.611 2.151 15.763 33.066 ;
     RECT  15.763 2.106 15.791 33.066 ;
     RECT  15.791 2.106 16.591 33.03 ;
     RECT  16.591 2.106 16.943 33.066 ;
     RECT  17.527 1.152 17.627 1.17 ;
     RECT  15.403 0.144 18.023 0.162 ;
     RECT  16.943 2.151 18.239 33.066 ;
     RECT  18.535 1.152 18.743 1.17 ;
     RECT  18.239 2.151 19.075 32.994 ;
     RECT  19.075 2.151 19.679 33.066 ;
     RECT  19.147 0.144 20.911 0.162 ;
     RECT  20.911 0.144 21.047 0.234 ;
     RECT  19.679 2.151 21.307 32.409 ;
     RECT  21.307 2.151 21.451 32.994 ;
     RECT  21.047 0.144 21.479 0.162 ;
     RECT  21.451 2.151 22.027 33.066 ;
     RECT  22.027 1.728 22.199 33.066 ;
     RECT  22.199 1.728 22.307 32.49 ;
     RECT  22.243 33.741 22.343 33.759 ;
     RECT  22.315 0.144 22.459 0.162 ;
     RECT  22.459 0.144 22.595 0.234 ;
     RECT  22.595 0.216 22.703 0.234 ;
     RECT  22.307 2.151 23.323 32.49 ;
     RECT  23.323 1.728 23.431 32.49 ;
     RECT  23.431 1.728 23.531 33.066 ;
     RECT  23.531 2.151 24.403 33.066 ;
     RECT  24.403 1.728 24.467 33.066 ;
     RECT  23.611 0.144 24.503 0.162 ;
     RECT  24.467 1.728 24.503 32.454 ;
     RECT  24.503 1.728 25.331 32.409 ;
     RECT  27.139 0.144 27.851 0.162 ;
     RECT  28.363 1.152 28.463 1.17 ;
     RECT  28.651 33.156 28.831 33.174 ;
     RECT  25.331 2.151 28.939 32.409 ;
     RECT  28.831 33.156 28.967 33.264 ;
     RECT  28.939 1.728 29.147 32.409 ;
     RECT  29.227 33.741 29.363 33.759 ;
     RECT  29.147 2.151 29.515 32.409 ;
     RECT  29.515 2.151 29.759 32.49 ;
     RECT  29.335 0.144 29.803 0.162 ;
     RECT  29.803 0.144 30.083 0.234 ;
     RECT  29.759 2.151 30.767 32.454 ;
     RECT  30.083 0.144 30.919 0.162 ;
     RECT  30.919 0.144 31.271 0.234 ;
     RECT  31.271 0.144 31.451 0.162 ;
     RECT  30.767 2.151 32.395 32.409 ;
     RECT  32.395 1.728 32.567 32.409 ;
     RECT  32.683 1.152 33.071 1.242 ;
     RECT  32.567 2.151 33.115 32.409 ;
     RECT  32.251 0.144 33.503 0.162 ;
     RECT  33.115 2.151 33.547 33.066 ;
     RECT  33.547 1.728 33.683 33.066 ;
     RECT  34.411 1.152 34.511 1.17 ;
     RECT  33.683 2.151 34.771 33.066 ;
     RECT  34.267 0.144 35.131 0.162 ;
     RECT  34.771 1.728 35.131 33.066 ;
     RECT  35.131 0.144 35.267 0.234 ;
     RECT  35.131 1.728 35.275 33.102 ;
     RECT  35.275 1.692 35.483 33.102 ;
     RECT  35.267 0.144 35.771 0.162 ;
     RECT  35.483 2.151 36.203 33.102 ;
     RECT  36.203 2.151 36.347 32.49 ;
     RECT  36.347 2.151 36.959 32.454 ;
     RECT  36.959 2.151 41.04 32.409 ;
    LAYER M3 ;
     RECT  6.48 0.108 35.874 1.771 ;
     RECT  6.408 1.771 35.874 2.101 ;
     RECT  6.372 2.101 35.874 2.371 ;
     RECT  2.415 2.143 2.505 2.413 ;
     RECT  40.215 2.143 40.305 2.413 ;
     RECT  6.372 2.371 35.91 2.641 ;
     RECT  36.648 2.371 36.666 2.641 ;
     RECT  5.868 2.641 36.702 3.721 ;
     RECT  5.796 3.721 36.702 3.991 ;
     RECT  5.688 3.991 36.702 5.845 ;
     RECT  5.544 5.845 36.702 6.115 ;
     RECT  5.544 6.115 36.738 6.151 ;
     RECT  5.544 6.151 37.242 6.845 ;
     RECT  5.76 6.845 37.242 7.663 ;
     RECT  5.58 7.663 37.242 9.481 ;
     RECT  0.216 14.875 0.234 15.215 ;
     RECT  5.544 9.481 37.242 31.531 ;
     RECT  5.472 31.531 37.242 31.729 ;
     RECT  5.472 31.729 37.422 31.801 ;
     RECT  5.364 31.801 37.458 32.071 ;
     RECT  2.415 2.413 2.697 32.147 ;
     RECT  40.215 2.413 40.497 32.147 ;
     RECT  5.148 32.071 37.458 32.225 ;
     RECT  5.256 32.225 37.458 32.341 ;
     RECT  5.256 32.341 37.53 32.369 ;
     RECT  2.415 32.147 2.505 32.417 ;
     RECT  40.215 32.147 40.305 32.417 ;
     RECT  5.256 32.369 5.274 32.459 ;
     RECT  6.48 32.369 37.53 32.459 ;
     RECT  37.512 32.459 37.53 32.477 ;
     RECT  6.48 32.459 36.342 32.495 ;
     RECT  6.48 32.495 36.198 33.107 ;
     RECT  6.48 33.107 35.874 34.428 ;
    LAYER M4 ;
     RECT  0.229 9.84 2.408 9.864 ;
     RECT  2.408 2.148 2.512 32.412 ;
     RECT  2.512 2.418 2.704 32.142 ;
     RECT  2.704 9.84 6.181 9.864 ;
     RECT  5.533 6.576 6.469 6.6 ;
     RECT  5.929 7.584 6.469 7.608 ;
     RECT  6.397 1.776 6.497 1.8 ;
     RECT  6.181 8.976 6.577 9.864 ;
     RECT  6.001 32.064 6.641 32.088 ;
     RECT  6.517 33.072 6.641 33.096 ;
     RECT  6.497 1.728 6.649 1.8 ;
     RECT  6.649 1.728 6.707 2.28 ;
     RECT  6.641 32.064 6.721 33.096 ;
     RECT  6.469 6.576 6.797 7.608 ;
     RECT  6.577 8.976 6.797 10.824 ;
     RECT  6.721 31.872 6.85 33.096 ;
     RECT  6.865 3.984 6.937 4.008 ;
     RECT  6.85 31.824 6.973 33.096 ;
     RECT  7.189 30.24 7.261 30.264 ;
     RECT  7.261 29.664 7.405 30.264 ;
     RECT  6.973 31.344 7.405 33.096 ;
     RECT  6.997 11.424 7.429 11.448 ;
     RECT  7.117 12.528 7.429 12.552 ;
     RECT  7.261 0.192 7.513 0.216 ;
     RECT  7.405 29.664 7.525 33.096 ;
     RECT  7.513 0.192 7.571 1.128 ;
     RECT  7.525 29.664 7.573 33.672 ;
     RECT  6.829 5.856 7.58 5.88 ;
     RECT  6.937 3.984 7.621 4.584 ;
     RECT  7.573 29.088 7.657 33.672 ;
     RECT  6.707 2.208 7.808 2.28 ;
     RECT  7.621 3.888 7.808 4.584 ;
     RECT  7.58 5.664 7.808 5.88 ;
     RECT  6.797 7.392 7.808 7.608 ;
     RECT  6.797 8.976 7.808 10.2 ;
     RECT  7.429 11.424 7.808 12.552 ;
     RECT  7.657 13.68 7.808 13.704 ;
     RECT  7.669 27.888 7.808 27.912 ;
     RECT  7.657 29.088 7.808 33.768 ;
     RECT  7.808 2.148 7.859 33.768 ;
     RECT  7.571 0.288 8.003 1.128 ;
     RECT  7.859 2.148 8.104 33.048 ;
     RECT  8.104 8.496 8.237 14.52 ;
     RECT  8.237 8.496 8.345 10.872 ;
     RECT  8.003 0.288 8.387 0.312 ;
     RECT  8.237 11.952 8.489 14.52 ;
     RECT  8.104 26.736 8.525 33.048 ;
     RECT  8.489 11.952 8.569 13.224 ;
     RECT  8.525 26.736 8.677 27.96 ;
     RECT  8.569 12.528 8.741 13.224 ;
     RECT  8.525 29.088 8.777 33.048 ;
     RECT  8.345 10.848 8.915 10.872 ;
     RECT  8.777 29.088 8.963 31.896 ;
     RECT  8.161 1.728 9.011 1.848 ;
     RECT  8.104 3.408 9.029 7.416 ;
     RECT  8.677 26.784 9.059 27.96 ;
     RECT  8.777 33.024 9.068 33.048 ;
     RECT  9.068 33.024 9.155 33.096 ;
     RECT  8.104 15.936 9.173 16.2 ;
     RECT  9.029 3.408 9.203 6.84 ;
     RECT  8.345 8.496 9.205 9.864 ;
     RECT  9.059 26.784 9.317 26.904 ;
     RECT  9.317 26.88 9.353 26.904 ;
     RECT  9.173 15.936 9.395 15.96 ;
     RECT  9.205 7.968 9.493 9.864 ;
     RECT  8.489 14.208 9.589 14.52 ;
     RECT  9.203 3.408 9.629 6.408 ;
     RECT  9.629 3.312 9.683 6.408 ;
     RECT  9.155 33.024 9.785 33.048 ;
     RECT  9.589 14.208 9.821 14.808 ;
     RECT  9.493 7.968 9.925 10.248 ;
     RECT  9.385 11.376 9.925 11.4 ;
     RECT  8.963 29.088 9.997 29.784 ;
     RECT  8.963 30.768 9.997 31.896 ;
     RECT  8.741 12.528 10.021 13.176 ;
     RECT  9.821 14.208 10.021 14.52 ;
     RECT  9.997 29.088 10.067 31.896 ;
     RECT  9.059 27.936 10.097 27.96 ;
     RECT  10.067 29.088 10.097 30.264 ;
     RECT  9.925 7.968 10.109 11.4 ;
     RECT  10.067 31.344 10.117 31.896 ;
     RECT  10.021 12.528 10.153 14.52 ;
     RECT  9.683 3.312 10.165 5.16 ;
     RECT  10.117 17.04 10.205 17.064 ;
     RECT  10.165 2.88 10.217 5.16 ;
     RECT  10.205 16.512 10.289 17.064 ;
     RECT  10.109 8.4 10.297 11.4 ;
     RECT  9.683 6.384 10.433 6.408 ;
     RECT  10.297 11.376 10.469 11.4 ;
     RECT  10.097 27.936 10.501 30.264 ;
     RECT  10.501 27.888 10.597 30.264 ;
     RECT  10.297 8.4 10.613 10.152 ;
     RECT  10.597 27.648 10.691 30.264 ;
     RECT  10.691 30.192 10.757 30.264 ;
     RECT  10.613 8.448 10.787 10.152 ;
     RECT  10.717 6.576 10.789 6.6 ;
     RECT  10.691 27.648 10.835 29.112 ;
     RECT  10.117 31.344 10.837 32.472 ;
     RECT  10.741 26.592 10.897 26.616 ;
     RECT  10.835 27.648 10.897 28.008 ;
     RECT  10.837 31.344 10.981 32.52 ;
     RECT  10.501 33.648 10.981 33.672 ;
     RECT  10.835 29.088 11.009 29.112 ;
     RECT  10.757 30.24 11.009 30.264 ;
     RECT  10.153 13.152 11.113 14.52 ;
     RECT  11.113 13.152 11.132 15.384 ;
     RECT  10.787 8.448 11.153 8.472 ;
     RECT  10.981 31.344 11.161 33.672 ;
     RECT  11.132 13.056 11.197 15.384 ;
     RECT  11.161 31.344 11.221 33.048 ;
     RECT  11.197 13.056 11.333 14.808 ;
     RECT  11.221 31.296 11.365 33.048 ;
     RECT  10.789 6.576 11.369 6.84 ;
     RECT  10.217 2.88 11.461 5.112 ;
     RECT  11.473 11.952 11.509 11.976 ;
     RECT  11.333 13.056 11.509 13.464 ;
     RECT  11.365 30.384 11.549 33.048 ;
     RECT  11.509 11.952 11.699 13.464 ;
     RECT  11.699 12.528 11.795 13.464 ;
     RECT  11.549 32.976 11.843 33.048 ;
     RECT  10.897 26.592 11.845 28.008 ;
     RECT  11.365 15.792 11.893 15.816 ;
     RECT  10.787 9.648 11.941 10.152 ;
     RECT  11.549 30.384 11.981 31.944 ;
     RECT  11.725 7.968 12.017 7.992 ;
     RECT  11.977 0.576 12.061 0.6 ;
     RECT  11.461 2.832 12.085 5.112 ;
     RECT  11.369 6.576 12.085 6.696 ;
     RECT  11.845 26.592 12.133 28.536 ;
     RECT  11.981 30.384 12.149 31.368 ;
     RECT  12.085 2.832 12.161 6.696 ;
     RECT  12.161 2.88 12.227 6.696 ;
     RECT  11.941 9.648 12.265 10.824 ;
     RECT  12.133 26.496 12.373 28.536 ;
     RECT  12.373 26.4 12.409 28.536 ;
     RECT  12.149 29.664 12.409 31.368 ;
     RECT  12.265 9.504 12.437 10.824 ;
     RECT  12.227 6.672 12.553 6.696 ;
     RECT  12.553 6.672 12.613 6.84 ;
     RECT  11.795 13.056 12.725 13.464 ;
     RECT  11.333 14.64 12.725 14.808 ;
     RECT  12.437 9.504 12.853 11.4 ;
     RECT  11.843 33.024 12.853 33.048 ;
     RECT  12.853 8.976 12.913 11.4 ;
     RECT  12.853 32.496 12.949 33.048 ;
     RECT  12.613 6.672 13.021 7.08 ;
     RECT  12.913 8.496 13.055 11.4 ;
     RECT  13.055 8.496 13.093 11.976 ;
     RECT  12.725 13.056 13.093 14.808 ;
     RECT  9.011 1.728 13.208 1.752 ;
     RECT  12.227 2.88 13.208 5.64 ;
     RECT  13.021 6.672 13.208 7.464 ;
     RECT  13.093 8.496 13.208 14.808 ;
     RECT  11.893 15.792 13.208 15.864 ;
     RECT  10.289 17.04 13.208 17.064 ;
     RECT  12.409 26.4 13.208 31.368 ;
     RECT  12.949 32.496 13.208 33.672 ;
     RECT  13.208 1.728 13.381 33.672 ;
     RECT  13.381 1.728 13.504 33.768 ;
     RECT  13.504 33.024 13.525 33.768 ;
     RECT  13.504 1.728 13.619 5.16 ;
     RECT  13.504 13.152 13.619 14.664 ;
     RECT  13.504 6.144 13.66 7.128 ;
     RECT  13.619 13.296 13.667 14.664 ;
     RECT  13.504 17.616 13.681 17.64 ;
     RECT  13.619 1.728 13.789 2.328 ;
     RECT  13.504 27.984 13.811 31.944 ;
     RECT  13.667 13.68 13.853 14.664 ;
     RECT  13.853 13.68 13.925 14.616 ;
     RECT  12.62 0.288 13.955 0.312 ;
     RECT  13.811 28.464 13.997 31.944 ;
     RECT  13.619 3.312 14.033 5.16 ;
     RECT  13.925 13.68 14.113 14.376 ;
     RECT  13.525 33.024 14.147 33.864 ;
     RECT  14.147 33.024 14.243 33.768 ;
     RECT  13.504 26.16 14.465 26.856 ;
     RECT  13.504 9.072 14.497 10.92 ;
     RECT  14.497 8.208 14.509 10.92 ;
     RECT  14.465 26.208 14.533 26.856 ;
     RECT  13.504 15.696 14.573 16.536 ;
     RECT  14.533 26.208 14.677 26.904 ;
     RECT  14.033 3.408 14.689 5.16 ;
     RECT  14.509 9.504 14.713 10.92 ;
     RECT  14.677 26.208 15.001 27.336 ;
     RECT  15.001 26.208 15.109 27.864 ;
     RECT  14.965 12.912 15.113 12.936 ;
     RECT  15.109 26.208 15.145 27.912 ;
     RECT  13.997 29.04 15.145 31.944 ;
     RECT  14.243 33.024 15.157 33.672 ;
     RECT  15.145 26.208 15.193 31.944 ;
     RECT  15.145 5.664 15.251 5.688 ;
     RECT  14.113 14.352 15.301 14.376 ;
     RECT  13.789 1.728 15.325 1.752 ;
     RECT  14.573 15.696 15.361 15.72 ;
     RECT  15.193 26.208 15.395 27.384 ;
     RECT  15.193 28.512 15.445 31.944 ;
     RECT  15.157 32.976 15.445 33.672 ;
     RECT  15.445 28.512 15.491 33.672 ;
     RECT  15.181 25.104 15.539 25.128 ;
     RECT  15.395 26.208 15.581 27.336 ;
     RECT  14.713 9.504 15.613 11.4 ;
     RECT  15.325 1.728 15.635 1.8 ;
     RECT  14.509 8.208 15.788 8.232 ;
     RECT  15.613 9.264 15.788 11.4 ;
     RECT  15.721 17.04 15.805 17.064 ;
     RECT  14.689 3.408 15.829 4.584 ;
     RECT  15.361 15.408 15.829 15.72 ;
     RECT  15.788 8.208 15.875 11.4 ;
     RECT  15.829 3.408 15.913 5.016 ;
     RECT  15.397 12.528 15.971 12.552 ;
     RECT  15.301 14.208 15.973 14.376 ;
     RECT  13.66 6.816 16.021 7.128 ;
     RECT  15.829 15.36 16.069 15.72 ;
     RECT  15.973 13.68 16.121 14.376 ;
     RECT  15.491 28.848 16.163 33.672 ;
     RECT  15.581 27.072 16.165 27.336 ;
     RECT  16.021 6.72 16.261 7.128 ;
     RECT  15.875 8.208 16.261 8.232 ;
     RECT  16.261 5.712 16.403 5.736 ;
     RECT  16.121 13.68 16.405 13.896 ;
     RECT  16.069 15.36 16.405 16.536 ;
     RECT  16.405 13.056 16.499 13.896 ;
     RECT  16.405 15.216 16.547 16.536 ;
     RECT  16.499 13.872 16.595 13.896 ;
     RECT  16.621 25.104 16.733 25.128 ;
     RECT  16.165 27.072 16.885 27.288 ;
     RECT  16.261 6.72 16.901 8.232 ;
     RECT  15.875 9.264 16.901 11.4 ;
     RECT  16.547 15.216 16.913 16.488 ;
     RECT  16.901 6.72 17.075 11.4 ;
     RECT  16.163 28.848 17.093 33.096 ;
     RECT  17.075 7.92 17.129 11.4 ;
     RECT  17.129 9.072 17.165 11.4 ;
     RECT  15.913 3.408 17.197 4.584 ;
     RECT  16.885 26.736 17.221 27.288 ;
     RECT  17.093 28.848 17.233 31.944 ;
     RECT  17.165 10.848 17.305 11.4 ;
     RECT  17.221 26.736 17.305 27.384 ;
     RECT  17.305 26.736 17.317 27.48 ;
     RECT  17.233 28.512 17.317 31.944 ;
     RECT  17.093 33.024 17.485 33.096 ;
     RECT  17.197 3.408 17.516 5.16 ;
     RECT  17.516 3.408 17.603 5.688 ;
     RECT  17.603 3.408 17.668 5.16 ;
     RECT  17.521 0.528 17.939 0.552 ;
     RECT  17.668 3.36 18.085 5.16 ;
     RECT  17.075 6.72 18.085 6.84 ;
     RECT  17.129 7.92 18.085 7.944 ;
     RECT  16.913 15.216 18.085 15.72 ;
     RECT  18.085 3.312 18.133 5.16 ;
     RECT  18.085 14.784 18.133 15.72 ;
     RECT  17.485 33.024 18.179 33.672 ;
     RECT  17.377 12.528 18.313 12.552 ;
     RECT  18.133 14.256 18.313 15.72 ;
     RECT  18.277 25.104 18.373 25.128 ;
     RECT  17.317 26.736 18.373 31.944 ;
     RECT  18.085 6.72 18.449 7.944 ;
     RECT  15.635 1.728 18.469 1.752 ;
     RECT  18.133 2.784 18.469 5.16 ;
     RECT  18.469 1.728 18.608 5.16 ;
     RECT  18.449 6.24 18.608 7.944 ;
     RECT  17.165 9.072 18.608 9.864 ;
     RECT  17.305 10.848 18.608 11.544 ;
     RECT  18.313 12.528 18.608 15.72 ;
     RECT  17.605 16.896 18.608 16.92 ;
     RECT  18.341 18.192 18.608 18.216 ;
     RECT  18.373 25.104 18.608 25.224 ;
     RECT  18.373 26.736 18.608 32.568 ;
     RECT  18.608 1.728 18.904 32.568 ;
     RECT  18.904 2.784 18.929 5.736 ;
     RECT  18.904 27.264 18.988 32.568 ;
     RECT  17.989 0.288 19.043 0.312 ;
     RECT  18.929 2.832 19.117 5.736 ;
     RECT  18.988 27.264 19.18 31.944 ;
     RECT  19.045 0.384 19.187 0.408 ;
     RECT  19.18 27.264 19.325 27.96 ;
     RECT  19.117 2.88 19.405 5.736 ;
     RECT  18.179 33.648 19.42 33.672 ;
     RECT  18.904 25.104 19.541 25.128 ;
     RECT  18.904 11.376 19.585 11.544 ;
     RECT  19.325 27.312 19.667 27.96 ;
     RECT  18.904 1.728 19.693 1.752 ;
     RECT  19.477 33.024 19.757 33.192 ;
     RECT  18.904 16.512 19.793 16.536 ;
     RECT  18.904 6.768 19.801 9.864 ;
     RECT  18.904 14.736 19.909 14.904 ;
     RECT  19.585 11.52 19.933 11.544 ;
     RECT  18.904 12.528 19.933 12.552 ;
     RECT  19.801 6.768 19.955 7.992 ;
     RECT  19.955 6.768 19.969 7.224 ;
     RECT  19.757 33.024 19.98 33.096 ;
     RECT  19.405 2.88 20.101 5.112 ;
     RECT  19.933 11.52 20.117 12.552 ;
     RECT  19.801 9.072 20.149 9.864 ;
     RECT  19.18 28.992 20.261 31.944 ;
     RECT  19.98 32.976 20.261 33.096 ;
     RECT  20.261 29.664 20.321 31.944 ;
     RECT  20.117 11.952 20.341 12.552 ;
     RECT  20.101 2.352 20.387 5.112 ;
     RECT  20.341 12 20.429 12.552 ;
     RECT  20.429 12 20.485 12.936 ;
     RECT  18.904 26.208 20.485 26.232 ;
     RECT  19.667 27.312 20.485 27.768 ;
     RECT  20.387 2.832 20.513 5.112 ;
     RECT  20.149 9.072 20.657 10.392 ;
     RECT  20.485 12 20.657 13.032 ;
     RECT  20.485 26.208 20.677 27.768 ;
     RECT  20.321 29.664 20.701 32.472 ;
     RECT  19.909 14.112 20.725 14.904 ;
     RECT  19.969 6.288 20.729 7.224 ;
     RECT  20.725 14.112 20.729 15.096 ;
     RECT  20.701 29.664 20.765 32.04 ;
     RECT  20.677 26.208 20.773 27.96 ;
     RECT  20.657 9.072 20.828 9.288 ;
     RECT  20.828 9.024 20.915 9.288 ;
     RECT  20.729 14.256 20.945 15.096 ;
     RECT  20.513 3.408 20.963 5.112 ;
     RECT  20.765 29.664 21.017 30.84 ;
     RECT  20.965 18.768 21.107 18.792 ;
     RECT  20.869 33.648 21.121 33.672 ;
     RECT  20.945 14.256 21.197 14.904 ;
     RECT  21.121 33.648 21.251 33.72 ;
     RECT  20.657 10.272 21.253 10.392 ;
     RECT  20.657 12.864 21.301 13.032 ;
     RECT  20.821 16.512 21.301 16.536 ;
     RECT  20.773 26.208 21.373 28.152 ;
     RECT  21.253 10.272 21.443 10.968 ;
     RECT  20.729 6.816 21.493 7.224 ;
     RECT  21.373 26.208 21.529 28.44 ;
     RECT  21.493 6.816 21.593 7.992 ;
     RECT  21.017 29.808 21.601 30.84 ;
     RECT  21.301 15.936 21.629 16.536 ;
     RECT  21.301 12.864 21.635 13.128 ;
     RECT  21.251 33.648 21.637 33.672 ;
     RECT  20.963 3.408 21.661 4.584 ;
     RECT  21.635 12.864 21.661 13.032 ;
     RECT  21.197 14.256 21.731 14.808 ;
     RECT  21.661 2.832 21.745 4.584 ;
     RECT  21.661 12.72 21.773 13.032 ;
     RECT  21.601 30.24 21.913 30.84 ;
     RECT  20.765 31.872 21.913 32.04 ;
     RECT  21.637 33.072 21.913 33.672 ;
     RECT  20.915 9.072 21.98 9.288 ;
     RECT  21.98 8.544 21.985 9.288 ;
     RECT  21.593 6.816 22.021 7.464 ;
     RECT  21.443 10.848 22.021 10.968 ;
     RECT  21.773 12.72 22.021 12.984 ;
     RECT  22.021 6.24 22.061 7.464 ;
     RECT  21.985 8.544 22.115 9.672 ;
     RECT  21.913 30.24 22.115 33.672 ;
     RECT  21.529 26.736 22.241 28.44 ;
     RECT  22.241 27.36 22.268 28.44 ;
     RECT  22.193 0.192 22.277 0.216 ;
     RECT  21.745 3.312 22.3 4.584 ;
     RECT  20.753 1.728 22.316 1.752 ;
     RECT  22.316 1.68 22.403 1.752 ;
     RECT  22.403 1.728 22.501 1.752 ;
     RECT  22.061 6.24 22.561 7.368 ;
     RECT  22.115 31.344 22.573 33.672 ;
     RECT  22.573 31.344 22.662 31.992 ;
     RECT  22.501 1.728 22.673 2.328 ;
     RECT  22.115 8.544 22.739 9.384 ;
     RECT  22.662 31.344 22.745 31.944 ;
     RECT  22.561 6.192 22.813 7.368 ;
     RECT  21.731 14.544 22.885 14.808 ;
     RECT  22.885 14.208 23.029 14.808 ;
     RECT  21.629 15.936 23.029 15.96 ;
     RECT  22.268 27.36 23.065 29.16 ;
     RECT  22.115 30.24 23.065 30.264 ;
     RECT  22.021 10.848 23.137 12.984 ;
     RECT  23.065 27.36 23.137 30.264 ;
     RECT  22.745 31.344 23.137 31.56 ;
     RECT  23.029 14.208 23.173 15.96 ;
     RECT  22.597 17.04 23.173 17.064 ;
     RECT  22.813 6.096 23.221 7.368 ;
     RECT  22.573 33.072 23.317 33.672 ;
     RECT  23.317 33.072 23.365 33.72 ;
     RECT  22.3 3.408 23.381 4.584 ;
     RECT  23.137 27.36 23.389 31.56 ;
     RECT  23.137 10.848 23.461 13.08 ;
     RECT  23.365 33.072 23.465 33.768 ;
     RECT  23.381 2.832 23.533 4.584 ;
     RECT  23.533 2.832 23.557 5.016 ;
     RECT  23.221 6.096 23.701 8.184 ;
     RECT  22.739 9.36 23.701 9.384 ;
     RECT  23.465 33.072 23.795 33.72 ;
     RECT  23.389 26.688 23.797 31.56 ;
     RECT  23.795 33.072 23.797 33.672 ;
     RECT  22.673 1.728 24.008 1.752 ;
     RECT  23.557 2.832 24.008 5.112 ;
     RECT  23.701 6.096 24.008 9.384 ;
     RECT  23.461 10.848 24.008 13.128 ;
     RECT  23.173 14.208 24.008 17.064 ;
     RECT  23.797 26.688 24.008 33.672 ;
     RECT  23.941 0.288 24.085 0.312 ;
     RECT  24.085 0.288 24.229 0.408 ;
     RECT  24.008 1.728 24.304 33.672 ;
     RECT  24.229 0.288 24.361 0.456 ;
     RECT  24.304 1.728 24.401 2.04 ;
     RECT  24.361 0.192 24.445 0.456 ;
     RECT  24.304 6.096 24.445 10.968 ;
     RECT  24.445 0.288 24.467 0.456 ;
     RECT  24.445 6.096 24.467 7.08 ;
     RECT  24.467 0.384 24.476 0.456 ;
     RECT  24.401 1.728 24.476 1.752 ;
     RECT  24.304 3.312 24.481 5.112 ;
     RECT  24.476 0.384 24.515 1.752 ;
     RECT  24.515 1.104 24.563 1.752 ;
     RECT  24.304 22.8 24.563 22.824 ;
     RECT  24.445 8.448 24.617 10.968 ;
     RECT  24.304 26.208 24.725 33.672 ;
     RECT  24.725 28.464 24.769 33.672 ;
     RECT  24.304 11.952 24.877 15.384 ;
     RECT  24.481 3.312 24.985 4.584 ;
     RECT  24.617 8.544 24.985 10.968 ;
     RECT  24.467 6.096 25.091 6.888 ;
     RECT  24.985 3.408 25.18 4.584 ;
     RECT  24.769 30.72 25.229 33.672 ;
     RECT  24.725 26.208 25.283 27.432 ;
     RECT  25.091 6.096 25.481 6.264 ;
     RECT  24.563 1.728 25.628 1.752 ;
     RECT  25.628 1.104 25.715 1.752 ;
     RECT  25.283 26.688 25.765 27.432 ;
     RECT  24.769 28.464 25.765 29.688 ;
     RECT  24.877 11.952 25.909 13.08 ;
     RECT  24.877 14.208 25.909 15.384 ;
     RECT  24.304 16.56 25.909 16.584 ;
     RECT  25.765 26.688 25.945 29.688 ;
     RECT  25.229 30.72 25.945 32.52 ;
     RECT  25.229 33.648 25.957 33.672 ;
     RECT  25.909 11.952 26.003 16.584 ;
     RECT  25.481 6.24 26.065 6.264 ;
     RECT  24.985 8.832 26.125 10.968 ;
     RECT  26.125 8.112 26.129 10.968 ;
     RECT  25.525 5.088 26.147 5.112 ;
     RECT  26.003 11.952 26.201 13.128 ;
     RECT  25.18 3.408 26.225 4.008 ;
     RECT  26.225 3.408 26.237 4.632 ;
     RECT  26.197 6.816 26.293 6.84 ;
     RECT  26.129 8.112 26.293 9.672 ;
     RECT  26.129 10.8 26.3 10.968 ;
     RECT  26.201 11.952 26.3 12.792 ;
     RECT  25.715 1.728 26.305 1.752 ;
     RECT  25.945 26.688 26.305 32.52 ;
     RECT  26.237 4.608 26.309 4.632 ;
     RECT  26.293 6.816 26.381 9.672 ;
     RECT  26.305 26.208 26.435 32.52 ;
     RECT  26.003 14.256 26.453 16.584 ;
     RECT  25.957 33.648 26.485 33.72 ;
     RECT  26.453 14.256 26.497 15.384 ;
     RECT  26.485 33.648 26.597 33.768 ;
     RECT  26.497 14.256 26.62 15.096 ;
     RECT  26.597 33.696 26.627 33.768 ;
     RECT  26.3 10.8 26.669 12.792 ;
     RECT  26.435 26.64 26.777 32.52 ;
     RECT  26.62 14.256 26.785 14.856 ;
     RECT  26.453 16.56 26.849 16.584 ;
     RECT  26.627 33.744 26.915 33.768 ;
     RECT  26.305 1.728 26.989 1.8 ;
     RECT  26.777 26.832 26.993 32.52 ;
     RECT  26.993 26.832 27.065 28.008 ;
     RECT  26.989 1.152 27.155 1.8 ;
     RECT  27.155 1.728 27.233 1.8 ;
     RECT  26.785 14.256 27.301 14.28 ;
     RECT  26.993 29.088 27.353 32.52 ;
     RECT  26.237 3.408 27.397 3.432 ;
     RECT  26.381 8.112 27.461 9.672 ;
     RECT  26.669 10.8 27.493 11.4 ;
     RECT  27.397 3.408 27.541 4.008 ;
     RECT  27.445 17.616 27.569 17.64 ;
     RECT  27.353 29.088 27.635 31.368 ;
     RECT  27.541 3.408 27.637 4.584 ;
     RECT  26.381 6.816 27.637 6.84 ;
     RECT  26.669 12.768 27.637 12.792 ;
     RECT  27.301 14.016 27.637 14.28 ;
     RECT  27.493 10.224 27.641 11.4 ;
     RECT  27.637 12.768 27.709 14.28 ;
     RECT  27.641 10.704 27.745 11.4 ;
     RECT  27.709 12.528 27.745 14.28 ;
     RECT  27.745 10.704 27.781 14.28 ;
     RECT  27.781 10.704 27.793 15.096 ;
     RECT  27.233 1.728 27.877 1.848 ;
     RECT  27.637 3.216 27.877 4.584 ;
     RECT  27.353 32.496 27.929 32.52 ;
     RECT  27.793 11.808 27.965 15.096 ;
     RECT  27.637 6.816 27.973 6.888 ;
     RECT  27.065 27.312 27.973 28.008 ;
     RECT  27.635 29.088 27.973 29.112 ;
     RECT  27.973 6.144 28.06 6.888 ;
     RECT  27.973 27.312 28.069 29.112 ;
     RECT  28.069 27.264 28.133 29.112 ;
     RECT  27.877 1.728 28.141 4.584 ;
     RECT  27.965 14.256 28.145 15.096 ;
     RECT  28.145 14.736 28.213 15.096 ;
     RECT  27.461 8.112 28.268 9.144 ;
     RECT  28.141 1.728 28.325 5.112 ;
     RECT  28.213 14.736 28.357 15.384 ;
     RECT  27.793 10.704 28.361 10.824 ;
     RECT  28.277 18.192 28.361 18.216 ;
     RECT  28.325 1.728 28.451 1.752 ;
     RECT  28.06 6.672 28.501 6.888 ;
     RECT  28.268 7.968 28.501 9.144 ;
     RECT  28.117 33.648 28.549 33.672 ;
     RECT  27.635 30.192 28.597 31.368 ;
     RECT  28.133 26.736 28.681 29.112 ;
     RECT  28.597 30.192 28.681 31.464 ;
     RECT  28.549 33.072 28.685 33.672 ;
     RECT  28.681 26.736 28.693 31.464 ;
     RECT  28.361 10.8 28.969 10.824 ;
     RECT  27.965 11.808 28.969 13.128 ;
     RECT  29.077 0.288 29.105 0.312 ;
     RECT  28.501 6.672 29.105 9.144 ;
     RECT  29.105 0.288 29.125 0.6 ;
     RECT  29.125 32.64 29.173 32.664 ;
     RECT  29.105 6.672 29.221 9.672 ;
     RECT  28.693 26.448 29.221 31.464 ;
     RECT  29.173 32.544 29.221 32.664 ;
     RECT  29.125 0.288 29.315 0.696 ;
     RECT  28.325 2.784 29.408 5.112 ;
     RECT  29.221 6.288 29.408 9.672 ;
     RECT  28.969 10.8 29.408 13.128 ;
     RECT  28.357 14.736 29.408 15.96 ;
     RECT  29.221 26.448 29.408 32.664 ;
     RECT  29.315 0.288 29.603 0.552 ;
     RECT  29.408 2.148 29.704 32.664 ;
     RECT  29.704 11.136 29.765 14.952 ;
     RECT  29.603 0.288 29.843 0.312 ;
     RECT  29.765 11.52 29.953 14.952 ;
     RECT  29.704 15.936 30.061 15.96 ;
     RECT  29.953 11.52 30.089 13.32 ;
     RECT  29.704 6.672 30.169 6.888 ;
     RECT  29.704 27.216 30.227 32.664 ;
     RECT  29.704 7.92 30.275 8.472 ;
     RECT  30.121 1.728 30.323 1.8 ;
     RECT  29.704 9.696 30.529 10.152 ;
     RECT  30.089 11.904 30.565 13.32 ;
     RECT  28.685 33.648 30.589 33.672 ;
     RECT  30.227 27.216 30.593 32.568 ;
     RECT  30.565 11.952 30.611 13.32 ;
     RECT  29.704 2.832 30.737 5.16 ;
     RECT  30.593 27.216 30.769 28.344 ;
     RECT  30.589 33.648 30.769 33.864 ;
     RECT  30.275 8.448 30.845 8.472 ;
     RECT  30.529 9.792 30.86 10.152 ;
     RECT  30.611 11.952 30.995 13.128 ;
     RECT  29.953 14.928 31.021 14.952 ;
     RECT  30.769 26.736 31.061 28.344 ;
     RECT  31.013 18.192 31.097 18.216 ;
     RECT  30.769 33.648 31.139 34.008 ;
     RECT  31.057 16.512 31.237 16.536 ;
     RECT  30.169 6.672 31.241 6.696 ;
     RECT  31.021 14.736 31.273 14.952 ;
     RECT  31.273 14.256 31.357 14.952 ;
     RECT  30.593 29.52 31.475 32.568 ;
     RECT  30.86 9.792 31.525 10.248 ;
     RECT  30.995 11.952 31.529 12.792 ;
     RECT  30.737 2.832 31.621 4.584 ;
     RECT  31.357 14.928 31.661 14.952 ;
     RECT  31.237 15.936 31.661 16.536 ;
     RECT  31.061 26.784 31.741 28.344 ;
     RECT  31.621 5.712 31.745 5.736 ;
     RECT  31.741 26.784 31.745 28.488 ;
     RECT  31.489 33.072 31.763 33.096 ;
     RECT  31.745 28.464 31.777 28.488 ;
     RECT  31.475 29.52 31.777 31.944 ;
     RECT  31.661 14.928 31.789 16.536 ;
     RECT  31.669 11.424 31.859 11.448 ;
     RECT  31.381 7.968 31.885 7.992 ;
     RECT  31.885 7.92 31.921 7.992 ;
     RECT  31.525 9.072 31.921 10.248 ;
     RECT  31.621 2.736 31.925 4.584 ;
     RECT  31.777 28.464 32.003 31.944 ;
     RECT  31.921 7.92 32.06 10.248 ;
     RECT  32.06 7.92 32.243 10.92 ;
     RECT  31.789 14.928 32.291 15.96 ;
     RECT  31.925 3.408 32.317 4.584 ;
     RECT  32.209 6.864 32.353 6.888 ;
     RECT  32.353 6.24 32.393 6.888 ;
     RECT  32.243 7.92 32.401 9.72 ;
     RECT  32.317 3.408 32.435 5.16 ;
     RECT  32.003 29.04 32.437 31.944 ;
     RECT  32.437 29.04 32.465 31.992 ;
     RECT  32.291 14.928 32.485 15.384 ;
     RECT  30.323 1.728 32.569 1.752 ;
     RECT  32.401 7.92 32.597 9.672 ;
     RECT  32.485 14.112 32.617 15.384 ;
     RECT  31.529 12.768 32.713 12.792 ;
     RECT  32.617 14.112 32.713 14.952 ;
     RECT  32.713 12.768 32.741 14.952 ;
     RECT  31.745 26.784 32.821 27.384 ;
     RECT  32.597 7.392 32.825 9.672 ;
     RECT  32.741 11.904 32.825 14.952 ;
     RECT  32.569 1.728 32.893 1.8 ;
     RECT  32.825 7.392 32.933 8.568 ;
     RECT  32.393 6.24 32.963 6.264 ;
     RECT  32.821 26.784 32.972 27.864 ;
     RECT  32.893 1.728 32.977 2.28 ;
     RECT  32.435 3.408 33.013 4.68 ;
     RECT  32.869 33.648 33.013 33.672 ;
     RECT  32.821 0.288 33.059 0.312 ;
     RECT  32.972 26.784 33.061 27.96 ;
     RECT  32.933 7.392 33.1 7.992 ;
     RECT  33.013 2.736 33.113 4.68 ;
     RECT  32.977 1.728 33.145 1.752 ;
     RECT  33.013 33.648 33.155 33.72 ;
     RECT  33.145 1.152 33.229 1.752 ;
     RECT  33.001 16.512 33.253 16.536 ;
     RECT  33.061 26.736 33.329 27.96 ;
     RECT  33.1 7.92 33.347 7.992 ;
     RECT  33.113 2.736 33.395 4.584 ;
     RECT  32.825 9.648 33.395 9.672 ;
     RECT  33.253 16.176 33.395 16.536 ;
     RECT  32.465 29.712 33.433 31.992 ;
     RECT  32.825 11.952 33.437 14.952 ;
     RECT  33.433 29.664 33.445 31.992 ;
     RECT  33.395 3.84 33.473 4.584 ;
     RECT  33.437 13.632 33.481 14.952 ;
     RECT  33.481 14.832 33.517 14.952 ;
     RECT  33.395 16.512 33.545 16.536 ;
     RECT  33.445 29.472 33.548 31.992 ;
     RECT  33.481 13.632 33.731 13.656 ;
     RECT  33.329 26.736 33.781 26.808 ;
     RECT  33.329 27.888 33.805 27.96 ;
     RECT  33.395 2.736 33.841 2.856 ;
     RECT  33.548 29.472 33.925 32.376 ;
     RECT  33.644 5.664 33.973 5.832 ;
     RECT  33.229 1.728 34.069 1.752 ;
     RECT  33.347 7.92 34.124 7.944 ;
     RECT  32.243 10.896 34.261 10.92 ;
     RECT  33.437 11.952 34.261 11.976 ;
     RECT  33.925 29.04 34.309 32.376 ;
     RECT  33.155 33.648 34.309 33.672 ;
     RECT  34.309 28.992 34.369 32.376 ;
     RECT  34.124 7.392 34.441 7.944 ;
     RECT  33.473 3.888 34.501 4.584 ;
     RECT  34.369 28.512 34.549 32.376 ;
     RECT  34.309 33.648 34.549 33.72 ;
     RECT  34.549 28.512 34.553 33.72 ;
     RECT  34.501 3.408 34.645 4.584 ;
     RECT  33.973 5.664 34.645 6.264 ;
     RECT  34.553 28.512 34.739 33.672 ;
     RECT  34.069 1.728 34.808 2.232 ;
     RECT  34.645 3.408 34.808 6.264 ;
     RECT  34.441 7.392 34.808 7.992 ;
     RECT  34.513 9.12 34.808 9.144 ;
     RECT  34.261 10.896 34.808 11.976 ;
     RECT  33.517 14.928 34.808 14.952 ;
     RECT  33.781 26.688 34.808 26.808 ;
     RECT  34.739 28.512 34.808 33.096 ;
     RECT  34.808 1.728 35.104 33.096 ;
     RECT  35.104 7.92 35.219 7.944 ;
     RECT  34.645 0.288 35.267 0.312 ;
     RECT  35.104 11.952 35.267 13.08 ;
     RECT  35.104 30.576 35.267 33.096 ;
     RECT  35.104 3.168 35.315 4.248 ;
     RECT  35.104 26.784 35.315 26.808 ;
     RECT  35.267 30.816 35.315 33.096 ;
     RECT  35.267 11.952 35.363 12.552 ;
     RECT  35.315 30.816 35.363 32.472 ;
     RECT  35.363 31.296 35.417 32.472 ;
     RECT  35.104 1.728 35.525 1.848 ;
     RECT  35.104 14.208 35.525 14.952 ;
     RECT  35.104 10.8 35.569 10.824 ;
     RECT  35.315 3.984 35.597 4.008 ;
     RECT  35.525 14.928 35.633 14.952 ;
     RECT  35.417 31.344 35.651 32.472 ;
     RECT  35.104 9.648 35.677 9.672 ;
     RECT  35.525 1.728 35.795 1.8 ;
     RECT  35.795 1.728 35.813 1.752 ;
     RECT  35.104 29.088 35.891 29.112 ;
     RECT  35.845 33.648 35.929 33.672 ;
     RECT  35.104 5.76 35.957 5.784 ;
     RECT  35.363 12.528 35.957 12.552 ;
     RECT  35.651 32.304 36.677 32.472 ;
     RECT  36.677 32.448 37.541 32.472 ;
     RECT  40.208 2.148 40.312 32.412 ;
     RECT  40.312 2.418 40.504 32.142 ;
    LAYER M5 ;
     RECT  6.528 0.144 35.784 1.763 ;
     RECT  6.672 1.763 35.784 1.811 ;
     RECT  27.264 1.811 35.496 1.859 ;
     RECT  2.4 2.137 2.52 2.151 ;
     RECT  40.2 2.137 40.32 2.151 ;
     RECT  6.816 1.811 26.28 2.243 ;
     RECT  6.96 2.243 26.28 3.397 ;
     RECT  27.408 1.859 35.496 3.397 ;
     RECT  6.96 3.397 35.496 4.019 ;
     RECT  7.392 4.019 35.304 4.259 ;
     RECT  7.392 4.259 35.208 4.595 ;
     RECT  7.632 4.595 16.584 5.171 ;
     RECT  7.632 5.171 14.088 5.699 ;
     RECT  17.568 4.595 35.208 5.699 ;
     RECT  7.8 5.699 14.088 5.747 ;
     RECT  7.8 5.747 11.784 6.851 ;
     RECT  10.032 6.851 11.784 7.045 ;
     RECT  12.768 5.747 14.088 7.045 ;
     RECT  15.072 5.171 16.584 7.381 ;
     RECT  17.664 5.699 35.208 7.381 ;
     RECT  15.072 7.381 35.208 7.955 ;
     RECT  7.8 6.851 8.904 7.957 ;
     RECT  10.032 7.045 14.088 7.957 ;
     RECT  7.8 7.957 14.088 9.061 ;
     RECT  15.072 7.955 35.112 9.061 ;
     RECT  7.8 9.061 35.112 9.637 ;
     RECT  7.8 9.637 35.64 10.117 ;
     RECT  7.392 10.117 35.64 10.165 ;
     RECT  7.2 10.165 35.64 10.883 ;
     RECT  7.2 10.883 24.648 11.413 ;
     RECT  7.008 11.413 24.648 11.941 ;
     RECT  7.008 11.941 24.984 12.997 ;
     RECT  25.968 10.883 35.64 12.997 ;
     RECT  7.008 12.997 35.64 13.715 ;
     RECT  7.008 13.715 10.824 14.773 ;
     RECT  11.952 13.715 35.64 14.773 ;
     RECT  7.008 14.773 35.64 14.867 ;
     RECT  0.24 9.829 0.264 15.923 ;
     RECT  7.008 14.867 32.952 16.165 ;
     RECT  33.984 14.867 35.64 16.165 ;
     RECT  7.008 16.165 35.64 29.077 ;
     RECT  7.008 29.077 35.88 31.813 ;
     RECT  6.96 31.813 35.88 31.861 ;
     RECT  2.4 2.151 2.712 32.409 ;
     RECT  40.2 2.151 40.512 32.409 ;
     RECT  2.4 32.409 2.52 32.423 ;
     RECT  40.2 32.409 40.32 32.423 ;
     RECT  6.816 31.861 35.88 32.437 ;
     RECT  6.672 32.437 35.88 33.061 ;
     RECT  6.528 33.061 35.88 33.683 ;
     RECT  6.528 33.683 35.784 34.384 ;
     RECT  26.28 1.811 27.264 1.859 ;
     RECT  26.28 1.859 27.408 3.397 ;
     RECT  16.584 4.595 17.568 5.699 ;
     RECT  14.088 5.171 15.072 9.061 ;
     RECT  16.584 5.699 17.664 7.381 ;
     RECT  11.784 5.747 12.768 7.045 ;
     RECT  8.904 6.851 10.032 7.957 ;
     RECT  24.648 10.883 25.968 11.941 ;
     RECT  24.984 11.941 25.968 12.997 ;
     RECT  10.824 13.715 11.952 14.773 ;
     RECT  32.952 14.867 33.984 16.165 ;
  END
END ot_s81_pq_bc_slice0
END LIBRARY
